VERSION 5.7 ;
  NOWIREEXTENSIONATPIN ON ;
  DIVIDERCHAR "/" ;
  BUSBITCHARS "[]" ;
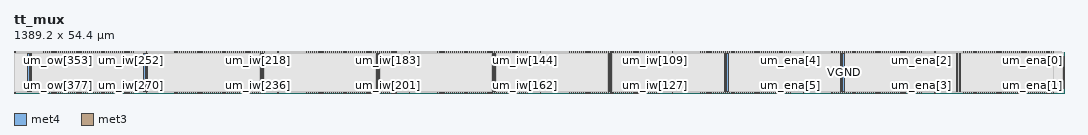
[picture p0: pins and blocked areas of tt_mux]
MACRO tt_mux
  CLASS BLOCK ;
  FOREIGN tt_mux ;
  ORIGIN 0.000 0.000 ;
  SIZE 1389.200 BY 54.400 ;
  PIN VDPWR
    DIRECTION INOUT ;
    USE POWER ;
    PORT
      LAYER met4 ;
        RECT 18.280 2.480 19.880 51.920 ;
    END
    PORT
      LAYER met4 ;
        RECT 171.880 2.480 173.480 51.920 ;
    END
    PORT
      LAYER met4 ;
        RECT 325.480 2.480 327.080 51.920 ;
    END
    PORT
      LAYER met4 ;
        RECT 479.080 2.480 480.680 51.920 ;
    END
    PORT
      LAYER met4 ;
        RECT 632.680 2.480 634.280 51.920 ;
    END
    PORT
      LAYER met4 ;
        RECT 786.280 2.480 787.880 51.920 ;
    END
    PORT
      LAYER met4 ;
        RECT 939.880 2.480 941.480 51.920 ;
    END
    PORT
      LAYER met4 ;
        RECT 1093.480 2.480 1095.080 51.920 ;
    END
    PORT
      LAYER met4 ;
        RECT 1247.080 2.480 1248.680 51.920 ;
    END
  END VDPWR
  PIN VGND
    DIRECTION INOUT ;
    USE GROUND ;
    PORT
      LAYER met4 ;
        RECT 21.580 2.480 23.180 51.920 ;
    END
    PORT
      LAYER met4 ;
        RECT 175.180 2.480 176.780 51.920 ;
    END
    PORT
      LAYER met4 ;
        RECT 328.780 2.480 330.380 51.920 ;
    END
    PORT
      LAYER met4 ;
        RECT 482.380 2.480 483.980 51.920 ;
    END
    PORT
      LAYER met4 ;
        RECT 635.980 2.480 637.580 51.920 ;
    END
    PORT
      LAYER met4 ;
        RECT 789.580 2.480 791.180 51.920 ;
    END
    PORT
      LAYER met4 ;
        RECT 943.180 2.480 944.780 51.920 ;
    END
    PORT
      LAYER met4 ;
        RECT 1096.780 2.480 1098.380 51.920 ;
    END
    PORT
      LAYER met4 ;
        RECT 1250.380 2.480 1251.980 51.920 ;
    END
  END VGND
  PIN addr[0]
    DIRECTION INPUT ;
    USE SIGNAL ;
    ANTENNAGATEAREA 0.252000 ;
    PORT
      LAYER met3 ;
        RECT 1388.200 47.790 1389.200 48.090 ;
    END
  END addr[0]
  PIN addr[1]
    DIRECTION INPUT ;
    USE SIGNAL ;
    ANTENNAGATEAREA 0.990000 ;
    PORT
      LAYER met3 ;
        RECT 1388.200 47.110 1389.200 47.410 ;
    END
  END addr[1]
  PIN addr[2]
    DIRECTION INPUT ;
    USE SIGNAL ;
    ANTENNAGATEAREA 0.495000 ;
    PORT
      LAYER met3 ;
        RECT 1388.200 46.430 1389.200 46.730 ;
    END
  END addr[2]
  PIN addr[3]
    DIRECTION INPUT ;
    USE SIGNAL ;
    ANTENNAGATEAREA 0.990000 ;
    PORT
      LAYER met3 ;
        RECT 1388.200 45.750 1389.200 46.050 ;
    END
  END addr[3]
  PIN k_one
    DIRECTION OUTPUT ;
    USE SIGNAL ;
    PORT
      LAYER met3 ;
        RECT 1388.200 45.070 1389.200 45.370 ;
    END
  END k_one
  PIN k_zero
    DIRECTION OUTPUT ;
    USE SIGNAL ;
    PORT
      LAYER met3 ;
        RECT 1388.200 44.390 1389.200 44.690 ;
    END
  END k_zero
  PIN spine_iw[0]
    DIRECTION INPUT ;
    USE SIGNAL ;
    ANTENNAGATEAREA 0.434700 ;
    ANTENNADIFFAREA 0.434700 ;
    PORT
      LAYER met3 ;
        RECT 1388.200 43.710 1389.200 44.010 ;
    END
  END spine_iw[0]
  PIN spine_iw[10]
    DIRECTION INPUT ;
    USE SIGNAL ;
    ANTENNAGATEAREA 0.593700 ;
    ANTENNADIFFAREA 0.434700 ;
    PORT
      LAYER met3 ;
        RECT 1388.200 36.910 1389.200 37.210 ;
    END
  END spine_iw[10]
  PIN spine_iw[11]
    DIRECTION INPUT ;
    USE SIGNAL ;
    ANTENNAGATEAREA 0.560700 ;
    ANTENNADIFFAREA 0.434700 ;
    PORT
      LAYER met3 ;
        RECT 1388.200 36.230 1389.200 36.530 ;
    END
  END spine_iw[11]
  PIN spine_iw[12]
    DIRECTION INPUT ;
    USE SIGNAL ;
    ANTENNAGATEAREA 0.560700 ;
    ANTENNADIFFAREA 0.434700 ;
    PORT
      LAYER met3 ;
        RECT 1388.200 35.550 1389.200 35.850 ;
    END
  END spine_iw[12]
  PIN spine_iw[13]
    DIRECTION INPUT ;
    USE SIGNAL ;
    ANTENNAGATEAREA 0.560700 ;
    ANTENNADIFFAREA 0.434700 ;
    PORT
      LAYER met3 ;
        RECT 1388.200 34.870 1389.200 35.170 ;
    END
  END spine_iw[13]
  PIN spine_iw[14]
    DIRECTION INPUT ;
    USE SIGNAL ;
    ANTENNAGATEAREA 0.560700 ;
    ANTENNADIFFAREA 0.434700 ;
    PORT
      LAYER met3 ;
        RECT 1388.200 34.190 1389.200 34.490 ;
    END
  END spine_iw[14]
  PIN spine_iw[15]
    DIRECTION INPUT ;
    USE SIGNAL ;
    ANTENNAGATEAREA 0.560700 ;
    ANTENNADIFFAREA 0.434700 ;
    PORT
      LAYER met3 ;
        RECT 1388.200 33.510 1389.200 33.810 ;
    END
  END spine_iw[15]
  PIN spine_iw[16]
    DIRECTION INPUT ;
    USE SIGNAL ;
    ANTENNAGATEAREA 0.560700 ;
    ANTENNADIFFAREA 0.434700 ;
    PORT
      LAYER met3 ;
        RECT 1388.200 32.830 1389.200 33.130 ;
    END
  END spine_iw[16]
  PIN spine_iw[17]
    DIRECTION INPUT ;
    USE SIGNAL ;
    ANTENNAGATEAREA 0.560700 ;
    ANTENNADIFFAREA 0.434700 ;
    PORT
      LAYER met3 ;
        RECT 1388.200 32.150 1389.200 32.450 ;
    END
  END spine_iw[17]
  PIN spine_iw[18]
    DIRECTION INPUT ;
    USE SIGNAL ;
    ANTENNAGATEAREA 0.560700 ;
    ANTENNADIFFAREA 0.434700 ;
    PORT
      LAYER met3 ;
        RECT 1388.200 31.470 1389.200 31.770 ;
    END
  END spine_iw[18]
  PIN spine_iw[19]
    DIRECTION INPUT ;
    USE SIGNAL ;
    ANTENNAGATEAREA 0.560700 ;
    ANTENNADIFFAREA 0.434700 ;
    PORT
      LAYER met3 ;
        RECT 1388.200 30.790 1389.200 31.090 ;
    END
  END spine_iw[19]
  PIN spine_iw[1]
    DIRECTION INPUT ;
    USE SIGNAL ;
    ANTENNAGATEAREA 0.593700 ;
    ANTENNADIFFAREA 0.434700 ;
    PORT
      LAYER met3 ;
        RECT 1388.200 43.030 1389.200 43.330 ;
    END
  END spine_iw[1]
  PIN spine_iw[20]
    DIRECTION INPUT ;
    USE SIGNAL ;
    ANTENNAGATEAREA 0.560700 ;
    ANTENNADIFFAREA 0.434700 ;
    PORT
      LAYER met3 ;
        RECT 1388.200 30.110 1389.200 30.410 ;
    END
  END spine_iw[20]
  PIN spine_iw[21]
    DIRECTION INPUT ;
    USE SIGNAL ;
    ANTENNAGATEAREA 0.560700 ;
    ANTENNADIFFAREA 0.434700 ;
    PORT
      LAYER met3 ;
        RECT 1388.200 29.430 1389.200 29.730 ;
    END
  END spine_iw[21]
  PIN spine_iw[22]
    DIRECTION INPUT ;
    USE SIGNAL ;
    ANTENNAGATEAREA 0.560700 ;
    ANTENNADIFFAREA 0.434700 ;
    PORT
      LAYER met3 ;
        RECT 1388.200 28.750 1389.200 29.050 ;
    END
  END spine_iw[22]
  PIN spine_iw[23]
    DIRECTION INPUT ;
    USE SIGNAL ;
    ANTENNAGATEAREA 0.560700 ;
    ANTENNADIFFAREA 0.434700 ;
    PORT
      LAYER met3 ;
        RECT 1388.200 28.070 1389.200 28.370 ;
    END
  END spine_iw[23]
  PIN spine_iw[24]
    DIRECTION INPUT ;
    USE SIGNAL ;
    ANTENNAGATEAREA 0.560700 ;
    ANTENNADIFFAREA 0.434700 ;
    PORT
      LAYER met3 ;
        RECT 1388.200 27.390 1389.200 27.690 ;
    END
  END spine_iw[24]
  PIN spine_iw[25]
    DIRECTION INPUT ;
    USE SIGNAL ;
    ANTENNAGATEAREA 0.560700 ;
    ANTENNADIFFAREA 0.434700 ;
    PORT
      LAYER met3 ;
        RECT 1388.200 26.710 1389.200 27.010 ;
    END
  END spine_iw[25]
  PIN spine_iw[26]
    DIRECTION INPUT ;
    USE SIGNAL ;
    ANTENNAGATEAREA 0.560700 ;
    ANTENNADIFFAREA 0.434700 ;
    PORT
      LAYER met3 ;
        RECT 1388.200 26.030 1389.200 26.330 ;
    END
  END spine_iw[26]
  PIN spine_iw[27]
    DIRECTION INPUT ;
    USE SIGNAL ;
    ANTENNAGATEAREA 0.560700 ;
    ANTENNADIFFAREA 0.434700 ;
    PORT
      LAYER met3 ;
        RECT 1388.200 25.350 1389.200 25.650 ;
    END
  END spine_iw[27]
  PIN spine_iw[28]
    DIRECTION INPUT ;
    USE SIGNAL ;
    ANTENNAGATEAREA 0.560700 ;
    ANTENNADIFFAREA 0.434700 ;
    PORT
      LAYER met3 ;
        RECT 1388.200 24.670 1389.200 24.970 ;
    END
  END spine_iw[28]
  PIN spine_iw[29]
    DIRECTION INPUT ;
    USE SIGNAL ;
    ANTENNAGATEAREA 0.434700 ;
    ANTENNADIFFAREA 0.434700 ;
    PORT
      LAYER met3 ;
        RECT 1388.200 23.990 1389.200 24.290 ;
    END
  END spine_iw[29]
  PIN spine_iw[2]
    DIRECTION INPUT ;
    USE SIGNAL ;
    ANTENNAGATEAREA 1.177200 ;
    ANTENNADIFFAREA 0.434700 ;
    PORT
      LAYER met3 ;
        RECT 1388.200 42.350 1389.200 42.650 ;
    END
  END spine_iw[2]
  PIN spine_iw[3]
    DIRECTION INPUT ;
    USE SIGNAL ;
    ANTENNAGATEAREA 1.177200 ;
    ANTENNADIFFAREA 0.434700 ;
    PORT
      LAYER met3 ;
        RECT 1388.200 41.670 1389.200 41.970 ;
    END
  END spine_iw[3]
  PIN spine_iw[4]
    DIRECTION INPUT ;
    USE SIGNAL ;
    ANTENNAGATEAREA 1.177200 ;
    ANTENNADIFFAREA 0.434700 ;
    PORT
      LAYER met3 ;
        RECT 1388.200 40.990 1389.200 41.290 ;
    END
  END spine_iw[4]
  PIN spine_iw[5]
    DIRECTION INPUT ;
    USE SIGNAL ;
    ANTENNAGATEAREA 1.177200 ;
    ANTENNADIFFAREA 0.434700 ;
    PORT
      LAYER met3 ;
        RECT 1388.200 40.310 1389.200 40.610 ;
    END
  END spine_iw[5]
  PIN spine_iw[6]
    DIRECTION INPUT ;
    USE SIGNAL ;
    ANTENNAGATEAREA 1.177200 ;
    ANTENNADIFFAREA 0.434700 ;
    PORT
      LAYER met3 ;
        RECT 1388.200 39.630 1389.200 39.930 ;
    END
  END spine_iw[6]
  PIN spine_iw[7]
    DIRECTION INPUT ;
    USE SIGNAL ;
    ANTENNAGATEAREA 0.593700 ;
    ANTENNADIFFAREA 0.434700 ;
    PORT
      LAYER met3 ;
        RECT 1388.200 38.950 1389.200 39.250 ;
    END
  END spine_iw[7]
  PIN spine_iw[8]
    DIRECTION INPUT ;
    USE SIGNAL ;
    ANTENNAGATEAREA 0.593700 ;
    ANTENNADIFFAREA 0.434700 ;
    PORT
      LAYER met3 ;
        RECT 1388.200 38.270 1389.200 38.570 ;
    END
  END spine_iw[8]
  PIN spine_iw[9]
    DIRECTION INPUT ;
    USE SIGNAL ;
    ANTENNAGATEAREA 0.593700 ;
    ANTENNADIFFAREA 0.434700 ;
    PORT
      LAYER met3 ;
        RECT 1388.200 37.590 1389.200 37.890 ;
    END
  END spine_iw[9]
  PIN spine_ow[0]
    DIRECTION OUTPUT ;
    USE SIGNAL ;
    PORT
      LAYER met3 ;
        RECT 1388.200 23.310 1389.200 23.610 ;
    END
  END spine_ow[0]
  PIN spine_ow[10]
    DIRECTION OUTPUT ;
    USE SIGNAL ;
    ANTENNADIFFAREA 1.782000 ;
    PORT
      LAYER met3 ;
        RECT 1388.200 16.510 1389.200 16.810 ;
    END
  END spine_ow[10]
  PIN spine_ow[11]
    DIRECTION OUTPUT ;
    USE SIGNAL ;
    ANTENNADIFFAREA 1.782000 ;
    PORT
      LAYER met3 ;
        RECT 1388.200 15.830 1389.200 16.130 ;
    END
  END spine_ow[11]
  PIN spine_ow[12]
    DIRECTION OUTPUT ;
    USE SIGNAL ;
    ANTENNADIFFAREA 1.782000 ;
    PORT
      LAYER met3 ;
        RECT 1388.200 15.150 1389.200 15.450 ;
    END
  END spine_ow[12]
  PIN spine_ow[13]
    DIRECTION OUTPUT ;
    USE SIGNAL ;
    ANTENNADIFFAREA 1.782000 ;
    PORT
      LAYER met3 ;
        RECT 1388.200 14.470 1389.200 14.770 ;
    END
  END spine_ow[13]
  PIN spine_ow[14]
    DIRECTION OUTPUT ;
    USE SIGNAL ;
    ANTENNADIFFAREA 1.782000 ;
    PORT
      LAYER met3 ;
        RECT 1388.200 13.790 1389.200 14.090 ;
    END
  END spine_ow[14]
  PIN spine_ow[15]
    DIRECTION OUTPUT ;
    USE SIGNAL ;
    ANTENNADIFFAREA 1.782000 ;
    PORT
      LAYER met3 ;
        RECT 1388.200 13.110 1389.200 13.410 ;
    END
  END spine_ow[15]
  PIN spine_ow[16]
    DIRECTION OUTPUT ;
    USE SIGNAL ;
    ANTENNADIFFAREA 1.782000 ;
    PORT
      LAYER met3 ;
        RECT 1388.200 12.430 1389.200 12.730 ;
    END
  END spine_ow[16]
  PIN spine_ow[17]
    DIRECTION OUTPUT ;
    USE SIGNAL ;
    ANTENNADIFFAREA 1.782000 ;
    PORT
      LAYER met3 ;
        RECT 1388.200 11.750 1389.200 12.050 ;
    END
  END spine_ow[17]
  PIN spine_ow[18]
    DIRECTION OUTPUT ;
    USE SIGNAL ;
    ANTENNADIFFAREA 1.782000 ;
    PORT
      LAYER met3 ;
        RECT 1388.200 11.070 1389.200 11.370 ;
    END
  END spine_ow[18]
  PIN spine_ow[19]
    DIRECTION OUTPUT ;
    USE SIGNAL ;
    ANTENNADIFFAREA 1.782000 ;
    PORT
      LAYER met3 ;
        RECT 1388.200 10.390 1389.200 10.690 ;
    END
  END spine_ow[19]
  PIN spine_ow[1]
    DIRECTION OUTPUT ;
    USE SIGNAL ;
    ANTENNADIFFAREA 1.782000 ;
    PORT
      LAYER met3 ;
        RECT 1388.200 22.630 1389.200 22.930 ;
    END
  END spine_ow[1]
  PIN spine_ow[20]
    DIRECTION OUTPUT ;
    USE SIGNAL ;
    ANTENNADIFFAREA 1.782000 ;
    PORT
      LAYER met3 ;
        RECT 1388.200 9.710 1389.200 10.010 ;
    END
  END spine_ow[20]
  PIN spine_ow[21]
    DIRECTION OUTPUT ;
    USE SIGNAL ;
    ANTENNADIFFAREA 1.782000 ;
    PORT
      LAYER met3 ;
        RECT 1388.200 9.030 1389.200 9.330 ;
    END
  END spine_ow[21]
  PIN spine_ow[22]
    DIRECTION OUTPUT ;
    USE SIGNAL ;
    ANTENNADIFFAREA 1.782000 ;
    PORT
      LAYER met3 ;
        RECT 1388.200 8.350 1389.200 8.650 ;
    END
  END spine_ow[22]
  PIN spine_ow[23]
    DIRECTION OUTPUT ;
    USE SIGNAL ;
    ANTENNADIFFAREA 1.782000 ;
    PORT
      LAYER met3 ;
        RECT 1388.200 7.670 1389.200 7.970 ;
    END
  END spine_ow[23]
  PIN spine_ow[24]
    DIRECTION OUTPUT ;
    USE SIGNAL ;
    ANTENNADIFFAREA 1.782000 ;
    PORT
      LAYER met3 ;
        RECT 1388.200 6.990 1389.200 7.290 ;
    END
  END spine_ow[24]
  PIN spine_ow[25]
    DIRECTION OUTPUT ;
    USE SIGNAL ;
    PORT
      LAYER met3 ;
        RECT 1388.200 6.310 1389.200 6.610 ;
    END
  END spine_ow[25]
  PIN spine_ow[2]
    DIRECTION OUTPUT ;
    USE SIGNAL ;
    ANTENNADIFFAREA 1.782000 ;
    PORT
      LAYER met3 ;
        RECT 1388.200 21.950 1389.200 22.250 ;
    END
  END spine_ow[2]
  PIN spine_ow[3]
    DIRECTION OUTPUT ;
    USE SIGNAL ;
    ANTENNADIFFAREA 1.782000 ;
    PORT
      LAYER met3 ;
        RECT 1388.200 21.270 1389.200 21.570 ;
    END
  END spine_ow[3]
  PIN spine_ow[4]
    DIRECTION OUTPUT ;
    USE SIGNAL ;
    ANTENNADIFFAREA 1.782000 ;
    PORT
      LAYER met3 ;
        RECT 1388.200 20.590 1389.200 20.890 ;
    END
  END spine_ow[4]
  PIN spine_ow[5]
    DIRECTION OUTPUT ;
    USE SIGNAL ;
    ANTENNADIFFAREA 1.782000 ;
    PORT
      LAYER met3 ;
        RECT 1388.200 19.910 1389.200 20.210 ;
    END
  END spine_ow[5]
  PIN spine_ow[6]
    DIRECTION OUTPUT ;
    USE SIGNAL ;
    ANTENNADIFFAREA 1.782000 ;
    PORT
      LAYER met3 ;
        RECT 1388.200 19.230 1389.200 19.530 ;
    END
  END spine_ow[6]
  PIN spine_ow[7]
    DIRECTION OUTPUT ;
    USE SIGNAL ;
    ANTENNADIFFAREA 1.782000 ;
    PORT
      LAYER met3 ;
        RECT 1388.200 18.550 1389.200 18.850 ;
    END
  END spine_ow[7]
  PIN spine_ow[8]
    DIRECTION OUTPUT ;
    USE SIGNAL ;
    ANTENNADIFFAREA 1.782000 ;
    PORT
      LAYER met3 ;
        RECT 1388.200 17.870 1389.200 18.170 ;
    END
  END spine_ow[8]
  PIN spine_ow[9]
    DIRECTION OUTPUT ;
    USE SIGNAL ;
    ANTENNADIFFAREA 1.782000 ;
    PORT
      LAYER met3 ;
        RECT 1388.200 17.190 1389.200 17.490 ;
    END
  END spine_ow[9]
  PIN um_ena[0]
    DIRECTION OUTPUT ;
    USE SIGNAL ;
    ANTENNADIFFAREA 0.445500 ;
    PORT
      LAYER met4 ;
        RECT 1374.790 53.400 1375.090 54.400 ;
    END
  END um_ena[0]
  PIN um_ena[10]
    DIRECTION OUTPUT ;
    USE SIGNAL ;
    ANTENNADIFFAREA 0.445500 ;
    PORT
      LAYER met4 ;
        RECT 505.390 53.400 505.690 54.400 ;
    END
  END um_ena[10]
  PIN um_ena[11]
    DIRECTION OUTPUT ;
    USE SIGNAL ;
    ANTENNADIFFAREA 0.445500 ;
    PORT
      LAYER met4 ;
        RECT 505.390 0.000 505.690 1.000 ;
    END
  END um_ena[11]
  PIN um_ena[12]
    DIRECTION OUTPUT ;
    USE SIGNAL ;
    ANTENNADIFFAREA 0.445500 ;
    PORT
      LAYER met4 ;
        RECT 331.510 53.400 331.810 54.400 ;
    END
  END um_ena[12]
  PIN um_ena[13]
    DIRECTION OUTPUT ;
    USE SIGNAL ;
    ANTENNADIFFAREA 0.445500 ;
    PORT
      LAYER met4 ;
        RECT 331.510 0.000 331.810 1.000 ;
    END
  END um_ena[13]
  PIN um_ena[14]
    DIRECTION OUTPUT ;
    USE SIGNAL ;
    ANTENNADIFFAREA 0.445500 ;
    PORT
      LAYER met4 ;
        RECT 157.630 53.400 157.930 54.400 ;
    END
  END um_ena[14]
  PIN um_ena[15]
    DIRECTION OUTPUT ;
    USE SIGNAL ;
    ANTENNADIFFAREA 0.445500 ;
    PORT
      LAYER met4 ;
        RECT 157.630 0.000 157.930 1.000 ;
    END
  END um_ena[15]
  PIN um_ena[1]
    DIRECTION OUTPUT ;
    USE SIGNAL ;
    ANTENNADIFFAREA 0.445500 ;
    PORT
      LAYER met4 ;
        RECT 1374.790 0.000 1375.090 1.000 ;
    END
  END um_ena[1]
  PIN um_ena[2]
    DIRECTION OUTPUT ;
    USE SIGNAL ;
    ANTENNADIFFAREA 0.445500 ;
    PORT
      LAYER met4 ;
        RECT 1200.910 53.400 1201.210 54.400 ;
    END
  END um_ena[2]
  PIN um_ena[3]
    DIRECTION OUTPUT ;
    USE SIGNAL ;
    ANTENNADIFFAREA 0.445500 ;
    PORT
      LAYER met4 ;
        RECT 1200.910 0.000 1201.210 1.000 ;
    END
  END um_ena[3]
  PIN um_ena[4]
    DIRECTION OUTPUT ;
    USE SIGNAL ;
    ANTENNADIFFAREA 0.445500 ;
    PORT
      LAYER met4 ;
        RECT 1027.030 53.400 1027.330 54.400 ;
    END
  END um_ena[4]
  PIN um_ena[5]
    DIRECTION OUTPUT ;
    USE SIGNAL ;
    ANTENNADIFFAREA 0.445500 ;
    PORT
      LAYER met4 ;
        RECT 1027.030 0.000 1027.330 1.000 ;
    END
  END um_ena[5]
  PIN um_ena[6]
    DIRECTION OUTPUT ;
    USE SIGNAL ;
    ANTENNADIFFAREA 0.445500 ;
    PORT
      LAYER met4 ;
        RECT 853.150 53.400 853.450 54.400 ;
    END
  END um_ena[6]
  PIN um_ena[7]
    DIRECTION OUTPUT ;
    USE SIGNAL ;
    ANTENNADIFFAREA 0.445500 ;
    PORT
      LAYER met4 ;
        RECT 853.150 0.000 853.450 1.000 ;
    END
  END um_ena[7]
  PIN um_ena[8]
    DIRECTION OUTPUT ;
    USE SIGNAL ;
    ANTENNADIFFAREA 0.445500 ;
    PORT
      LAYER met4 ;
        RECT 679.270 53.400 679.570 54.400 ;
    END
  END um_ena[8]
  PIN um_ena[9]
    DIRECTION OUTPUT ;
    USE SIGNAL ;
    ANTENNADIFFAREA 0.445500 ;
    PORT
      LAYER met4 ;
        RECT 679.270 0.000 679.570 1.000 ;
    END
  END um_ena[9]
  PIN um_iw[0]
    DIRECTION OUTPUT ;
    USE SIGNAL ;
    ANTENNADIFFAREA 0.643500 ;
    PORT
      LAYER met4 ;
        RECT 1372.030 53.400 1372.330 54.400 ;
    END
  END um_iw[0]
  PIN um_iw[100]
    DIRECTION OUTPUT ;
    USE SIGNAL ;
    ANTENNADIFFAREA 0.643500 ;
    PORT
      LAYER met4 ;
        RECT 996.670 0.000 996.970 1.000 ;
    END
  END um_iw[100]
  PIN um_iw[101]
    DIRECTION OUTPUT ;
    USE SIGNAL ;
    ANTENNADIFFAREA 0.643500 ;
    PORT
      LAYER met4 ;
        RECT 993.910 0.000 994.210 1.000 ;
    END
  END um_iw[101]
  PIN um_iw[102]
    DIRECTION OUTPUT ;
    USE SIGNAL ;
    ANTENNADIFFAREA 0.643500 ;
    PORT
      LAYER met4 ;
        RECT 991.150 0.000 991.450 1.000 ;
    END
  END um_iw[102]
  PIN um_iw[103]
    DIRECTION OUTPUT ;
    USE SIGNAL ;
    ANTENNADIFFAREA 0.643500 ;
    PORT
      LAYER met4 ;
        RECT 988.390 0.000 988.690 1.000 ;
    END
  END um_iw[103]
  PIN um_iw[104]
    DIRECTION OUTPUT ;
    USE SIGNAL ;
    ANTENNADIFFAREA 0.643500 ;
    PORT
      LAYER met4 ;
        RECT 985.630 0.000 985.930 1.000 ;
    END
  END um_iw[104]
  PIN um_iw[105]
    DIRECTION OUTPUT ;
    USE SIGNAL ;
    ANTENNADIFFAREA 0.643500 ;
    PORT
      LAYER met4 ;
        RECT 982.870 0.000 983.170 1.000 ;
    END
  END um_iw[105]
  PIN um_iw[106]
    DIRECTION OUTPUT ;
    USE SIGNAL ;
    ANTENNADIFFAREA 0.643500 ;
    PORT
      LAYER met4 ;
        RECT 980.110 0.000 980.410 1.000 ;
    END
  END um_iw[106]
  PIN um_iw[107]
    DIRECTION OUTPUT ;
    USE SIGNAL ;
    ANTENNADIFFAREA 0.643500 ;
    PORT
      LAYER met4 ;
        RECT 977.350 0.000 977.650 1.000 ;
    END
  END um_iw[107]
  PIN um_iw[108]
    DIRECTION OUTPUT ;
    USE SIGNAL ;
    ANTENNADIFFAREA 0.643500 ;
    PORT
      LAYER met4 ;
        RECT 850.390 53.400 850.690 54.400 ;
    END
  END um_iw[108]
  PIN um_iw[109]
    DIRECTION OUTPUT ;
    USE SIGNAL ;
    ANTENNADIFFAREA 0.643500 ;
    PORT
      LAYER met4 ;
        RECT 847.630 53.400 847.930 54.400 ;
    END
  END um_iw[109]
  PIN um_iw[10]
    DIRECTION OUTPUT ;
    USE SIGNAL ;
    ANTENNADIFFAREA 0.643500 ;
    PORT
      LAYER met4 ;
        RECT 1344.430 53.400 1344.730 54.400 ;
    END
  END um_iw[10]
  PIN um_iw[110]
    DIRECTION OUTPUT ;
    USE SIGNAL ;
    ANTENNADIFFAREA 0.643500 ;
    PORT
      LAYER met4 ;
        RECT 844.870 53.400 845.170 54.400 ;
    END
  END um_iw[110]
  PIN um_iw[111]
    DIRECTION OUTPUT ;
    USE SIGNAL ;
    ANTENNADIFFAREA 0.643500 ;
    PORT
      LAYER met4 ;
        RECT 842.110 53.400 842.410 54.400 ;
    END
  END um_iw[111]
  PIN um_iw[112]
    DIRECTION OUTPUT ;
    USE SIGNAL ;
    ANTENNADIFFAREA 0.643500 ;
    PORT
      LAYER met4 ;
        RECT 839.350 53.400 839.650 54.400 ;
    END
  END um_iw[112]
  PIN um_iw[113]
    DIRECTION OUTPUT ;
    USE SIGNAL ;
    ANTENNADIFFAREA 0.643500 ;
    PORT
      LAYER met4 ;
        RECT 836.590 53.400 836.890 54.400 ;
    END
  END um_iw[113]
  PIN um_iw[114]
    DIRECTION OUTPUT ;
    USE SIGNAL ;
    ANTENNADIFFAREA 0.643500 ;
    PORT
      LAYER met4 ;
        RECT 833.830 53.400 834.130 54.400 ;
    END
  END um_iw[114]
  PIN um_iw[115]
    DIRECTION OUTPUT ;
    USE SIGNAL ;
    ANTENNADIFFAREA 0.643500 ;
    PORT
      LAYER met4 ;
        RECT 831.070 53.400 831.370 54.400 ;
    END
  END um_iw[115]
  PIN um_iw[116]
    DIRECTION OUTPUT ;
    USE SIGNAL ;
    ANTENNADIFFAREA 0.643500 ;
    PORT
      LAYER met4 ;
        RECT 828.310 53.400 828.610 54.400 ;
    END
  END um_iw[116]
  PIN um_iw[117]
    DIRECTION OUTPUT ;
    USE SIGNAL ;
    ANTENNADIFFAREA 0.643500 ;
    PORT
      LAYER met4 ;
        RECT 825.550 53.400 825.850 54.400 ;
    END
  END um_iw[117]
  PIN um_iw[118]
    DIRECTION OUTPUT ;
    USE SIGNAL ;
    ANTENNADIFFAREA 0.643500 ;
    PORT
      LAYER met4 ;
        RECT 822.790 53.400 823.090 54.400 ;
    END
  END um_iw[118]
  PIN um_iw[119]
    DIRECTION OUTPUT ;
    USE SIGNAL ;
    ANTENNADIFFAREA 0.643500 ;
    PORT
      LAYER met4 ;
        RECT 820.030 53.400 820.330 54.400 ;
    END
  END um_iw[119]
  PIN um_iw[11]
    DIRECTION OUTPUT ;
    USE SIGNAL ;
    ANTENNADIFFAREA 0.643500 ;
    PORT
      LAYER met4 ;
        RECT 1341.670 53.400 1341.970 54.400 ;
    END
  END um_iw[11]
  PIN um_iw[120]
    DIRECTION OUTPUT ;
    USE SIGNAL ;
    ANTENNADIFFAREA 0.643500 ;
    PORT
      LAYER met4 ;
        RECT 817.270 53.400 817.570 54.400 ;
    END
  END um_iw[120]
  PIN um_iw[121]
    DIRECTION OUTPUT ;
    USE SIGNAL ;
    ANTENNADIFFAREA 0.643500 ;
    PORT
      LAYER met4 ;
        RECT 814.510 53.400 814.810 54.400 ;
    END
  END um_iw[121]
  PIN um_iw[122]
    DIRECTION OUTPUT ;
    USE SIGNAL ;
    ANTENNADIFFAREA 0.643500 ;
    PORT
      LAYER met4 ;
        RECT 811.750 53.400 812.050 54.400 ;
    END
  END um_iw[122]
  PIN um_iw[123]
    DIRECTION OUTPUT ;
    USE SIGNAL ;
    ANTENNADIFFAREA 0.643500 ;
    PORT
      LAYER met4 ;
        RECT 808.990 53.400 809.290 54.400 ;
    END
  END um_iw[123]
  PIN um_iw[124]
    DIRECTION OUTPUT ;
    USE SIGNAL ;
    ANTENNADIFFAREA 0.643500 ;
    PORT
      LAYER met4 ;
        RECT 806.230 53.400 806.530 54.400 ;
    END
  END um_iw[124]
  PIN um_iw[125]
    DIRECTION OUTPUT ;
    USE SIGNAL ;
    ANTENNADIFFAREA 0.643500 ;
    PORT
      LAYER met4 ;
        RECT 803.470 53.400 803.770 54.400 ;
    END
  END um_iw[125]
  PIN um_iw[126]
    DIRECTION OUTPUT ;
    USE SIGNAL ;
    ANTENNADIFFAREA 0.643500 ;
    PORT
      LAYER met4 ;
        RECT 850.390 0.000 850.690 1.000 ;
    END
  END um_iw[126]
  PIN um_iw[127]
    DIRECTION OUTPUT ;
    USE SIGNAL ;
    ANTENNADIFFAREA 0.643500 ;
    PORT
      LAYER met4 ;
        RECT 847.630 0.000 847.930 1.000 ;
    END
  END um_iw[127]
  PIN um_iw[128]
    DIRECTION OUTPUT ;
    USE SIGNAL ;
    ANTENNADIFFAREA 0.643500 ;
    PORT
      LAYER met4 ;
        RECT 844.870 0.000 845.170 1.000 ;
    END
  END um_iw[128]
  PIN um_iw[129]
    DIRECTION OUTPUT ;
    USE SIGNAL ;
    ANTENNADIFFAREA 0.643500 ;
    PORT
      LAYER met4 ;
        RECT 842.110 0.000 842.410 1.000 ;
    END
  END um_iw[129]
  PIN um_iw[12]
    DIRECTION OUTPUT ;
    USE SIGNAL ;
    ANTENNADIFFAREA 0.643500 ;
    PORT
      LAYER met4 ;
        RECT 1338.910 53.400 1339.210 54.400 ;
    END
  END um_iw[12]
  PIN um_iw[130]
    DIRECTION OUTPUT ;
    USE SIGNAL ;
    ANTENNADIFFAREA 0.643500 ;
    PORT
      LAYER met4 ;
        RECT 839.350 0.000 839.650 1.000 ;
    END
  END um_iw[130]
  PIN um_iw[131]
    DIRECTION OUTPUT ;
    USE SIGNAL ;
    ANTENNADIFFAREA 0.643500 ;
    PORT
      LAYER met4 ;
        RECT 836.590 0.000 836.890 1.000 ;
    END
  END um_iw[131]
  PIN um_iw[132]
    DIRECTION OUTPUT ;
    USE SIGNAL ;
    ANTENNADIFFAREA 0.643500 ;
    PORT
      LAYER met4 ;
        RECT 833.830 0.000 834.130 1.000 ;
    END
  END um_iw[132]
  PIN um_iw[133]
    DIRECTION OUTPUT ;
    USE SIGNAL ;
    ANTENNADIFFAREA 0.643500 ;
    PORT
      LAYER met4 ;
        RECT 831.070 0.000 831.370 1.000 ;
    END
  END um_iw[133]
  PIN um_iw[134]
    DIRECTION OUTPUT ;
    USE SIGNAL ;
    ANTENNADIFFAREA 0.643500 ;
    PORT
      LAYER met4 ;
        RECT 828.310 0.000 828.610 1.000 ;
    END
  END um_iw[134]
  PIN um_iw[135]
    DIRECTION OUTPUT ;
    USE SIGNAL ;
    ANTENNADIFFAREA 0.643500 ;
    PORT
      LAYER met4 ;
        RECT 825.550 0.000 825.850 1.000 ;
    END
  END um_iw[135]
  PIN um_iw[136]
    DIRECTION OUTPUT ;
    USE SIGNAL ;
    ANTENNADIFFAREA 0.643500 ;
    PORT
      LAYER met4 ;
        RECT 822.790 0.000 823.090 1.000 ;
    END
  END um_iw[136]
  PIN um_iw[137]
    DIRECTION OUTPUT ;
    USE SIGNAL ;
    ANTENNADIFFAREA 0.643500 ;
    PORT
      LAYER met4 ;
        RECT 820.030 0.000 820.330 1.000 ;
    END
  END um_iw[137]
  PIN um_iw[138]
    DIRECTION OUTPUT ;
    USE SIGNAL ;
    ANTENNADIFFAREA 0.643500 ;
    PORT
      LAYER met4 ;
        RECT 817.270 0.000 817.570 1.000 ;
    END
  END um_iw[138]
  PIN um_iw[139]
    DIRECTION OUTPUT ;
    USE SIGNAL ;
    ANTENNADIFFAREA 0.643500 ;
    PORT
      LAYER met4 ;
        RECT 814.510 0.000 814.810 1.000 ;
    END
  END um_iw[139]
  PIN um_iw[13]
    DIRECTION OUTPUT ;
    USE SIGNAL ;
    ANTENNADIFFAREA 0.643500 ;
    PORT
      LAYER met4 ;
        RECT 1336.150 53.400 1336.450 54.400 ;
    END
  END um_iw[13]
  PIN um_iw[140]
    DIRECTION OUTPUT ;
    USE SIGNAL ;
    ANTENNADIFFAREA 0.643500 ;
    PORT
      LAYER met4 ;
        RECT 811.750 0.000 812.050 1.000 ;
    END
  END um_iw[140]
  PIN um_iw[141]
    DIRECTION OUTPUT ;
    USE SIGNAL ;
    ANTENNADIFFAREA 0.643500 ;
    PORT
      LAYER met4 ;
        RECT 808.990 0.000 809.290 1.000 ;
    END
  END um_iw[141]
  PIN um_iw[142]
    DIRECTION OUTPUT ;
    USE SIGNAL ;
    ANTENNADIFFAREA 0.643500 ;
    PORT
      LAYER met4 ;
        RECT 806.230 0.000 806.530 1.000 ;
    END
  END um_iw[142]
  PIN um_iw[143]
    DIRECTION OUTPUT ;
    USE SIGNAL ;
    ANTENNADIFFAREA 0.643500 ;
    PORT
      LAYER met4 ;
        RECT 803.470 0.000 803.770 1.000 ;
    END
  END um_iw[143]
  PIN um_iw[144]
    DIRECTION OUTPUT ;
    USE SIGNAL ;
    ANTENNADIFFAREA 0.643500 ;
    PORT
      LAYER met4 ;
        RECT 676.510 53.400 676.810 54.400 ;
    END
  END um_iw[144]
  PIN um_iw[145]
    DIRECTION OUTPUT ;
    USE SIGNAL ;
    ANTENNADIFFAREA 0.643500 ;
    PORT
      LAYER met4 ;
        RECT 673.750 53.400 674.050 54.400 ;
    END
  END um_iw[145]
  PIN um_iw[146]
    DIRECTION OUTPUT ;
    USE SIGNAL ;
    ANTENNADIFFAREA 0.643500 ;
    PORT
      LAYER met4 ;
        RECT 670.990 53.400 671.290 54.400 ;
    END
  END um_iw[146]
  PIN um_iw[147]
    DIRECTION OUTPUT ;
    USE SIGNAL ;
    ANTENNADIFFAREA 0.643500 ;
    PORT
      LAYER met4 ;
        RECT 668.230 53.400 668.530 54.400 ;
    END
  END um_iw[147]
  PIN um_iw[148]
    DIRECTION OUTPUT ;
    USE SIGNAL ;
    ANTENNADIFFAREA 0.643500 ;
    PORT
      LAYER met4 ;
        RECT 665.470 53.400 665.770 54.400 ;
    END
  END um_iw[148]
  PIN um_iw[149]
    DIRECTION OUTPUT ;
    USE SIGNAL ;
    ANTENNADIFFAREA 0.643500 ;
    PORT
      LAYER met4 ;
        RECT 662.710 53.400 663.010 54.400 ;
    END
  END um_iw[149]
  PIN um_iw[14]
    DIRECTION OUTPUT ;
    USE SIGNAL ;
    ANTENNADIFFAREA 0.643500 ;
    PORT
      LAYER met4 ;
        RECT 1333.390 53.400 1333.690 54.400 ;
    END
  END um_iw[14]
  PIN um_iw[150]
    DIRECTION OUTPUT ;
    USE SIGNAL ;
    ANTENNADIFFAREA 0.643500 ;
    PORT
      LAYER met4 ;
        RECT 659.950 53.400 660.250 54.400 ;
    END
  END um_iw[150]
  PIN um_iw[151]
    DIRECTION OUTPUT ;
    USE SIGNAL ;
    ANTENNADIFFAREA 0.643500 ;
    PORT
      LAYER met4 ;
        RECT 657.190 53.400 657.490 54.400 ;
    END
  END um_iw[151]
  PIN um_iw[152]
    DIRECTION OUTPUT ;
    USE SIGNAL ;
    ANTENNADIFFAREA 0.643500 ;
    PORT
      LAYER met4 ;
        RECT 654.430 53.400 654.730 54.400 ;
    END
  END um_iw[152]
  PIN um_iw[153]
    DIRECTION OUTPUT ;
    USE SIGNAL ;
    ANTENNADIFFAREA 0.643500 ;
    PORT
      LAYER met4 ;
        RECT 651.670 53.400 651.970 54.400 ;
    END
  END um_iw[153]
  PIN um_iw[154]
    DIRECTION OUTPUT ;
    USE SIGNAL ;
    ANTENNADIFFAREA 0.643500 ;
    PORT
      LAYER met4 ;
        RECT 648.910 53.400 649.210 54.400 ;
    END
  END um_iw[154]
  PIN um_iw[155]
    DIRECTION OUTPUT ;
    USE SIGNAL ;
    ANTENNADIFFAREA 0.643500 ;
    PORT
      LAYER met4 ;
        RECT 646.150 53.400 646.450 54.400 ;
    END
  END um_iw[155]
  PIN um_iw[156]
    DIRECTION OUTPUT ;
    USE SIGNAL ;
    ANTENNADIFFAREA 0.643500 ;
    PORT
      LAYER met4 ;
        RECT 643.390 53.400 643.690 54.400 ;
    END
  END um_iw[156]
  PIN um_iw[157]
    DIRECTION OUTPUT ;
    USE SIGNAL ;
    ANTENNADIFFAREA 0.643500 ;
    PORT
      LAYER met4 ;
        RECT 640.630 53.400 640.930 54.400 ;
    END
  END um_iw[157]
  PIN um_iw[158]
    DIRECTION OUTPUT ;
    USE SIGNAL ;
    ANTENNADIFFAREA 0.643500 ;
    PORT
      LAYER met4 ;
        RECT 637.870 53.400 638.170 54.400 ;
    END
  END um_iw[158]
  PIN um_iw[159]
    DIRECTION OUTPUT ;
    USE SIGNAL ;
    ANTENNADIFFAREA 0.643500 ;
    PORT
      LAYER met4 ;
        RECT 635.110 53.400 635.410 54.400 ;
    END
  END um_iw[159]
  PIN um_iw[15]
    DIRECTION OUTPUT ;
    USE SIGNAL ;
    ANTENNADIFFAREA 0.643500 ;
    PORT
      LAYER met4 ;
        RECT 1330.630 53.400 1330.930 54.400 ;
    END
  END um_iw[15]
  PIN um_iw[160]
    DIRECTION OUTPUT ;
    USE SIGNAL ;
    ANTENNADIFFAREA 0.643500 ;
    PORT
      LAYER met4 ;
        RECT 632.350 53.400 632.650 54.400 ;
    END
  END um_iw[160]
  PIN um_iw[161]
    DIRECTION OUTPUT ;
    USE SIGNAL ;
    ANTENNADIFFAREA 0.643500 ;
    PORT
      LAYER met4 ;
        RECT 629.590 53.400 629.890 54.400 ;
    END
  END um_iw[161]
  PIN um_iw[162]
    DIRECTION OUTPUT ;
    USE SIGNAL ;
    ANTENNADIFFAREA 0.643500 ;
    PORT
      LAYER met4 ;
        RECT 676.510 0.000 676.810 1.000 ;
    END
  END um_iw[162]
  PIN um_iw[163]
    DIRECTION OUTPUT ;
    USE SIGNAL ;
    ANTENNADIFFAREA 0.643500 ;
    PORT
      LAYER met4 ;
        RECT 673.750 0.000 674.050 1.000 ;
    END
  END um_iw[163]
  PIN um_iw[164]
    DIRECTION OUTPUT ;
    USE SIGNAL ;
    ANTENNADIFFAREA 0.643500 ;
    PORT
      LAYER met4 ;
        RECT 670.990 0.000 671.290 1.000 ;
    END
  END um_iw[164]
  PIN um_iw[165]
    DIRECTION OUTPUT ;
    USE SIGNAL ;
    ANTENNADIFFAREA 0.643500 ;
    PORT
      LAYER met4 ;
        RECT 668.230 0.000 668.530 1.000 ;
    END
  END um_iw[165]
  PIN um_iw[166]
    DIRECTION OUTPUT ;
    USE SIGNAL ;
    ANTENNADIFFAREA 0.643500 ;
    PORT
      LAYER met4 ;
        RECT 665.470 0.000 665.770 1.000 ;
    END
  END um_iw[166]
  PIN um_iw[167]
    DIRECTION OUTPUT ;
    USE SIGNAL ;
    ANTENNADIFFAREA 0.643500 ;
    PORT
      LAYER met4 ;
        RECT 662.710 0.000 663.010 1.000 ;
    END
  END um_iw[167]
  PIN um_iw[168]
    DIRECTION OUTPUT ;
    USE SIGNAL ;
    ANTENNADIFFAREA 0.643500 ;
    PORT
      LAYER met4 ;
        RECT 659.950 0.000 660.250 1.000 ;
    END
  END um_iw[168]
  PIN um_iw[169]
    DIRECTION OUTPUT ;
    USE SIGNAL ;
    ANTENNADIFFAREA 0.643500 ;
    PORT
      LAYER met4 ;
        RECT 657.190 0.000 657.490 1.000 ;
    END
  END um_iw[169]
  PIN um_iw[16]
    DIRECTION OUTPUT ;
    USE SIGNAL ;
    ANTENNADIFFAREA 0.643500 ;
    PORT
      LAYER met4 ;
        RECT 1327.870 53.400 1328.170 54.400 ;
    END
  END um_iw[16]
  PIN um_iw[170]
    DIRECTION OUTPUT ;
    USE SIGNAL ;
    ANTENNADIFFAREA 0.643500 ;
    PORT
      LAYER met4 ;
        RECT 654.430 0.000 654.730 1.000 ;
    END
  END um_iw[170]
  PIN um_iw[171]
    DIRECTION OUTPUT ;
    USE SIGNAL ;
    ANTENNADIFFAREA 0.643500 ;
    PORT
      LAYER met4 ;
        RECT 651.670 0.000 651.970 1.000 ;
    END
  END um_iw[171]
  PIN um_iw[172]
    DIRECTION OUTPUT ;
    USE SIGNAL ;
    ANTENNADIFFAREA 0.643500 ;
    PORT
      LAYER met4 ;
        RECT 648.910 0.000 649.210 1.000 ;
    END
  END um_iw[172]
  PIN um_iw[173]
    DIRECTION OUTPUT ;
    USE SIGNAL ;
    ANTENNADIFFAREA 0.643500 ;
    PORT
      LAYER met4 ;
        RECT 646.150 0.000 646.450 1.000 ;
    END
  END um_iw[173]
  PIN um_iw[174]
    DIRECTION OUTPUT ;
    USE SIGNAL ;
    ANTENNADIFFAREA 0.643500 ;
    PORT
      LAYER met4 ;
        RECT 643.390 0.000 643.690 1.000 ;
    END
  END um_iw[174]
  PIN um_iw[175]
    DIRECTION OUTPUT ;
    USE SIGNAL ;
    ANTENNADIFFAREA 0.643500 ;
    PORT
      LAYER met4 ;
        RECT 640.630 0.000 640.930 1.000 ;
    END
  END um_iw[175]
  PIN um_iw[176]
    DIRECTION OUTPUT ;
    USE SIGNAL ;
    ANTENNADIFFAREA 0.643500 ;
    PORT
      LAYER met4 ;
        RECT 637.870 0.000 638.170 1.000 ;
    END
  END um_iw[176]
  PIN um_iw[177]
    DIRECTION OUTPUT ;
    USE SIGNAL ;
    ANTENNADIFFAREA 0.643500 ;
    PORT
      LAYER met4 ;
        RECT 635.110 0.000 635.410 1.000 ;
    END
  END um_iw[177]
  PIN um_iw[178]
    DIRECTION OUTPUT ;
    USE SIGNAL ;
    ANTENNADIFFAREA 0.643500 ;
    PORT
      LAYER met4 ;
        RECT 632.350 0.000 632.650 1.000 ;
    END
  END um_iw[178]
  PIN um_iw[179]
    DIRECTION OUTPUT ;
    USE SIGNAL ;
    ANTENNADIFFAREA 0.643500 ;
    PORT
      LAYER met4 ;
        RECT 629.590 0.000 629.890 1.000 ;
    END
  END um_iw[179]
  PIN um_iw[17]
    DIRECTION OUTPUT ;
    USE SIGNAL ;
    ANTENNADIFFAREA 0.643500 ;
    PORT
      LAYER met4 ;
        RECT 1325.110 53.400 1325.410 54.400 ;
    END
  END um_iw[17]
  PIN um_iw[180]
    DIRECTION OUTPUT ;
    USE SIGNAL ;
    ANTENNADIFFAREA 0.643500 ;
    PORT
      LAYER met4 ;
        RECT 502.630 53.400 502.930 54.400 ;
    END
  END um_iw[180]
  PIN um_iw[181]
    DIRECTION OUTPUT ;
    USE SIGNAL ;
    ANTENNADIFFAREA 0.643500 ;
    PORT
      LAYER met4 ;
        RECT 499.870 53.400 500.170 54.400 ;
    END
  END um_iw[181]
  PIN um_iw[182]
    DIRECTION OUTPUT ;
    USE SIGNAL ;
    ANTENNADIFFAREA 0.643500 ;
    PORT
      LAYER met4 ;
        RECT 497.110 53.400 497.410 54.400 ;
    END
  END um_iw[182]
  PIN um_iw[183]
    DIRECTION OUTPUT ;
    USE SIGNAL ;
    ANTENNADIFFAREA 0.643500 ;
    PORT
      LAYER met4 ;
        RECT 494.350 53.400 494.650 54.400 ;
    END
  END um_iw[183]
  PIN um_iw[184]
    DIRECTION OUTPUT ;
    USE SIGNAL ;
    ANTENNADIFFAREA 0.643500 ;
    PORT
      LAYER met4 ;
        RECT 491.590 53.400 491.890 54.400 ;
    END
  END um_iw[184]
  PIN um_iw[185]
    DIRECTION OUTPUT ;
    USE SIGNAL ;
    ANTENNADIFFAREA 0.643500 ;
    PORT
      LAYER met4 ;
        RECT 488.830 53.400 489.130 54.400 ;
    END
  END um_iw[185]
  PIN um_iw[186]
    DIRECTION OUTPUT ;
    USE SIGNAL ;
    ANTENNADIFFAREA 0.643500 ;
    PORT
      LAYER met4 ;
        RECT 486.070 53.400 486.370 54.400 ;
    END
  END um_iw[186]
  PIN um_iw[187]
    DIRECTION OUTPUT ;
    USE SIGNAL ;
    ANTENNADIFFAREA 0.643500 ;
    PORT
      LAYER met4 ;
        RECT 483.310 53.400 483.610 54.400 ;
    END
  END um_iw[187]
  PIN um_iw[188]
    DIRECTION OUTPUT ;
    USE SIGNAL ;
    ANTENNADIFFAREA 0.643500 ;
    PORT
      LAYER met4 ;
        RECT 480.550 53.400 480.850 54.400 ;
    END
  END um_iw[188]
  PIN um_iw[189]
    DIRECTION OUTPUT ;
    USE SIGNAL ;
    ANTENNADIFFAREA 0.643500 ;
    PORT
      LAYER met4 ;
        RECT 477.790 53.400 478.090 54.400 ;
    END
  END um_iw[189]
  PIN um_iw[18]
    DIRECTION OUTPUT ;
    USE SIGNAL ;
    ANTENNADIFFAREA 0.643500 ;
    PORT
      LAYER met4 ;
        RECT 1372.030 0.000 1372.330 1.000 ;
    END
  END um_iw[18]
  PIN um_iw[190]
    DIRECTION OUTPUT ;
    USE SIGNAL ;
    ANTENNADIFFAREA 0.643500 ;
    PORT
      LAYER met4 ;
        RECT 475.030 53.400 475.330 54.400 ;
    END
  END um_iw[190]
  PIN um_iw[191]
    DIRECTION OUTPUT ;
    USE SIGNAL ;
    ANTENNADIFFAREA 0.643500 ;
    PORT
      LAYER met4 ;
        RECT 472.270 53.400 472.570 54.400 ;
    END
  END um_iw[191]
  PIN um_iw[192]
    DIRECTION OUTPUT ;
    USE SIGNAL ;
    ANTENNADIFFAREA 0.643500 ;
    PORT
      LAYER met4 ;
        RECT 469.510 53.400 469.810 54.400 ;
    END
  END um_iw[192]
  PIN um_iw[193]
    DIRECTION OUTPUT ;
    USE SIGNAL ;
    ANTENNADIFFAREA 0.643500 ;
    PORT
      LAYER met4 ;
        RECT 466.750 53.400 467.050 54.400 ;
    END
  END um_iw[193]
  PIN um_iw[194]
    DIRECTION OUTPUT ;
    USE SIGNAL ;
    ANTENNADIFFAREA 0.643500 ;
    PORT
      LAYER met4 ;
        RECT 463.990 53.400 464.290 54.400 ;
    END
  END um_iw[194]
  PIN um_iw[195]
    DIRECTION OUTPUT ;
    USE SIGNAL ;
    ANTENNADIFFAREA 0.643500 ;
    PORT
      LAYER met4 ;
        RECT 461.230 53.400 461.530 54.400 ;
    END
  END um_iw[195]
  PIN um_iw[196]
    DIRECTION OUTPUT ;
    USE SIGNAL ;
    ANTENNADIFFAREA 0.643500 ;
    PORT
      LAYER met4 ;
        RECT 458.470 53.400 458.770 54.400 ;
    END
  END um_iw[196]
  PIN um_iw[197]
    DIRECTION OUTPUT ;
    USE SIGNAL ;
    ANTENNADIFFAREA 0.643500 ;
    PORT
      LAYER met4 ;
        RECT 455.710 53.400 456.010 54.400 ;
    END
  END um_iw[197]
  PIN um_iw[198]
    DIRECTION OUTPUT ;
    USE SIGNAL ;
    ANTENNADIFFAREA 0.643500 ;
    PORT
      LAYER met4 ;
        RECT 502.630 0.000 502.930 1.000 ;
    END
  END um_iw[198]
  PIN um_iw[199]
    DIRECTION OUTPUT ;
    USE SIGNAL ;
    ANTENNADIFFAREA 0.643500 ;
    PORT
      LAYER met4 ;
        RECT 499.870 0.000 500.170 1.000 ;
    END
  END um_iw[199]
  PIN um_iw[19]
    DIRECTION OUTPUT ;
    USE SIGNAL ;
    ANTENNADIFFAREA 0.643500 ;
    PORT
      LAYER met4 ;
        RECT 1369.270 0.000 1369.570 1.000 ;
    END
  END um_iw[19]
  PIN um_iw[1]
    DIRECTION OUTPUT ;
    USE SIGNAL ;
    ANTENNADIFFAREA 0.643500 ;
    PORT
      LAYER met4 ;
        RECT 1369.270 53.400 1369.570 54.400 ;
    END
  END um_iw[1]
  PIN um_iw[200]
    DIRECTION OUTPUT ;
    USE SIGNAL ;
    ANTENNADIFFAREA 0.643500 ;
    PORT
      LAYER met4 ;
        RECT 497.110 0.000 497.410 1.000 ;
    END
  END um_iw[200]
  PIN um_iw[201]
    DIRECTION OUTPUT ;
    USE SIGNAL ;
    ANTENNADIFFAREA 0.643500 ;
    PORT
      LAYER met4 ;
        RECT 494.350 0.000 494.650 1.000 ;
    END
  END um_iw[201]
  PIN um_iw[202]
    DIRECTION OUTPUT ;
    USE SIGNAL ;
    ANTENNADIFFAREA 0.643500 ;
    PORT
      LAYER met4 ;
        RECT 491.590 0.000 491.890 1.000 ;
    END
  END um_iw[202]
  PIN um_iw[203]
    DIRECTION OUTPUT ;
    USE SIGNAL ;
    ANTENNADIFFAREA 0.643500 ;
    PORT
      LAYER met4 ;
        RECT 488.830 0.000 489.130 1.000 ;
    END
  END um_iw[203]
  PIN um_iw[204]
    DIRECTION OUTPUT ;
    USE SIGNAL ;
    ANTENNADIFFAREA 0.643500 ;
    PORT
      LAYER met4 ;
        RECT 486.070 0.000 486.370 1.000 ;
    END
  END um_iw[204]
  PIN um_iw[205]
    DIRECTION OUTPUT ;
    USE SIGNAL ;
    ANTENNADIFFAREA 0.643500 ;
    PORT
      LAYER met4 ;
        RECT 483.310 0.000 483.610 1.000 ;
    END
  END um_iw[205]
  PIN um_iw[206]
    DIRECTION OUTPUT ;
    USE SIGNAL ;
    ANTENNADIFFAREA 0.643500 ;
    PORT
      LAYER met4 ;
        RECT 480.550 0.000 480.850 1.000 ;
    END
  END um_iw[206]
  PIN um_iw[207]
    DIRECTION OUTPUT ;
    USE SIGNAL ;
    ANTENNADIFFAREA 0.643500 ;
    PORT
      LAYER met4 ;
        RECT 477.790 0.000 478.090 1.000 ;
    END
  END um_iw[207]
  PIN um_iw[208]
    DIRECTION OUTPUT ;
    USE SIGNAL ;
    ANTENNADIFFAREA 0.643500 ;
    PORT
      LAYER met4 ;
        RECT 475.030 0.000 475.330 1.000 ;
    END
  END um_iw[208]
  PIN um_iw[209]
    DIRECTION OUTPUT ;
    USE SIGNAL ;
    ANTENNADIFFAREA 0.643500 ;
    PORT
      LAYER met4 ;
        RECT 472.270 0.000 472.570 1.000 ;
    END
  END um_iw[209]
  PIN um_iw[20]
    DIRECTION OUTPUT ;
    USE SIGNAL ;
    ANTENNADIFFAREA 0.643500 ;
    PORT
      LAYER met4 ;
        RECT 1366.510 0.000 1366.810 1.000 ;
    END
  END um_iw[20]
  PIN um_iw[210]
    DIRECTION OUTPUT ;
    USE SIGNAL ;
    ANTENNADIFFAREA 0.643500 ;
    PORT
      LAYER met4 ;
        RECT 469.510 0.000 469.810 1.000 ;
    END
  END um_iw[210]
  PIN um_iw[211]
    DIRECTION OUTPUT ;
    USE SIGNAL ;
    ANTENNADIFFAREA 0.643500 ;
    PORT
      LAYER met4 ;
        RECT 466.750 0.000 467.050 1.000 ;
    END
  END um_iw[211]
  PIN um_iw[212]
    DIRECTION OUTPUT ;
    USE SIGNAL ;
    ANTENNADIFFAREA 0.643500 ;
    PORT
      LAYER met4 ;
        RECT 463.990 0.000 464.290 1.000 ;
    END
  END um_iw[212]
  PIN um_iw[213]
    DIRECTION OUTPUT ;
    USE SIGNAL ;
    ANTENNADIFFAREA 0.643500 ;
    PORT
      LAYER met4 ;
        RECT 461.230 0.000 461.530 1.000 ;
    END
  END um_iw[213]
  PIN um_iw[214]
    DIRECTION OUTPUT ;
    USE SIGNAL ;
    ANTENNADIFFAREA 0.643500 ;
    PORT
      LAYER met4 ;
        RECT 458.470 0.000 458.770 1.000 ;
    END
  END um_iw[214]
  PIN um_iw[215]
    DIRECTION OUTPUT ;
    USE SIGNAL ;
    ANTENNADIFFAREA 0.643500 ;
    PORT
      LAYER met4 ;
        RECT 455.710 0.000 456.010 1.000 ;
    END
  END um_iw[215]
  PIN um_iw[216]
    DIRECTION OUTPUT ;
    USE SIGNAL ;
    ANTENNADIFFAREA 0.643500 ;
    PORT
      LAYER met4 ;
        RECT 328.750 53.400 329.050 54.400 ;
    END
  END um_iw[216]
  PIN um_iw[217]
    DIRECTION OUTPUT ;
    USE SIGNAL ;
    ANTENNADIFFAREA 0.643500 ;
    PORT
      LAYER met4 ;
        RECT 325.990 53.400 326.290 54.400 ;
    END
  END um_iw[217]
  PIN um_iw[218]
    DIRECTION OUTPUT ;
    USE SIGNAL ;
    ANTENNADIFFAREA 0.643500 ;
    PORT
      LAYER met4 ;
        RECT 323.230 53.400 323.530 54.400 ;
    END
  END um_iw[218]
  PIN um_iw[219]
    DIRECTION OUTPUT ;
    USE SIGNAL ;
    ANTENNADIFFAREA 0.643500 ;
    PORT
      LAYER met4 ;
        RECT 320.470 53.400 320.770 54.400 ;
    END
  END um_iw[219]
  PIN um_iw[21]
    DIRECTION OUTPUT ;
    USE SIGNAL ;
    ANTENNADIFFAREA 0.643500 ;
    PORT
      LAYER met4 ;
        RECT 1363.750 0.000 1364.050 1.000 ;
    END
  END um_iw[21]
  PIN um_iw[220]
    DIRECTION OUTPUT ;
    USE SIGNAL ;
    ANTENNADIFFAREA 0.643500 ;
    PORT
      LAYER met4 ;
        RECT 317.710 53.400 318.010 54.400 ;
    END
  END um_iw[220]
  PIN um_iw[221]
    DIRECTION OUTPUT ;
    USE SIGNAL ;
    ANTENNADIFFAREA 0.643500 ;
    PORT
      LAYER met4 ;
        RECT 314.950 53.400 315.250 54.400 ;
    END
  END um_iw[221]
  PIN um_iw[222]
    DIRECTION OUTPUT ;
    USE SIGNAL ;
    ANTENNADIFFAREA 0.643500 ;
    PORT
      LAYER met4 ;
        RECT 312.190 53.400 312.490 54.400 ;
    END
  END um_iw[222]
  PIN um_iw[223]
    DIRECTION OUTPUT ;
    USE SIGNAL ;
    ANTENNADIFFAREA 0.643500 ;
    PORT
      LAYER met4 ;
        RECT 309.430 53.400 309.730 54.400 ;
    END
  END um_iw[223]
  PIN um_iw[224]
    DIRECTION OUTPUT ;
    USE SIGNAL ;
    ANTENNADIFFAREA 0.643500 ;
    PORT
      LAYER met4 ;
        RECT 306.670 53.400 306.970 54.400 ;
    END
  END um_iw[224]
  PIN um_iw[225]
    DIRECTION OUTPUT ;
    USE SIGNAL ;
    ANTENNADIFFAREA 0.643500 ;
    PORT
      LAYER met4 ;
        RECT 303.910 53.400 304.210 54.400 ;
    END
  END um_iw[225]
  PIN um_iw[226]
    DIRECTION OUTPUT ;
    USE SIGNAL ;
    ANTENNADIFFAREA 0.643500 ;
    PORT
      LAYER met4 ;
        RECT 301.150 53.400 301.450 54.400 ;
    END
  END um_iw[226]
  PIN um_iw[227]
    DIRECTION OUTPUT ;
    USE SIGNAL ;
    ANTENNADIFFAREA 0.643500 ;
    PORT
      LAYER met4 ;
        RECT 298.390 53.400 298.690 54.400 ;
    END
  END um_iw[227]
  PIN um_iw[228]
    DIRECTION OUTPUT ;
    USE SIGNAL ;
    ANTENNADIFFAREA 0.643500 ;
    PORT
      LAYER met4 ;
        RECT 295.630 53.400 295.930 54.400 ;
    END
  END um_iw[228]
  PIN um_iw[229]
    DIRECTION OUTPUT ;
    USE SIGNAL ;
    ANTENNADIFFAREA 0.643500 ;
    PORT
      LAYER met4 ;
        RECT 292.870 53.400 293.170 54.400 ;
    END
  END um_iw[229]
  PIN um_iw[22]
    DIRECTION OUTPUT ;
    USE SIGNAL ;
    ANTENNADIFFAREA 0.643500 ;
    PORT
      LAYER met4 ;
        RECT 1360.990 0.000 1361.290 1.000 ;
    END
  END um_iw[22]
  PIN um_iw[230]
    DIRECTION OUTPUT ;
    USE SIGNAL ;
    ANTENNADIFFAREA 0.643500 ;
    PORT
      LAYER met4 ;
        RECT 290.110 53.400 290.410 54.400 ;
    END
  END um_iw[230]
  PIN um_iw[231]
    DIRECTION OUTPUT ;
    USE SIGNAL ;
    ANTENNADIFFAREA 0.643500 ;
    PORT
      LAYER met4 ;
        RECT 287.350 53.400 287.650 54.400 ;
    END
  END um_iw[231]
  PIN um_iw[232]
    DIRECTION OUTPUT ;
    USE SIGNAL ;
    ANTENNADIFFAREA 0.643500 ;
    PORT
      LAYER met4 ;
        RECT 284.590 53.400 284.890 54.400 ;
    END
  END um_iw[232]
  PIN um_iw[233]
    DIRECTION OUTPUT ;
    USE SIGNAL ;
    ANTENNADIFFAREA 0.643500 ;
    PORT
      LAYER met4 ;
        RECT 281.830 53.400 282.130 54.400 ;
    END
  END um_iw[233]
  PIN um_iw[234]
    DIRECTION OUTPUT ;
    USE SIGNAL ;
    ANTENNADIFFAREA 0.643500 ;
    PORT
      LAYER met4 ;
        RECT 328.750 0.000 329.050 1.000 ;
    END
  END um_iw[234]
  PIN um_iw[235]
    DIRECTION OUTPUT ;
    USE SIGNAL ;
    ANTENNADIFFAREA 0.643500 ;
    PORT
      LAYER met4 ;
        RECT 325.990 0.000 326.290 1.000 ;
    END
  END um_iw[235]
  PIN um_iw[236]
    DIRECTION OUTPUT ;
    USE SIGNAL ;
    ANTENNADIFFAREA 0.643500 ;
    PORT
      LAYER met4 ;
        RECT 323.230 0.000 323.530 1.000 ;
    END
  END um_iw[236]
  PIN um_iw[237]
    DIRECTION OUTPUT ;
    USE SIGNAL ;
    ANTENNADIFFAREA 0.643500 ;
    PORT
      LAYER met4 ;
        RECT 320.470 0.000 320.770 1.000 ;
    END
  END um_iw[237]
  PIN um_iw[238]
    DIRECTION OUTPUT ;
    USE SIGNAL ;
    ANTENNADIFFAREA 0.643500 ;
    PORT
      LAYER met4 ;
        RECT 317.710 0.000 318.010 1.000 ;
    END
  END um_iw[238]
  PIN um_iw[239]
    DIRECTION OUTPUT ;
    USE SIGNAL ;
    ANTENNADIFFAREA 0.643500 ;
    PORT
      LAYER met4 ;
        RECT 314.950 0.000 315.250 1.000 ;
    END
  END um_iw[239]
  PIN um_iw[23]
    DIRECTION OUTPUT ;
    USE SIGNAL ;
    ANTENNADIFFAREA 0.643500 ;
    PORT
      LAYER met4 ;
        RECT 1358.230 0.000 1358.530 1.000 ;
    END
  END um_iw[23]
  PIN um_iw[240]
    DIRECTION OUTPUT ;
    USE SIGNAL ;
    ANTENNADIFFAREA 0.643500 ;
    PORT
      LAYER met4 ;
        RECT 312.190 0.000 312.490 1.000 ;
    END
  END um_iw[240]
  PIN um_iw[241]
    DIRECTION OUTPUT ;
    USE SIGNAL ;
    ANTENNADIFFAREA 0.643500 ;
    PORT
      LAYER met4 ;
        RECT 309.430 0.000 309.730 1.000 ;
    END
  END um_iw[241]
  PIN um_iw[242]
    DIRECTION OUTPUT ;
    USE SIGNAL ;
    ANTENNADIFFAREA 0.643500 ;
    PORT
      LAYER met4 ;
        RECT 306.670 0.000 306.970 1.000 ;
    END
  END um_iw[242]
  PIN um_iw[243]
    DIRECTION OUTPUT ;
    USE SIGNAL ;
    ANTENNADIFFAREA 0.643500 ;
    PORT
      LAYER met4 ;
        RECT 303.910 0.000 304.210 1.000 ;
    END
  END um_iw[243]
  PIN um_iw[244]
    DIRECTION OUTPUT ;
    USE SIGNAL ;
    ANTENNADIFFAREA 0.643500 ;
    PORT
      LAYER met4 ;
        RECT 301.150 0.000 301.450 1.000 ;
    END
  END um_iw[244]
  PIN um_iw[245]
    DIRECTION OUTPUT ;
    USE SIGNAL ;
    ANTENNADIFFAREA 0.643500 ;
    PORT
      LAYER met4 ;
        RECT 298.390 0.000 298.690 1.000 ;
    END
  END um_iw[245]
  PIN um_iw[246]
    DIRECTION OUTPUT ;
    USE SIGNAL ;
    ANTENNADIFFAREA 0.643500 ;
    PORT
      LAYER met4 ;
        RECT 295.630 0.000 295.930 1.000 ;
    END
  END um_iw[246]
  PIN um_iw[247]
    DIRECTION OUTPUT ;
    USE SIGNAL ;
    ANTENNADIFFAREA 0.643500 ;
    PORT
      LAYER met4 ;
        RECT 292.870 0.000 293.170 1.000 ;
    END
  END um_iw[247]
  PIN um_iw[248]
    DIRECTION OUTPUT ;
    USE SIGNAL ;
    ANTENNADIFFAREA 0.643500 ;
    PORT
      LAYER met4 ;
        RECT 290.110 0.000 290.410 1.000 ;
    END
  END um_iw[248]
  PIN um_iw[249]
    DIRECTION OUTPUT ;
    USE SIGNAL ;
    ANTENNADIFFAREA 0.643500 ;
    PORT
      LAYER met4 ;
        RECT 287.350 0.000 287.650 1.000 ;
    END
  END um_iw[249]
  PIN um_iw[24]
    DIRECTION OUTPUT ;
    USE SIGNAL ;
    ANTENNADIFFAREA 0.643500 ;
    PORT
      LAYER met4 ;
        RECT 1355.470 0.000 1355.770 1.000 ;
    END
  END um_iw[24]
  PIN um_iw[250]
    DIRECTION OUTPUT ;
    USE SIGNAL ;
    ANTENNADIFFAREA 0.643500 ;
    PORT
      LAYER met4 ;
        RECT 284.590 0.000 284.890 1.000 ;
    END
  END um_iw[250]
  PIN um_iw[251]
    DIRECTION OUTPUT ;
    USE SIGNAL ;
    ANTENNADIFFAREA 0.643500 ;
    PORT
      LAYER met4 ;
        RECT 281.830 0.000 282.130 1.000 ;
    END
  END um_iw[251]
  PIN um_iw[252]
    DIRECTION OUTPUT ;
    USE SIGNAL ;
    ANTENNADIFFAREA 0.643500 ;
    PORT
      LAYER met4 ;
        RECT 154.870 53.400 155.170 54.400 ;
    END
  END um_iw[252]
  PIN um_iw[253]
    DIRECTION OUTPUT ;
    USE SIGNAL ;
    ANTENNADIFFAREA 0.643500 ;
    PORT
      LAYER met4 ;
        RECT 152.110 53.400 152.410 54.400 ;
    END
  END um_iw[253]
  PIN um_iw[254]
    DIRECTION OUTPUT ;
    USE SIGNAL ;
    ANTENNADIFFAREA 0.643500 ;
    PORT
      LAYER met4 ;
        RECT 149.350 53.400 149.650 54.400 ;
    END
  END um_iw[254]
  PIN um_iw[255]
    DIRECTION OUTPUT ;
    USE SIGNAL ;
    ANTENNADIFFAREA 0.643500 ;
    PORT
      LAYER met4 ;
        RECT 146.590 53.400 146.890 54.400 ;
    END
  END um_iw[255]
  PIN um_iw[256]
    DIRECTION OUTPUT ;
    USE SIGNAL ;
    ANTENNADIFFAREA 0.643500 ;
    PORT
      LAYER met4 ;
        RECT 143.830 53.400 144.130 54.400 ;
    END
  END um_iw[256]
  PIN um_iw[257]
    DIRECTION OUTPUT ;
    USE SIGNAL ;
    ANTENNADIFFAREA 0.643500 ;
    PORT
      LAYER met4 ;
        RECT 141.070 53.400 141.370 54.400 ;
    END
  END um_iw[257]
  PIN um_iw[258]
    DIRECTION OUTPUT ;
    USE SIGNAL ;
    ANTENNADIFFAREA 0.643500 ;
    PORT
      LAYER met4 ;
        RECT 138.310 53.400 138.610 54.400 ;
    END
  END um_iw[258]
  PIN um_iw[259]
    DIRECTION OUTPUT ;
    USE SIGNAL ;
    ANTENNADIFFAREA 0.643500 ;
    PORT
      LAYER met4 ;
        RECT 135.550 53.400 135.850 54.400 ;
    END
  END um_iw[259]
  PIN um_iw[25]
    DIRECTION OUTPUT ;
    USE SIGNAL ;
    ANTENNADIFFAREA 0.643500 ;
    PORT
      LAYER met4 ;
        RECT 1352.710 0.000 1353.010 1.000 ;
    END
  END um_iw[25]
  PIN um_iw[260]
    DIRECTION OUTPUT ;
    USE SIGNAL ;
    ANTENNADIFFAREA 0.643500 ;
    PORT
      LAYER met4 ;
        RECT 132.790 53.400 133.090 54.400 ;
    END
  END um_iw[260]
  PIN um_iw[261]
    DIRECTION OUTPUT ;
    USE SIGNAL ;
    ANTENNADIFFAREA 0.643500 ;
    PORT
      LAYER met4 ;
        RECT 130.030 53.400 130.330 54.400 ;
    END
  END um_iw[261]
  PIN um_iw[262]
    DIRECTION OUTPUT ;
    USE SIGNAL ;
    ANTENNADIFFAREA 0.643500 ;
    PORT
      LAYER met4 ;
        RECT 127.270 53.400 127.570 54.400 ;
    END
  END um_iw[262]
  PIN um_iw[263]
    DIRECTION OUTPUT ;
    USE SIGNAL ;
    ANTENNADIFFAREA 0.643500 ;
    PORT
      LAYER met4 ;
        RECT 124.510 53.400 124.810 54.400 ;
    END
  END um_iw[263]
  PIN um_iw[264]
    DIRECTION OUTPUT ;
    USE SIGNAL ;
    ANTENNADIFFAREA 0.643500 ;
    PORT
      LAYER met4 ;
        RECT 121.750 53.400 122.050 54.400 ;
    END
  END um_iw[264]
  PIN um_iw[265]
    DIRECTION OUTPUT ;
    USE SIGNAL ;
    ANTENNADIFFAREA 0.643500 ;
    PORT
      LAYER met4 ;
        RECT 118.990 53.400 119.290 54.400 ;
    END
  END um_iw[265]
  PIN um_iw[266]
    DIRECTION OUTPUT ;
    USE SIGNAL ;
    ANTENNADIFFAREA 0.643500 ;
    PORT
      LAYER met4 ;
        RECT 116.230 53.400 116.530 54.400 ;
    END
  END um_iw[266]
  PIN um_iw[267]
    DIRECTION OUTPUT ;
    USE SIGNAL ;
    ANTENNADIFFAREA 0.643500 ;
    PORT
      LAYER met4 ;
        RECT 113.470 53.400 113.770 54.400 ;
    END
  END um_iw[267]
  PIN um_iw[268]
    DIRECTION OUTPUT ;
    USE SIGNAL ;
    ANTENNADIFFAREA 0.643500 ;
    PORT
      LAYER met4 ;
        RECT 110.710 53.400 111.010 54.400 ;
    END
  END um_iw[268]
  PIN um_iw[269]
    DIRECTION OUTPUT ;
    USE SIGNAL ;
    ANTENNADIFFAREA 0.643500 ;
    PORT
      LAYER met4 ;
        RECT 107.950 53.400 108.250 54.400 ;
    END
  END um_iw[269]
  PIN um_iw[26]
    DIRECTION OUTPUT ;
    USE SIGNAL ;
    ANTENNADIFFAREA 0.643500 ;
    PORT
      LAYER met4 ;
        RECT 1349.950 0.000 1350.250 1.000 ;
    END
  END um_iw[26]
  PIN um_iw[270]
    DIRECTION OUTPUT ;
    USE SIGNAL ;
    ANTENNADIFFAREA 0.643500 ;
    PORT
      LAYER met4 ;
        RECT 154.870 0.000 155.170 1.000 ;
    END
  END um_iw[270]
  PIN um_iw[271]
    DIRECTION OUTPUT ;
    USE SIGNAL ;
    ANTENNADIFFAREA 0.643500 ;
    PORT
      LAYER met4 ;
        RECT 152.110 0.000 152.410 1.000 ;
    END
  END um_iw[271]
  PIN um_iw[272]
    DIRECTION OUTPUT ;
    USE SIGNAL ;
    ANTENNADIFFAREA 0.643500 ;
    PORT
      LAYER met4 ;
        RECT 149.350 0.000 149.650 1.000 ;
    END
  END um_iw[272]
  PIN um_iw[273]
    DIRECTION OUTPUT ;
    USE SIGNAL ;
    ANTENNADIFFAREA 0.643500 ;
    PORT
      LAYER met4 ;
        RECT 146.590 0.000 146.890 1.000 ;
    END
  END um_iw[273]
  PIN um_iw[274]
    DIRECTION OUTPUT ;
    USE SIGNAL ;
    ANTENNADIFFAREA 0.643500 ;
    PORT
      LAYER met4 ;
        RECT 143.830 0.000 144.130 1.000 ;
    END
  END um_iw[274]
  PIN um_iw[275]
    DIRECTION OUTPUT ;
    USE SIGNAL ;
    ANTENNADIFFAREA 0.643500 ;
    PORT
      LAYER met4 ;
        RECT 141.070 0.000 141.370 1.000 ;
    END
  END um_iw[275]
  PIN um_iw[276]
    DIRECTION OUTPUT ;
    USE SIGNAL ;
    ANTENNADIFFAREA 0.643500 ;
    PORT
      LAYER met4 ;
        RECT 138.310 0.000 138.610 1.000 ;
    END
  END um_iw[276]
  PIN um_iw[277]
    DIRECTION OUTPUT ;
    USE SIGNAL ;
    ANTENNADIFFAREA 0.643500 ;
    PORT
      LAYER met4 ;
        RECT 135.550 0.000 135.850 1.000 ;
    END
  END um_iw[277]
  PIN um_iw[278]
    DIRECTION OUTPUT ;
    USE SIGNAL ;
    ANTENNADIFFAREA 0.643500 ;
    PORT
      LAYER met4 ;
        RECT 132.790 0.000 133.090 1.000 ;
    END
  END um_iw[278]
  PIN um_iw[279]
    DIRECTION OUTPUT ;
    USE SIGNAL ;
    ANTENNADIFFAREA 0.643500 ;
    PORT
      LAYER met4 ;
        RECT 130.030 0.000 130.330 1.000 ;
    END
  END um_iw[279]
  PIN um_iw[27]
    DIRECTION OUTPUT ;
    USE SIGNAL ;
    ANTENNADIFFAREA 0.643500 ;
    PORT
      LAYER met4 ;
        RECT 1347.190 0.000 1347.490 1.000 ;
    END
  END um_iw[27]
  PIN um_iw[280]
    DIRECTION OUTPUT ;
    USE SIGNAL ;
    ANTENNADIFFAREA 0.643500 ;
    PORT
      LAYER met4 ;
        RECT 127.270 0.000 127.570 1.000 ;
    END
  END um_iw[280]
  PIN um_iw[281]
    DIRECTION OUTPUT ;
    USE SIGNAL ;
    ANTENNADIFFAREA 0.643500 ;
    PORT
      LAYER met4 ;
        RECT 124.510 0.000 124.810 1.000 ;
    END
  END um_iw[281]
  PIN um_iw[282]
    DIRECTION OUTPUT ;
    USE SIGNAL ;
    ANTENNADIFFAREA 0.643500 ;
    PORT
      LAYER met4 ;
        RECT 121.750 0.000 122.050 1.000 ;
    END
  END um_iw[282]
  PIN um_iw[283]
    DIRECTION OUTPUT ;
    USE SIGNAL ;
    ANTENNADIFFAREA 0.643500 ;
    PORT
      LAYER met4 ;
        RECT 118.990 0.000 119.290 1.000 ;
    END
  END um_iw[283]
  PIN um_iw[284]
    DIRECTION OUTPUT ;
    USE SIGNAL ;
    ANTENNADIFFAREA 0.643500 ;
    PORT
      LAYER met4 ;
        RECT 116.230 0.000 116.530 1.000 ;
    END
  END um_iw[284]
  PIN um_iw[285]
    DIRECTION OUTPUT ;
    USE SIGNAL ;
    ANTENNADIFFAREA 0.643500 ;
    PORT
      LAYER met4 ;
        RECT 113.470 0.000 113.770 1.000 ;
    END
  END um_iw[285]
  PIN um_iw[286]
    DIRECTION OUTPUT ;
    USE SIGNAL ;
    ANTENNADIFFAREA 0.643500 ;
    PORT
      LAYER met4 ;
        RECT 110.710 0.000 111.010 1.000 ;
    END
  END um_iw[286]
  PIN um_iw[287]
    DIRECTION OUTPUT ;
    USE SIGNAL ;
    ANTENNADIFFAREA 0.643500 ;
    PORT
      LAYER met4 ;
        RECT 107.950 0.000 108.250 1.000 ;
    END
  END um_iw[287]
  PIN um_iw[28]
    DIRECTION OUTPUT ;
    USE SIGNAL ;
    ANTENNADIFFAREA 0.643500 ;
    PORT
      LAYER met4 ;
        RECT 1344.430 0.000 1344.730 1.000 ;
    END
  END um_iw[28]
  PIN um_iw[29]
    DIRECTION OUTPUT ;
    USE SIGNAL ;
    ANTENNADIFFAREA 0.643500 ;
    PORT
      LAYER met4 ;
        RECT 1341.670 0.000 1341.970 1.000 ;
    END
  END um_iw[29]
  PIN um_iw[2]
    DIRECTION OUTPUT ;
    USE SIGNAL ;
    ANTENNADIFFAREA 0.643500 ;
    PORT
      LAYER met4 ;
        RECT 1366.510 53.400 1366.810 54.400 ;
    END
  END um_iw[2]
  PIN um_iw[30]
    DIRECTION OUTPUT ;
    USE SIGNAL ;
    ANTENNADIFFAREA 0.643500 ;
    PORT
      LAYER met4 ;
        RECT 1338.910 0.000 1339.210 1.000 ;
    END
  END um_iw[30]
  PIN um_iw[31]
    DIRECTION OUTPUT ;
    USE SIGNAL ;
    ANTENNADIFFAREA 0.643500 ;
    PORT
      LAYER met4 ;
        RECT 1336.150 0.000 1336.450 1.000 ;
    END
  END um_iw[31]
  PIN um_iw[32]
    DIRECTION OUTPUT ;
    USE SIGNAL ;
    ANTENNADIFFAREA 0.643500 ;
    PORT
      LAYER met4 ;
        RECT 1333.390 0.000 1333.690 1.000 ;
    END
  END um_iw[32]
  PIN um_iw[33]
    DIRECTION OUTPUT ;
    USE SIGNAL ;
    ANTENNADIFFAREA 0.643500 ;
    PORT
      LAYER met4 ;
        RECT 1330.630 0.000 1330.930 1.000 ;
    END
  END um_iw[33]
  PIN um_iw[34]
    DIRECTION OUTPUT ;
    USE SIGNAL ;
    ANTENNADIFFAREA 0.643500 ;
    PORT
      LAYER met4 ;
        RECT 1327.870 0.000 1328.170 1.000 ;
    END
  END um_iw[34]
  PIN um_iw[35]
    DIRECTION OUTPUT ;
    USE SIGNAL ;
    ANTENNADIFFAREA 0.643500 ;
    PORT
      LAYER met4 ;
        RECT 1325.110 0.000 1325.410 1.000 ;
    END
  END um_iw[35]
  PIN um_iw[36]
    DIRECTION OUTPUT ;
    USE SIGNAL ;
    ANTENNADIFFAREA 0.643500 ;
    PORT
      LAYER met4 ;
        RECT 1198.150 53.400 1198.450 54.400 ;
    END
  END um_iw[36]
  PIN um_iw[37]
    DIRECTION OUTPUT ;
    USE SIGNAL ;
    ANTENNADIFFAREA 0.643500 ;
    PORT
      LAYER met4 ;
        RECT 1195.390 53.400 1195.690 54.400 ;
    END
  END um_iw[37]
  PIN um_iw[38]
    DIRECTION OUTPUT ;
    USE SIGNAL ;
    ANTENNADIFFAREA 0.643500 ;
    PORT
      LAYER met4 ;
        RECT 1192.630 53.400 1192.930 54.400 ;
    END
  END um_iw[38]
  PIN um_iw[39]
    DIRECTION OUTPUT ;
    USE SIGNAL ;
    ANTENNADIFFAREA 0.643500 ;
    PORT
      LAYER met4 ;
        RECT 1189.870 53.400 1190.170 54.400 ;
    END
  END um_iw[39]
  PIN um_iw[3]
    DIRECTION OUTPUT ;
    USE SIGNAL ;
    ANTENNADIFFAREA 0.643500 ;
    PORT
      LAYER met4 ;
        RECT 1363.750 53.400 1364.050 54.400 ;
    END
  END um_iw[3]
  PIN um_iw[40]
    DIRECTION OUTPUT ;
    USE SIGNAL ;
    ANTENNADIFFAREA 0.643500 ;
    PORT
      LAYER met4 ;
        RECT 1187.110 53.400 1187.410 54.400 ;
    END
  END um_iw[40]
  PIN um_iw[41]
    DIRECTION OUTPUT ;
    USE SIGNAL ;
    ANTENNADIFFAREA 0.643500 ;
    PORT
      LAYER met4 ;
        RECT 1184.350 53.400 1184.650 54.400 ;
    END
  END um_iw[41]
  PIN um_iw[42]
    DIRECTION OUTPUT ;
    USE SIGNAL ;
    ANTENNADIFFAREA 0.643500 ;
    PORT
      LAYER met4 ;
        RECT 1181.590 53.400 1181.890 54.400 ;
    END
  END um_iw[42]
  PIN um_iw[43]
    DIRECTION OUTPUT ;
    USE SIGNAL ;
    ANTENNADIFFAREA 0.643500 ;
    PORT
      LAYER met4 ;
        RECT 1178.830 53.400 1179.130 54.400 ;
    END
  END um_iw[43]
  PIN um_iw[44]
    DIRECTION OUTPUT ;
    USE SIGNAL ;
    ANTENNADIFFAREA 0.643500 ;
    PORT
      LAYER met4 ;
        RECT 1176.070 53.400 1176.370 54.400 ;
    END
  END um_iw[44]
  PIN um_iw[45]
    DIRECTION OUTPUT ;
    USE SIGNAL ;
    ANTENNADIFFAREA 0.643500 ;
    PORT
      LAYER met4 ;
        RECT 1173.310 53.400 1173.610 54.400 ;
    END
  END um_iw[45]
  PIN um_iw[46]
    DIRECTION OUTPUT ;
    USE SIGNAL ;
    ANTENNADIFFAREA 0.643500 ;
    PORT
      LAYER met4 ;
        RECT 1170.550 53.400 1170.850 54.400 ;
    END
  END um_iw[46]
  PIN um_iw[47]
    DIRECTION OUTPUT ;
    USE SIGNAL ;
    ANTENNADIFFAREA 0.643500 ;
    PORT
      LAYER met4 ;
        RECT 1167.790 53.400 1168.090 54.400 ;
    END
  END um_iw[47]
  PIN um_iw[48]
    DIRECTION OUTPUT ;
    USE SIGNAL ;
    ANTENNADIFFAREA 0.643500 ;
    PORT
      LAYER met4 ;
        RECT 1165.030 53.400 1165.330 54.400 ;
    END
  END um_iw[48]
  PIN um_iw[49]
    DIRECTION OUTPUT ;
    USE SIGNAL ;
    ANTENNADIFFAREA 0.643500 ;
    PORT
      LAYER met4 ;
        RECT 1162.270 53.400 1162.570 54.400 ;
    END
  END um_iw[49]
  PIN um_iw[4]
    DIRECTION OUTPUT ;
    USE SIGNAL ;
    ANTENNADIFFAREA 0.643500 ;
    PORT
      LAYER met4 ;
        RECT 1360.990 53.400 1361.290 54.400 ;
    END
  END um_iw[4]
  PIN um_iw[50]
    DIRECTION OUTPUT ;
    USE SIGNAL ;
    ANTENNADIFFAREA 0.643500 ;
    PORT
      LAYER met4 ;
        RECT 1159.510 53.400 1159.810 54.400 ;
    END
  END um_iw[50]
  PIN um_iw[51]
    DIRECTION OUTPUT ;
    USE SIGNAL ;
    ANTENNADIFFAREA 0.643500 ;
    PORT
      LAYER met4 ;
        RECT 1156.750 53.400 1157.050 54.400 ;
    END
  END um_iw[51]
  PIN um_iw[52]
    DIRECTION OUTPUT ;
    USE SIGNAL ;
    ANTENNADIFFAREA 0.643500 ;
    PORT
      LAYER met4 ;
        RECT 1153.990 53.400 1154.290 54.400 ;
    END
  END um_iw[52]
  PIN um_iw[53]
    DIRECTION OUTPUT ;
    USE SIGNAL ;
    ANTENNADIFFAREA 0.643500 ;
    PORT
      LAYER met4 ;
        RECT 1151.230 53.400 1151.530 54.400 ;
    END
  END um_iw[53]
  PIN um_iw[54]
    DIRECTION OUTPUT ;
    USE SIGNAL ;
    ANTENNADIFFAREA 0.643500 ;
    PORT
      LAYER met4 ;
        RECT 1198.150 0.000 1198.450 1.000 ;
    END
  END um_iw[54]
  PIN um_iw[55]
    DIRECTION OUTPUT ;
    USE SIGNAL ;
    ANTENNADIFFAREA 0.643500 ;
    PORT
      LAYER met4 ;
        RECT 1195.390 0.000 1195.690 1.000 ;
    END
  END um_iw[55]
  PIN um_iw[56]
    DIRECTION OUTPUT ;
    USE SIGNAL ;
    ANTENNADIFFAREA 0.643500 ;
    PORT
      LAYER met4 ;
        RECT 1192.630 0.000 1192.930 1.000 ;
    END
  END um_iw[56]
  PIN um_iw[57]
    DIRECTION OUTPUT ;
    USE SIGNAL ;
    ANTENNADIFFAREA 0.643500 ;
    PORT
      LAYER met4 ;
        RECT 1189.870 0.000 1190.170 1.000 ;
    END
  END um_iw[57]
  PIN um_iw[58]
    DIRECTION OUTPUT ;
    USE SIGNAL ;
    ANTENNADIFFAREA 0.643500 ;
    PORT
      LAYER met4 ;
        RECT 1187.110 0.000 1187.410 1.000 ;
    END
  END um_iw[58]
  PIN um_iw[59]
    DIRECTION OUTPUT ;
    USE SIGNAL ;
    ANTENNADIFFAREA 0.643500 ;
    PORT
      LAYER met4 ;
        RECT 1184.350 0.000 1184.650 1.000 ;
    END
  END um_iw[59]
  PIN um_iw[5]
    DIRECTION OUTPUT ;
    USE SIGNAL ;
    ANTENNADIFFAREA 0.643500 ;
    PORT
      LAYER met4 ;
        RECT 1358.230 53.400 1358.530 54.400 ;
    END
  END um_iw[5]
  PIN um_iw[60]
    DIRECTION OUTPUT ;
    USE SIGNAL ;
    ANTENNADIFFAREA 0.643500 ;
    PORT
      LAYER met4 ;
        RECT 1181.590 0.000 1181.890 1.000 ;
    END
  END um_iw[60]
  PIN um_iw[61]
    DIRECTION OUTPUT ;
    USE SIGNAL ;
    ANTENNADIFFAREA 0.643500 ;
    PORT
      LAYER met4 ;
        RECT 1178.830 0.000 1179.130 1.000 ;
    END
  END um_iw[61]
  PIN um_iw[62]
    DIRECTION OUTPUT ;
    USE SIGNAL ;
    ANTENNADIFFAREA 0.643500 ;
    PORT
      LAYER met4 ;
        RECT 1176.070 0.000 1176.370 1.000 ;
    END
  END um_iw[62]
  PIN um_iw[63]
    DIRECTION OUTPUT ;
    USE SIGNAL ;
    ANTENNADIFFAREA 0.643500 ;
    PORT
      LAYER met4 ;
        RECT 1173.310 0.000 1173.610 1.000 ;
    END
  END um_iw[63]
  PIN um_iw[64]
    DIRECTION OUTPUT ;
    USE SIGNAL ;
    ANTENNADIFFAREA 0.643500 ;
    PORT
      LAYER met4 ;
        RECT 1170.550 0.000 1170.850 1.000 ;
    END
  END um_iw[64]
  PIN um_iw[65]
    DIRECTION OUTPUT ;
    USE SIGNAL ;
    ANTENNADIFFAREA 0.643500 ;
    PORT
      LAYER met4 ;
        RECT 1167.790 0.000 1168.090 1.000 ;
    END
  END um_iw[65]
  PIN um_iw[66]
    DIRECTION OUTPUT ;
    USE SIGNAL ;
    ANTENNADIFFAREA 0.643500 ;
    PORT
      LAYER met4 ;
        RECT 1165.030 0.000 1165.330 1.000 ;
    END
  END um_iw[66]
  PIN um_iw[67]
    DIRECTION OUTPUT ;
    USE SIGNAL ;
    ANTENNADIFFAREA 0.643500 ;
    PORT
      LAYER met4 ;
        RECT 1162.270 0.000 1162.570 1.000 ;
    END
  END um_iw[67]
  PIN um_iw[68]
    DIRECTION OUTPUT ;
    USE SIGNAL ;
    ANTENNADIFFAREA 0.643500 ;
    PORT
      LAYER met4 ;
        RECT 1159.510 0.000 1159.810 1.000 ;
    END
  END um_iw[68]
  PIN um_iw[69]
    DIRECTION OUTPUT ;
    USE SIGNAL ;
    ANTENNADIFFAREA 0.643500 ;
    PORT
      LAYER met4 ;
        RECT 1156.750 0.000 1157.050 1.000 ;
    END
  END um_iw[69]
  PIN um_iw[6]
    DIRECTION OUTPUT ;
    USE SIGNAL ;
    ANTENNADIFFAREA 0.643500 ;
    PORT
      LAYER met4 ;
        RECT 1355.470 53.400 1355.770 54.400 ;
    END
  END um_iw[6]
  PIN um_iw[70]
    DIRECTION OUTPUT ;
    USE SIGNAL ;
    ANTENNADIFFAREA 0.643500 ;
    PORT
      LAYER met4 ;
        RECT 1153.990 0.000 1154.290 1.000 ;
    END
  END um_iw[70]
  PIN um_iw[71]
    DIRECTION OUTPUT ;
    USE SIGNAL ;
    ANTENNADIFFAREA 0.643500 ;
    PORT
      LAYER met4 ;
        RECT 1151.230 0.000 1151.530 1.000 ;
    END
  END um_iw[71]
  PIN um_iw[72]
    DIRECTION OUTPUT ;
    USE SIGNAL ;
    ANTENNADIFFAREA 0.643500 ;
    PORT
      LAYER met4 ;
        RECT 1024.270 53.400 1024.570 54.400 ;
    END
  END um_iw[72]
  PIN um_iw[73]
    DIRECTION OUTPUT ;
    USE SIGNAL ;
    ANTENNADIFFAREA 0.643500 ;
    PORT
      LAYER met4 ;
        RECT 1021.510 53.400 1021.810 54.400 ;
    END
  END um_iw[73]
  PIN um_iw[74]
    DIRECTION OUTPUT ;
    USE SIGNAL ;
    ANTENNADIFFAREA 0.643500 ;
    PORT
      LAYER met4 ;
        RECT 1018.750 53.400 1019.050 54.400 ;
    END
  END um_iw[74]
  PIN um_iw[75]
    DIRECTION OUTPUT ;
    USE SIGNAL ;
    ANTENNADIFFAREA 0.643500 ;
    PORT
      LAYER met4 ;
        RECT 1015.990 53.400 1016.290 54.400 ;
    END
  END um_iw[75]
  PIN um_iw[76]
    DIRECTION OUTPUT ;
    USE SIGNAL ;
    ANTENNADIFFAREA 0.643500 ;
    PORT
      LAYER met4 ;
        RECT 1013.230 53.400 1013.530 54.400 ;
    END
  END um_iw[76]
  PIN um_iw[77]
    DIRECTION OUTPUT ;
    USE SIGNAL ;
    ANTENNADIFFAREA 0.643500 ;
    PORT
      LAYER met4 ;
        RECT 1010.470 53.400 1010.770 54.400 ;
    END
  END um_iw[77]
  PIN um_iw[78]
    DIRECTION OUTPUT ;
    USE SIGNAL ;
    ANTENNADIFFAREA 0.643500 ;
    PORT
      LAYER met4 ;
        RECT 1007.710 53.400 1008.010 54.400 ;
    END
  END um_iw[78]
  PIN um_iw[79]
    DIRECTION OUTPUT ;
    USE SIGNAL ;
    ANTENNADIFFAREA 0.643500 ;
    PORT
      LAYER met4 ;
        RECT 1004.950 53.400 1005.250 54.400 ;
    END
  END um_iw[79]
  PIN um_iw[7]
    DIRECTION OUTPUT ;
    USE SIGNAL ;
    ANTENNADIFFAREA 0.643500 ;
    PORT
      LAYER met4 ;
        RECT 1352.710 53.400 1353.010 54.400 ;
    END
  END um_iw[7]
  PIN um_iw[80]
    DIRECTION OUTPUT ;
    USE SIGNAL ;
    ANTENNADIFFAREA 0.643500 ;
    PORT
      LAYER met4 ;
        RECT 1002.190 53.400 1002.490 54.400 ;
    END
  END um_iw[80]
  PIN um_iw[81]
    DIRECTION OUTPUT ;
    USE SIGNAL ;
    ANTENNADIFFAREA 0.643500 ;
    PORT
      LAYER met4 ;
        RECT 999.430 53.400 999.730 54.400 ;
    END
  END um_iw[81]
  PIN um_iw[82]
    DIRECTION OUTPUT ;
    USE SIGNAL ;
    ANTENNADIFFAREA 0.643500 ;
    PORT
      LAYER met4 ;
        RECT 996.670 53.400 996.970 54.400 ;
    END
  END um_iw[82]
  PIN um_iw[83]
    DIRECTION OUTPUT ;
    USE SIGNAL ;
    ANTENNADIFFAREA 0.643500 ;
    PORT
      LAYER met4 ;
        RECT 993.910 53.400 994.210 54.400 ;
    END
  END um_iw[83]
  PIN um_iw[84]
    DIRECTION OUTPUT ;
    USE SIGNAL ;
    ANTENNADIFFAREA 0.643500 ;
    PORT
      LAYER met4 ;
        RECT 991.150 53.400 991.450 54.400 ;
    END
  END um_iw[84]
  PIN um_iw[85]
    DIRECTION OUTPUT ;
    USE SIGNAL ;
    ANTENNADIFFAREA 0.643500 ;
    PORT
      LAYER met4 ;
        RECT 988.390 53.400 988.690 54.400 ;
    END
  END um_iw[85]
  PIN um_iw[86]
    DIRECTION OUTPUT ;
    USE SIGNAL ;
    ANTENNADIFFAREA 0.643500 ;
    PORT
      LAYER met4 ;
        RECT 985.630 53.400 985.930 54.400 ;
    END
  END um_iw[86]
  PIN um_iw[87]
    DIRECTION OUTPUT ;
    USE SIGNAL ;
    ANTENNADIFFAREA 0.643500 ;
    PORT
      LAYER met4 ;
        RECT 982.870 53.400 983.170 54.400 ;
    END
  END um_iw[87]
  PIN um_iw[88]
    DIRECTION OUTPUT ;
    USE SIGNAL ;
    ANTENNADIFFAREA 0.643500 ;
    PORT
      LAYER met4 ;
        RECT 980.110 53.400 980.410 54.400 ;
    END
  END um_iw[88]
  PIN um_iw[89]
    DIRECTION OUTPUT ;
    USE SIGNAL ;
    ANTENNADIFFAREA 0.643500 ;
    PORT
      LAYER met4 ;
        RECT 977.350 53.400 977.650 54.400 ;
    END
  END um_iw[89]
  PIN um_iw[8]
    DIRECTION OUTPUT ;
    USE SIGNAL ;
    ANTENNADIFFAREA 0.643500 ;
    PORT
      LAYER met4 ;
        RECT 1349.950 53.400 1350.250 54.400 ;
    END
  END um_iw[8]
  PIN um_iw[90]
    DIRECTION OUTPUT ;
    USE SIGNAL ;
    ANTENNADIFFAREA 0.643500 ;
    PORT
      LAYER met4 ;
        RECT 1024.270 0.000 1024.570 1.000 ;
    END
  END um_iw[90]
  PIN um_iw[91]
    DIRECTION OUTPUT ;
    USE SIGNAL ;
    ANTENNADIFFAREA 0.643500 ;
    PORT
      LAYER met4 ;
        RECT 1021.510 0.000 1021.810 1.000 ;
    END
  END um_iw[91]
  PIN um_iw[92]
    DIRECTION OUTPUT ;
    USE SIGNAL ;
    ANTENNADIFFAREA 0.643500 ;
    PORT
      LAYER met4 ;
        RECT 1018.750 0.000 1019.050 1.000 ;
    END
  END um_iw[92]
  PIN um_iw[93]
    DIRECTION OUTPUT ;
    USE SIGNAL ;
    ANTENNADIFFAREA 0.643500 ;
    PORT
      LAYER met4 ;
        RECT 1015.990 0.000 1016.290 1.000 ;
    END
  END um_iw[93]
  PIN um_iw[94]
    DIRECTION OUTPUT ;
    USE SIGNAL ;
    ANTENNADIFFAREA 0.643500 ;
    PORT
      LAYER met4 ;
        RECT 1013.230 0.000 1013.530 1.000 ;
    END
  END um_iw[94]
  PIN um_iw[95]
    DIRECTION OUTPUT ;
    USE SIGNAL ;
    ANTENNADIFFAREA 0.643500 ;
    PORT
      LAYER met4 ;
        RECT 1010.470 0.000 1010.770 1.000 ;
    END
  END um_iw[95]
  PIN um_iw[96]
    DIRECTION OUTPUT ;
    USE SIGNAL ;
    ANTENNADIFFAREA 0.643500 ;
    PORT
      LAYER met4 ;
        RECT 1007.710 0.000 1008.010 1.000 ;
    END
  END um_iw[96]
  PIN um_iw[97]
    DIRECTION OUTPUT ;
    USE SIGNAL ;
    ANTENNADIFFAREA 0.643500 ;
    PORT
      LAYER met4 ;
        RECT 1004.950 0.000 1005.250 1.000 ;
    END
  END um_iw[97]
  PIN um_iw[98]
    DIRECTION OUTPUT ;
    USE SIGNAL ;
    ANTENNADIFFAREA 0.643500 ;
    PORT
      LAYER met4 ;
        RECT 1002.190 0.000 1002.490 1.000 ;
    END
  END um_iw[98]
  PIN um_iw[99]
    DIRECTION OUTPUT ;
    USE SIGNAL ;
    ANTENNADIFFAREA 0.643500 ;
    PORT
      LAYER met4 ;
        RECT 999.430 0.000 999.730 1.000 ;
    END
  END um_iw[99]
  PIN um_iw[9]
    DIRECTION OUTPUT ;
    USE SIGNAL ;
    ANTENNADIFFAREA 0.643500 ;
    PORT
      LAYER met4 ;
        RECT 1347.190 53.400 1347.490 54.400 ;
    END
  END um_iw[9]
  PIN um_k_zero[0]
    DIRECTION OUTPUT ;
    USE SIGNAL ;
    PORT
      LAYER met4 ;
        RECT 1256.110 53.400 1256.410 54.400 ;
    END
  END um_k_zero[0]
  PIN um_k_zero[10]
    DIRECTION OUTPUT ;
    USE SIGNAL ;
    PORT
      LAYER met4 ;
        RECT 386.710 53.400 387.010 54.400 ;
    END
  END um_k_zero[10]
  PIN um_k_zero[11]
    DIRECTION OUTPUT ;
    USE SIGNAL ;
    PORT
      LAYER met4 ;
        RECT 386.710 0.000 387.010 1.000 ;
    END
  END um_k_zero[11]
  PIN um_k_zero[12]
    DIRECTION OUTPUT ;
    USE SIGNAL ;
    PORT
      LAYER met4 ;
        RECT 212.830 53.400 213.130 54.400 ;
    END
  END um_k_zero[12]
  PIN um_k_zero[13]
    DIRECTION OUTPUT ;
    USE SIGNAL ;
    PORT
      LAYER met4 ;
        RECT 212.830 0.000 213.130 1.000 ;
    END
  END um_k_zero[13]
  PIN um_k_zero[14]
    DIRECTION OUTPUT ;
    USE SIGNAL ;
    PORT
      LAYER met4 ;
        RECT 38.950 53.400 39.250 54.400 ;
    END
  END um_k_zero[14]
  PIN um_k_zero[15]
    DIRECTION OUTPUT ;
    USE SIGNAL ;
    PORT
      LAYER met4 ;
        RECT 38.950 0.000 39.250 1.000 ;
    END
  END um_k_zero[15]
  PIN um_k_zero[1]
    DIRECTION OUTPUT ;
    USE SIGNAL ;
    PORT
      LAYER met4 ;
        RECT 1256.110 0.000 1256.410 1.000 ;
    END
  END um_k_zero[1]
  PIN um_k_zero[2]
    DIRECTION OUTPUT ;
    USE SIGNAL ;
    PORT
      LAYER met4 ;
        RECT 1082.230 53.400 1082.530 54.400 ;
    END
  END um_k_zero[2]
  PIN um_k_zero[3]
    DIRECTION OUTPUT ;
    USE SIGNAL ;
    PORT
      LAYER met4 ;
        RECT 1082.230 0.000 1082.530 1.000 ;
    END
  END um_k_zero[3]
  PIN um_k_zero[4]
    DIRECTION OUTPUT ;
    USE SIGNAL ;
    PORT
      LAYER met4 ;
        RECT 908.350 53.400 908.650 54.400 ;
    END
  END um_k_zero[4]
  PIN um_k_zero[5]
    DIRECTION OUTPUT ;
    USE SIGNAL ;
    PORT
      LAYER met4 ;
        RECT 908.350 0.000 908.650 1.000 ;
    END
  END um_k_zero[5]
  PIN um_k_zero[6]
    DIRECTION OUTPUT ;
    USE SIGNAL ;
    PORT
      LAYER met4 ;
        RECT 734.470 53.400 734.770 54.400 ;
    END
  END um_k_zero[6]
  PIN um_k_zero[7]
    DIRECTION OUTPUT ;
    USE SIGNAL ;
    PORT
      LAYER met4 ;
        RECT 734.470 0.000 734.770 1.000 ;
    END
  END um_k_zero[7]
  PIN um_k_zero[8]
    DIRECTION OUTPUT ;
    USE SIGNAL ;
    PORT
      LAYER met4 ;
        RECT 560.590 53.400 560.890 54.400 ;
    END
  END um_k_zero[8]
  PIN um_k_zero[9]
    DIRECTION OUTPUT ;
    USE SIGNAL ;
    PORT
      LAYER met4 ;
        RECT 560.590 0.000 560.890 1.000 ;
    END
  END um_k_zero[9]
  PIN um_ow[0]
    DIRECTION INPUT ;
    USE SIGNAL ;
    ANTENNAGATEAREA 0.593700 ;
    ANTENNADIFFAREA 0.434700 ;
    PORT
      LAYER met4 ;
        RECT 1322.350 53.400 1322.650 54.400 ;
    END
  END um_ow[0]
  PIN um_ow[100]
    DIRECTION INPUT ;
    USE SIGNAL ;
    ANTENNAGATEAREA 0.593700 ;
    ANTENNADIFFAREA 0.434700 ;
    PORT
      LAYER met4 ;
        RECT 963.550 53.400 963.850 54.400 ;
    END
  END um_ow[100]
  PIN um_ow[101]
    DIRECTION INPUT ;
    USE SIGNAL ;
    ANTENNAGATEAREA 0.593700 ;
    ANTENNADIFFAREA 0.434700 ;
    PORT
      LAYER met4 ;
        RECT 960.790 53.400 961.090 54.400 ;
    END
  END um_ow[101]
  PIN um_ow[102]
    DIRECTION INPUT ;
    USE SIGNAL ;
    ANTENNAGATEAREA 0.593700 ;
    ANTENNADIFFAREA 0.434700 ;
    PORT
      LAYER met4 ;
        RECT 958.030 53.400 958.330 54.400 ;
    END
  END um_ow[102]
  PIN um_ow[103]
    DIRECTION INPUT ;
    USE SIGNAL ;
    ANTENNAGATEAREA 0.593700 ;
    ANTENNADIFFAREA 0.434700 ;
    PORT
      LAYER met4 ;
        RECT 955.270 53.400 955.570 54.400 ;
    END
  END um_ow[103]
  PIN um_ow[104]
    DIRECTION INPUT ;
    USE SIGNAL ;
    ANTENNAGATEAREA 0.593700 ;
    ANTENNADIFFAREA 0.434700 ;
    PORT
      LAYER met4 ;
        RECT 952.510 53.400 952.810 54.400 ;
    END
  END um_ow[104]
  PIN um_ow[105]
    DIRECTION INPUT ;
    USE SIGNAL ;
    ANTENNAGATEAREA 0.593700 ;
    ANTENNADIFFAREA 0.434700 ;
    PORT
      LAYER met4 ;
        RECT 949.750 53.400 950.050 54.400 ;
    END
  END um_ow[105]
  PIN um_ow[106]
    DIRECTION INPUT ;
    USE SIGNAL ;
    ANTENNAGATEAREA 0.593700 ;
    ANTENNADIFFAREA 0.434700 ;
    PORT
      LAYER met4 ;
        RECT 946.990 53.400 947.290 54.400 ;
    END
  END um_ow[106]
  PIN um_ow[107]
    DIRECTION INPUT ;
    USE SIGNAL ;
    ANTENNAGATEAREA 0.593700 ;
    ANTENNADIFFAREA 0.434700 ;
    PORT
      LAYER met4 ;
        RECT 944.230 53.400 944.530 54.400 ;
    END
  END um_ow[107]
  PIN um_ow[108]
    DIRECTION INPUT ;
    USE SIGNAL ;
    ANTENNAGATEAREA 0.593700 ;
    ANTENNADIFFAREA 0.434700 ;
    PORT
      LAYER met4 ;
        RECT 941.470 53.400 941.770 54.400 ;
    END
  END um_ow[108]
  PIN um_ow[109]
    DIRECTION INPUT ;
    USE SIGNAL ;
    ANTENNAGATEAREA 0.593700 ;
    ANTENNADIFFAREA 0.434700 ;
    PORT
      LAYER met4 ;
        RECT 938.710 53.400 939.010 54.400 ;
    END
  END um_ow[109]
  PIN um_ow[10]
    DIRECTION INPUT ;
    USE SIGNAL ;
    ANTENNAGATEAREA 0.593700 ;
    ANTENNADIFFAREA 0.434700 ;
    PORT
      LAYER met4 ;
        RECT 1294.750 53.400 1295.050 54.400 ;
    END
  END um_ow[10]
  PIN um_ow[110]
    DIRECTION INPUT ;
    USE SIGNAL ;
    ANTENNAGATEAREA 0.593700 ;
    ANTENNADIFFAREA 0.434700 ;
    PORT
      LAYER met4 ;
        RECT 935.950 53.400 936.250 54.400 ;
    END
  END um_ow[110]
  PIN um_ow[111]
    DIRECTION INPUT ;
    USE SIGNAL ;
    ANTENNAGATEAREA 0.593700 ;
    ANTENNADIFFAREA 0.434700 ;
    PORT
      LAYER met4 ;
        RECT 933.190 53.400 933.490 54.400 ;
    END
  END um_ow[111]
  PIN um_ow[112]
    DIRECTION INPUT ;
    USE SIGNAL ;
    ANTENNAGATEAREA 0.593700 ;
    ANTENNADIFFAREA 0.434700 ;
    PORT
      LAYER met4 ;
        RECT 930.430 53.400 930.730 54.400 ;
    END
  END um_ow[112]
  PIN um_ow[113]
    DIRECTION INPUT ;
    USE SIGNAL ;
    ANTENNAGATEAREA 0.593700 ;
    ANTENNADIFFAREA 0.434700 ;
    PORT
      LAYER met4 ;
        RECT 927.670 53.400 927.970 54.400 ;
    END
  END um_ow[113]
  PIN um_ow[114]
    DIRECTION INPUT ;
    USE SIGNAL ;
    ANTENNAGATEAREA 0.593700 ;
    ANTENNADIFFAREA 0.434700 ;
    PORT
      LAYER met4 ;
        RECT 924.910 53.400 925.210 54.400 ;
    END
  END um_ow[114]
  PIN um_ow[115]
    DIRECTION INPUT ;
    USE SIGNAL ;
    ANTENNAGATEAREA 0.593700 ;
    ANTENNADIFFAREA 0.434700 ;
    PORT
      LAYER met4 ;
        RECT 922.150 53.400 922.450 54.400 ;
    END
  END um_ow[115]
  PIN um_ow[116]
    DIRECTION INPUT ;
    USE SIGNAL ;
    ANTENNAGATEAREA 0.593700 ;
    ANTENNADIFFAREA 0.434700 ;
    PORT
      LAYER met4 ;
        RECT 919.390 53.400 919.690 54.400 ;
    END
  END um_ow[116]
  PIN um_ow[117]
    DIRECTION INPUT ;
    USE SIGNAL ;
    ANTENNAGATEAREA 0.593700 ;
    ANTENNADIFFAREA 0.434700 ;
    PORT
      LAYER met4 ;
        RECT 916.630 53.400 916.930 54.400 ;
    END
  END um_ow[117]
  PIN um_ow[118]
    DIRECTION INPUT ;
    USE SIGNAL ;
    ANTENNAGATEAREA 0.593700 ;
    ANTENNADIFFAREA 0.434700 ;
    PORT
      LAYER met4 ;
        RECT 913.870 53.400 914.170 54.400 ;
    END
  END um_ow[118]
  PIN um_ow[119]
    DIRECTION INPUT ;
    USE SIGNAL ;
    ANTENNAGATEAREA 0.593700 ;
    ANTENNADIFFAREA 0.434700 ;
    PORT
      LAYER met4 ;
        RECT 911.110 53.400 911.410 54.400 ;
    END
  END um_ow[119]
  PIN um_ow[11]
    DIRECTION INPUT ;
    USE SIGNAL ;
    ANTENNAGATEAREA 0.593700 ;
    ANTENNADIFFAREA 0.434700 ;
    PORT
      LAYER met4 ;
        RECT 1291.990 53.400 1292.290 54.400 ;
    END
  END um_ow[11]
  PIN um_ow[120]
    DIRECTION INPUT ;
    USE SIGNAL ;
    ANTENNAGATEAREA 0.593700 ;
    ANTENNADIFFAREA 0.434700 ;
    PORT
      LAYER met4 ;
        RECT 974.590 0.000 974.890 1.000 ;
    END
  END um_ow[120]
  PIN um_ow[121]
    DIRECTION INPUT ;
    USE SIGNAL ;
    ANTENNAGATEAREA 0.593700 ;
    ANTENNADIFFAREA 0.434700 ;
    PORT
      LAYER met4 ;
        RECT 971.830 0.000 972.130 1.000 ;
    END
  END um_ow[121]
  PIN um_ow[122]
    DIRECTION INPUT ;
    USE SIGNAL ;
    ANTENNAGATEAREA 0.593700 ;
    ANTENNADIFFAREA 0.434700 ;
    PORT
      LAYER met4 ;
        RECT 969.070 0.000 969.370 1.000 ;
    END
  END um_ow[122]
  PIN um_ow[123]
    DIRECTION INPUT ;
    USE SIGNAL ;
    ANTENNAGATEAREA 0.593700 ;
    ANTENNADIFFAREA 0.434700 ;
    PORT
      LAYER met4 ;
        RECT 966.310 0.000 966.610 1.000 ;
    END
  END um_ow[123]
  PIN um_ow[124]
    DIRECTION INPUT ;
    USE SIGNAL ;
    ANTENNAGATEAREA 0.593700 ;
    ANTENNADIFFAREA 0.434700 ;
    PORT
      LAYER met4 ;
        RECT 963.550 0.000 963.850 1.000 ;
    END
  END um_ow[124]
  PIN um_ow[125]
    DIRECTION INPUT ;
    USE SIGNAL ;
    ANTENNAGATEAREA 0.593700 ;
    ANTENNADIFFAREA 0.434700 ;
    PORT
      LAYER met4 ;
        RECT 960.790 0.000 961.090 1.000 ;
    END
  END um_ow[125]
  PIN um_ow[126]
    DIRECTION INPUT ;
    USE SIGNAL ;
    ANTENNAGATEAREA 0.593700 ;
    ANTENNADIFFAREA 0.434700 ;
    PORT
      LAYER met4 ;
        RECT 958.030 0.000 958.330 1.000 ;
    END
  END um_ow[126]
  PIN um_ow[127]
    DIRECTION INPUT ;
    USE SIGNAL ;
    ANTENNAGATEAREA 0.593700 ;
    ANTENNADIFFAREA 0.434700 ;
    PORT
      LAYER met4 ;
        RECT 955.270 0.000 955.570 1.000 ;
    END
  END um_ow[127]
  PIN um_ow[128]
    DIRECTION INPUT ;
    USE SIGNAL ;
    ANTENNAGATEAREA 0.593700 ;
    ANTENNADIFFAREA 0.434700 ;
    PORT
      LAYER met4 ;
        RECT 952.510 0.000 952.810 1.000 ;
    END
  END um_ow[128]
  PIN um_ow[129]
    DIRECTION INPUT ;
    USE SIGNAL ;
    ANTENNAGATEAREA 0.593700 ;
    ANTENNADIFFAREA 0.434700 ;
    PORT
      LAYER met4 ;
        RECT 949.750 0.000 950.050 1.000 ;
    END
  END um_ow[129]
  PIN um_ow[12]
    DIRECTION INPUT ;
    USE SIGNAL ;
    ANTENNAGATEAREA 0.593700 ;
    ANTENNADIFFAREA 0.434700 ;
    PORT
      LAYER met4 ;
        RECT 1289.230 53.400 1289.530 54.400 ;
    END
  END um_ow[12]
  PIN um_ow[130]
    DIRECTION INPUT ;
    USE SIGNAL ;
    ANTENNAGATEAREA 0.593700 ;
    ANTENNADIFFAREA 0.434700 ;
    PORT
      LAYER met4 ;
        RECT 946.990 0.000 947.290 1.000 ;
    END
  END um_ow[130]
  PIN um_ow[131]
    DIRECTION INPUT ;
    USE SIGNAL ;
    ANTENNAGATEAREA 0.593700 ;
    ANTENNADIFFAREA 0.434700 ;
    PORT
      LAYER met4 ;
        RECT 944.230 0.000 944.530 1.000 ;
    END
  END um_ow[131]
  PIN um_ow[132]
    DIRECTION INPUT ;
    USE SIGNAL ;
    ANTENNAGATEAREA 0.593700 ;
    ANTENNADIFFAREA 0.434700 ;
    PORT
      LAYER met4 ;
        RECT 941.470 0.000 941.770 1.000 ;
    END
  END um_ow[132]
  PIN um_ow[133]
    DIRECTION INPUT ;
    USE SIGNAL ;
    ANTENNAGATEAREA 0.593700 ;
    ANTENNADIFFAREA 0.434700 ;
    PORT
      LAYER met4 ;
        RECT 938.710 0.000 939.010 1.000 ;
    END
  END um_ow[133]
  PIN um_ow[134]
    DIRECTION INPUT ;
    USE SIGNAL ;
    ANTENNAGATEAREA 0.593700 ;
    ANTENNADIFFAREA 0.434700 ;
    PORT
      LAYER met4 ;
        RECT 935.950 0.000 936.250 1.000 ;
    END
  END um_ow[134]
  PIN um_ow[135]
    DIRECTION INPUT ;
    USE SIGNAL ;
    ANTENNAGATEAREA 0.593700 ;
    ANTENNADIFFAREA 0.434700 ;
    PORT
      LAYER met4 ;
        RECT 933.190 0.000 933.490 1.000 ;
    END
  END um_ow[135]
  PIN um_ow[136]
    DIRECTION INPUT ;
    USE SIGNAL ;
    ANTENNAGATEAREA 0.593700 ;
    ANTENNADIFFAREA 0.434700 ;
    PORT
      LAYER met4 ;
        RECT 930.430 0.000 930.730 1.000 ;
    END
  END um_ow[136]
  PIN um_ow[137]
    DIRECTION INPUT ;
    USE SIGNAL ;
    ANTENNAGATEAREA 0.593700 ;
    ANTENNADIFFAREA 0.434700 ;
    PORT
      LAYER met4 ;
        RECT 927.670 0.000 927.970 1.000 ;
    END
  END um_ow[137]
  PIN um_ow[138]
    DIRECTION INPUT ;
    USE SIGNAL ;
    ANTENNAGATEAREA 0.593700 ;
    ANTENNADIFFAREA 0.434700 ;
    PORT
      LAYER met4 ;
        RECT 924.910 0.000 925.210 1.000 ;
    END
  END um_ow[138]
  PIN um_ow[139]
    DIRECTION INPUT ;
    USE SIGNAL ;
    ANTENNAGATEAREA 0.593700 ;
    ANTENNADIFFAREA 0.434700 ;
    PORT
      LAYER met4 ;
        RECT 922.150 0.000 922.450 1.000 ;
    END
  END um_ow[139]
  PIN um_ow[13]
    DIRECTION INPUT ;
    USE SIGNAL ;
    ANTENNAGATEAREA 0.593700 ;
    ANTENNADIFFAREA 0.434700 ;
    PORT
      LAYER met4 ;
        RECT 1286.470 53.400 1286.770 54.400 ;
    END
  END um_ow[13]
  PIN um_ow[140]
    DIRECTION INPUT ;
    USE SIGNAL ;
    ANTENNAGATEAREA 0.593700 ;
    ANTENNADIFFAREA 0.434700 ;
    PORT
      LAYER met4 ;
        RECT 919.390 0.000 919.690 1.000 ;
    END
  END um_ow[140]
  PIN um_ow[141]
    DIRECTION INPUT ;
    USE SIGNAL ;
    ANTENNAGATEAREA 0.593700 ;
    ANTENNADIFFAREA 0.434700 ;
    PORT
      LAYER met4 ;
        RECT 916.630 0.000 916.930 1.000 ;
    END
  END um_ow[141]
  PIN um_ow[142]
    DIRECTION INPUT ;
    USE SIGNAL ;
    ANTENNAGATEAREA 0.593700 ;
    ANTENNADIFFAREA 0.434700 ;
    PORT
      LAYER met4 ;
        RECT 913.870 0.000 914.170 1.000 ;
    END
  END um_ow[142]
  PIN um_ow[143]
    DIRECTION INPUT ;
    USE SIGNAL ;
    ANTENNAGATEAREA 0.593700 ;
    ANTENNADIFFAREA 0.434700 ;
    PORT
      LAYER met4 ;
        RECT 911.110 0.000 911.410 1.000 ;
    END
  END um_ow[143]
  PIN um_ow[144]
    DIRECTION INPUT ;
    USE SIGNAL ;
    ANTENNAGATEAREA 0.593700 ;
    ANTENNADIFFAREA 0.434700 ;
    PORT
      LAYER met4 ;
        RECT 800.710 53.400 801.010 54.400 ;
    END
  END um_ow[144]
  PIN um_ow[145]
    DIRECTION INPUT ;
    USE SIGNAL ;
    ANTENNAGATEAREA 0.593700 ;
    ANTENNADIFFAREA 0.434700 ;
    PORT
      LAYER met4 ;
        RECT 797.950 53.400 798.250 54.400 ;
    END
  END um_ow[145]
  PIN um_ow[146]
    DIRECTION INPUT ;
    USE SIGNAL ;
    ANTENNAGATEAREA 0.593700 ;
    ANTENNADIFFAREA 0.434700 ;
    PORT
      LAYER met4 ;
        RECT 795.190 53.400 795.490 54.400 ;
    END
  END um_ow[146]
  PIN um_ow[147]
    DIRECTION INPUT ;
    USE SIGNAL ;
    ANTENNAGATEAREA 0.593700 ;
    ANTENNADIFFAREA 0.434700 ;
    PORT
      LAYER met4 ;
        RECT 792.430 53.400 792.730 54.400 ;
    END
  END um_ow[147]
  PIN um_ow[148]
    DIRECTION INPUT ;
    USE SIGNAL ;
    ANTENNAGATEAREA 0.593700 ;
    ANTENNADIFFAREA 0.434700 ;
    PORT
      LAYER met4 ;
        RECT 789.670 53.400 789.970 54.400 ;
    END
  END um_ow[148]
  PIN um_ow[149]
    DIRECTION INPUT ;
    USE SIGNAL ;
    ANTENNAGATEAREA 0.593700 ;
    ANTENNADIFFAREA 0.434700 ;
    PORT
      LAYER met4 ;
        RECT 786.910 53.400 787.210 54.400 ;
    END
  END um_ow[149]
  PIN um_ow[14]
    DIRECTION INPUT ;
    USE SIGNAL ;
    ANTENNAGATEAREA 0.593700 ;
    ANTENNADIFFAREA 0.434700 ;
    PORT
      LAYER met4 ;
        RECT 1283.710 53.400 1284.010 54.400 ;
    END
  END um_ow[14]
  PIN um_ow[150]
    DIRECTION INPUT ;
    USE SIGNAL ;
    ANTENNAGATEAREA 0.593700 ;
    ANTENNADIFFAREA 0.434700 ;
    PORT
      LAYER met4 ;
        RECT 784.150 53.400 784.450 54.400 ;
    END
  END um_ow[150]
  PIN um_ow[151]
    DIRECTION INPUT ;
    USE SIGNAL ;
    ANTENNAGATEAREA 0.593700 ;
    ANTENNADIFFAREA 0.434700 ;
    PORT
      LAYER met4 ;
        RECT 781.390 53.400 781.690 54.400 ;
    END
  END um_ow[151]
  PIN um_ow[152]
    DIRECTION INPUT ;
    USE SIGNAL ;
    ANTENNAGATEAREA 0.593700 ;
    ANTENNADIFFAREA 0.434700 ;
    PORT
      LAYER met4 ;
        RECT 778.630 53.400 778.930 54.400 ;
    END
  END um_ow[152]
  PIN um_ow[153]
    DIRECTION INPUT ;
    USE SIGNAL ;
    ANTENNAGATEAREA 0.593700 ;
    ANTENNADIFFAREA 0.434700 ;
    PORT
      LAYER met4 ;
        RECT 775.870 53.400 776.170 54.400 ;
    END
  END um_ow[153]
  PIN um_ow[154]
    DIRECTION INPUT ;
    USE SIGNAL ;
    ANTENNAGATEAREA 0.593700 ;
    ANTENNADIFFAREA 0.434700 ;
    PORT
      LAYER met4 ;
        RECT 773.110 53.400 773.410 54.400 ;
    END
  END um_ow[154]
  PIN um_ow[155]
    DIRECTION INPUT ;
    USE SIGNAL ;
    ANTENNAGATEAREA 0.593700 ;
    ANTENNADIFFAREA 0.434700 ;
    PORT
      LAYER met4 ;
        RECT 770.350 53.400 770.650 54.400 ;
    END
  END um_ow[155]
  PIN um_ow[156]
    DIRECTION INPUT ;
    USE SIGNAL ;
    ANTENNAGATEAREA 0.593700 ;
    ANTENNADIFFAREA 0.434700 ;
    PORT
      LAYER met4 ;
        RECT 767.590 53.400 767.890 54.400 ;
    END
  END um_ow[156]
  PIN um_ow[157]
    DIRECTION INPUT ;
    USE SIGNAL ;
    ANTENNAGATEAREA 0.593700 ;
    ANTENNADIFFAREA 0.434700 ;
    PORT
      LAYER met4 ;
        RECT 764.830 53.400 765.130 54.400 ;
    END
  END um_ow[157]
  PIN um_ow[158]
    DIRECTION INPUT ;
    USE SIGNAL ;
    ANTENNAGATEAREA 0.593700 ;
    ANTENNADIFFAREA 0.434700 ;
    PORT
      LAYER met4 ;
        RECT 762.070 53.400 762.370 54.400 ;
    END
  END um_ow[158]
  PIN um_ow[159]
    DIRECTION INPUT ;
    USE SIGNAL ;
    ANTENNAGATEAREA 0.593700 ;
    ANTENNADIFFAREA 0.434700 ;
    PORT
      LAYER met4 ;
        RECT 759.310 53.400 759.610 54.400 ;
    END
  END um_ow[159]
  PIN um_ow[15]
    DIRECTION INPUT ;
    USE SIGNAL ;
    ANTENNAGATEAREA 0.593700 ;
    ANTENNADIFFAREA 0.434700 ;
    PORT
      LAYER met4 ;
        RECT 1280.950 53.400 1281.250 54.400 ;
    END
  END um_ow[15]
  PIN um_ow[160]
    DIRECTION INPUT ;
    USE SIGNAL ;
    ANTENNAGATEAREA 0.593700 ;
    ANTENNADIFFAREA 0.434700 ;
    PORT
      LAYER met4 ;
        RECT 756.550 53.400 756.850 54.400 ;
    END
  END um_ow[160]
  PIN um_ow[161]
    DIRECTION INPUT ;
    USE SIGNAL ;
    ANTENNAGATEAREA 0.593700 ;
    ANTENNADIFFAREA 0.434700 ;
    PORT
      LAYER met4 ;
        RECT 753.790 53.400 754.090 54.400 ;
    END
  END um_ow[161]
  PIN um_ow[162]
    DIRECTION INPUT ;
    USE SIGNAL ;
    ANTENNAGATEAREA 0.593700 ;
    ANTENNADIFFAREA 0.434700 ;
    PORT
      LAYER met4 ;
        RECT 751.030 53.400 751.330 54.400 ;
    END
  END um_ow[162]
  PIN um_ow[163]
    DIRECTION INPUT ;
    USE SIGNAL ;
    ANTENNAGATEAREA 0.593700 ;
    ANTENNADIFFAREA 0.434700 ;
    PORT
      LAYER met4 ;
        RECT 748.270 53.400 748.570 54.400 ;
    END
  END um_ow[163]
  PIN um_ow[164]
    DIRECTION INPUT ;
    USE SIGNAL ;
    ANTENNAGATEAREA 0.593700 ;
    ANTENNADIFFAREA 0.434700 ;
    PORT
      LAYER met4 ;
        RECT 745.510 53.400 745.810 54.400 ;
    END
  END um_ow[164]
  PIN um_ow[165]
    DIRECTION INPUT ;
    USE SIGNAL ;
    ANTENNAGATEAREA 0.593700 ;
    ANTENNADIFFAREA 0.434700 ;
    PORT
      LAYER met4 ;
        RECT 742.750 53.400 743.050 54.400 ;
    END
  END um_ow[165]
  PIN um_ow[166]
    DIRECTION INPUT ;
    USE SIGNAL ;
    ANTENNAGATEAREA 0.593700 ;
    ANTENNADIFFAREA 0.434700 ;
    PORT
      LAYER met4 ;
        RECT 739.990 53.400 740.290 54.400 ;
    END
  END um_ow[166]
  PIN um_ow[167]
    DIRECTION INPUT ;
    USE SIGNAL ;
    ANTENNAGATEAREA 0.593700 ;
    ANTENNADIFFAREA 0.434700 ;
    PORT
      LAYER met4 ;
        RECT 737.230 53.400 737.530 54.400 ;
    END
  END um_ow[167]
  PIN um_ow[168]
    DIRECTION INPUT ;
    USE SIGNAL ;
    ANTENNAGATEAREA 0.593700 ;
    ANTENNADIFFAREA 0.434700 ;
    PORT
      LAYER met4 ;
        RECT 800.710 0.000 801.010 1.000 ;
    END
  END um_ow[168]
  PIN um_ow[169]
    DIRECTION INPUT ;
    USE SIGNAL ;
    ANTENNAGATEAREA 0.593700 ;
    ANTENNADIFFAREA 0.434700 ;
    PORT
      LAYER met4 ;
        RECT 797.950 0.000 798.250 1.000 ;
    END
  END um_ow[169]
  PIN um_ow[16]
    DIRECTION INPUT ;
    USE SIGNAL ;
    ANTENNAGATEAREA 0.593700 ;
    ANTENNADIFFAREA 0.434700 ;
    PORT
      LAYER met4 ;
        RECT 1278.190 53.400 1278.490 54.400 ;
    END
  END um_ow[16]
  PIN um_ow[170]
    DIRECTION INPUT ;
    USE SIGNAL ;
    ANTENNAGATEAREA 0.593700 ;
    ANTENNADIFFAREA 0.434700 ;
    PORT
      LAYER met4 ;
        RECT 795.190 0.000 795.490 1.000 ;
    END
  END um_ow[170]
  PIN um_ow[171]
    DIRECTION INPUT ;
    USE SIGNAL ;
    ANTENNAGATEAREA 0.593700 ;
    ANTENNADIFFAREA 0.434700 ;
    PORT
      LAYER met4 ;
        RECT 792.430 0.000 792.730 1.000 ;
    END
  END um_ow[171]
  PIN um_ow[172]
    DIRECTION INPUT ;
    USE SIGNAL ;
    ANTENNAGATEAREA 0.593700 ;
    ANTENNADIFFAREA 0.434700 ;
    PORT
      LAYER met4 ;
        RECT 789.670 0.000 789.970 1.000 ;
    END
  END um_ow[172]
  PIN um_ow[173]
    DIRECTION INPUT ;
    USE SIGNAL ;
    ANTENNAGATEAREA 0.593700 ;
    ANTENNADIFFAREA 0.434700 ;
    PORT
      LAYER met4 ;
        RECT 786.910 0.000 787.210 1.000 ;
    END
  END um_ow[173]
  PIN um_ow[174]
    DIRECTION INPUT ;
    USE SIGNAL ;
    ANTENNAGATEAREA 0.593700 ;
    ANTENNADIFFAREA 0.434700 ;
    PORT
      LAYER met4 ;
        RECT 784.150 0.000 784.450 1.000 ;
    END
  END um_ow[174]
  PIN um_ow[175]
    DIRECTION INPUT ;
    USE SIGNAL ;
    ANTENNAGATEAREA 0.593700 ;
    ANTENNADIFFAREA 0.434700 ;
    PORT
      LAYER met4 ;
        RECT 781.390 0.000 781.690 1.000 ;
    END
  END um_ow[175]
  PIN um_ow[176]
    DIRECTION INPUT ;
    USE SIGNAL ;
    ANTENNAGATEAREA 0.593700 ;
    ANTENNADIFFAREA 0.434700 ;
    PORT
      LAYER met4 ;
        RECT 778.630 0.000 778.930 1.000 ;
    END
  END um_ow[176]
  PIN um_ow[177]
    DIRECTION INPUT ;
    USE SIGNAL ;
    ANTENNAGATEAREA 0.593700 ;
    ANTENNADIFFAREA 0.434700 ;
    PORT
      LAYER met4 ;
        RECT 775.870 0.000 776.170 1.000 ;
    END
  END um_ow[177]
  PIN um_ow[178]
    DIRECTION INPUT ;
    USE SIGNAL ;
    ANTENNAGATEAREA 0.593700 ;
    ANTENNADIFFAREA 0.434700 ;
    PORT
      LAYER met4 ;
        RECT 773.110 0.000 773.410 1.000 ;
    END
  END um_ow[178]
  PIN um_ow[179]
    DIRECTION INPUT ;
    USE SIGNAL ;
    ANTENNAGATEAREA 0.593700 ;
    ANTENNADIFFAREA 0.434700 ;
    PORT
      LAYER met4 ;
        RECT 770.350 0.000 770.650 1.000 ;
    END
  END um_ow[179]
  PIN um_ow[17]
    DIRECTION INPUT ;
    USE SIGNAL ;
    ANTENNAGATEAREA 0.593700 ;
    ANTENNADIFFAREA 0.434700 ;
    PORT
      LAYER met4 ;
        RECT 1275.430 53.400 1275.730 54.400 ;
    END
  END um_ow[17]
  PIN um_ow[180]
    DIRECTION INPUT ;
    USE SIGNAL ;
    ANTENNAGATEAREA 0.593700 ;
    ANTENNADIFFAREA 0.434700 ;
    PORT
      LAYER met4 ;
        RECT 767.590 0.000 767.890 1.000 ;
    END
  END um_ow[180]
  PIN um_ow[181]
    DIRECTION INPUT ;
    USE SIGNAL ;
    ANTENNAGATEAREA 0.593700 ;
    ANTENNADIFFAREA 0.434700 ;
    PORT
      LAYER met4 ;
        RECT 764.830 0.000 765.130 1.000 ;
    END
  END um_ow[181]
  PIN um_ow[182]
    DIRECTION INPUT ;
    USE SIGNAL ;
    ANTENNAGATEAREA 0.593700 ;
    ANTENNADIFFAREA 0.434700 ;
    PORT
      LAYER met4 ;
        RECT 762.070 0.000 762.370 1.000 ;
    END
  END um_ow[182]
  PIN um_ow[183]
    DIRECTION INPUT ;
    USE SIGNAL ;
    ANTENNAGATEAREA 0.593700 ;
    ANTENNADIFFAREA 0.434700 ;
    PORT
      LAYER met4 ;
        RECT 759.310 0.000 759.610 1.000 ;
    END
  END um_ow[183]
  PIN um_ow[184]
    DIRECTION INPUT ;
    USE SIGNAL ;
    ANTENNAGATEAREA 0.593700 ;
    ANTENNADIFFAREA 0.434700 ;
    PORT
      LAYER met4 ;
        RECT 756.550 0.000 756.850 1.000 ;
    END
  END um_ow[184]
  PIN um_ow[185]
    DIRECTION INPUT ;
    USE SIGNAL ;
    ANTENNAGATEAREA 0.593700 ;
    ANTENNADIFFAREA 0.434700 ;
    PORT
      LAYER met4 ;
        RECT 753.790 0.000 754.090 1.000 ;
    END
  END um_ow[185]
  PIN um_ow[186]
    DIRECTION INPUT ;
    USE SIGNAL ;
    ANTENNAGATEAREA 0.593700 ;
    ANTENNADIFFAREA 0.434700 ;
    PORT
      LAYER met4 ;
        RECT 751.030 0.000 751.330 1.000 ;
    END
  END um_ow[186]
  PIN um_ow[187]
    DIRECTION INPUT ;
    USE SIGNAL ;
    ANTENNAGATEAREA 0.593700 ;
    ANTENNADIFFAREA 0.434700 ;
    PORT
      LAYER met4 ;
        RECT 748.270 0.000 748.570 1.000 ;
    END
  END um_ow[187]
  PIN um_ow[188]
    DIRECTION INPUT ;
    USE SIGNAL ;
    ANTENNAGATEAREA 0.593700 ;
    ANTENNADIFFAREA 0.434700 ;
    PORT
      LAYER met4 ;
        RECT 745.510 0.000 745.810 1.000 ;
    END
  END um_ow[188]
  PIN um_ow[189]
    DIRECTION INPUT ;
    USE SIGNAL ;
    ANTENNAGATEAREA 0.593700 ;
    ANTENNADIFFAREA 0.434700 ;
    PORT
      LAYER met4 ;
        RECT 742.750 0.000 743.050 1.000 ;
    END
  END um_ow[189]
  PIN um_ow[18]
    DIRECTION INPUT ;
    USE SIGNAL ;
    ANTENNAGATEAREA 0.593700 ;
    ANTENNADIFFAREA 0.434700 ;
    PORT
      LAYER met4 ;
        RECT 1272.670 53.400 1272.970 54.400 ;
    END
  END um_ow[18]
  PIN um_ow[190]
    DIRECTION INPUT ;
    USE SIGNAL ;
    ANTENNAGATEAREA 0.593700 ;
    ANTENNADIFFAREA 0.434700 ;
    PORT
      LAYER met4 ;
        RECT 739.990 0.000 740.290 1.000 ;
    END
  END um_ow[190]
  PIN um_ow[191]
    DIRECTION INPUT ;
    USE SIGNAL ;
    ANTENNAGATEAREA 0.593700 ;
    ANTENNADIFFAREA 0.434700 ;
    PORT
      LAYER met4 ;
        RECT 737.230 0.000 737.530 1.000 ;
    END
  END um_ow[191]
  PIN um_ow[192]
    DIRECTION INPUT ;
    USE SIGNAL ;
    ANTENNAGATEAREA 0.593700 ;
    ANTENNADIFFAREA 0.434700 ;
    PORT
      LAYER met4 ;
        RECT 626.830 53.400 627.130 54.400 ;
    END
  END um_ow[192]
  PIN um_ow[193]
    DIRECTION INPUT ;
    USE SIGNAL ;
    ANTENNAGATEAREA 0.593700 ;
    ANTENNADIFFAREA 0.434700 ;
    PORT
      LAYER met4 ;
        RECT 624.070 53.400 624.370 54.400 ;
    END
  END um_ow[193]
  PIN um_ow[194]
    DIRECTION INPUT ;
    USE SIGNAL ;
    ANTENNAGATEAREA 0.593700 ;
    ANTENNADIFFAREA 0.434700 ;
    PORT
      LAYER met4 ;
        RECT 621.310 53.400 621.610 54.400 ;
    END
  END um_ow[194]
  PIN um_ow[195]
    DIRECTION INPUT ;
    USE SIGNAL ;
    ANTENNAGATEAREA 0.593700 ;
    ANTENNADIFFAREA 0.434700 ;
    PORT
      LAYER met4 ;
        RECT 618.550 53.400 618.850 54.400 ;
    END
  END um_ow[195]
  PIN um_ow[196]
    DIRECTION INPUT ;
    USE SIGNAL ;
    ANTENNAGATEAREA 0.593700 ;
    ANTENNADIFFAREA 0.434700 ;
    PORT
      LAYER met4 ;
        RECT 615.790 53.400 616.090 54.400 ;
    END
  END um_ow[196]
  PIN um_ow[197]
    DIRECTION INPUT ;
    USE SIGNAL ;
    ANTENNAGATEAREA 0.593700 ;
    ANTENNADIFFAREA 0.434700 ;
    PORT
      LAYER met4 ;
        RECT 613.030 53.400 613.330 54.400 ;
    END
  END um_ow[197]
  PIN um_ow[198]
    DIRECTION INPUT ;
    USE SIGNAL ;
    ANTENNAGATEAREA 0.593700 ;
    ANTENNADIFFAREA 0.434700 ;
    PORT
      LAYER met4 ;
        RECT 610.270 53.400 610.570 54.400 ;
    END
  END um_ow[198]
  PIN um_ow[199]
    DIRECTION INPUT ;
    USE SIGNAL ;
    ANTENNAGATEAREA 0.593700 ;
    ANTENNADIFFAREA 0.434700 ;
    PORT
      LAYER met4 ;
        RECT 607.510 53.400 607.810 54.400 ;
    END
  END um_ow[199]
  PIN um_ow[19]
    DIRECTION INPUT ;
    USE SIGNAL ;
    ANTENNAGATEAREA 0.593700 ;
    ANTENNADIFFAREA 0.434700 ;
    PORT
      LAYER met4 ;
        RECT 1269.910 53.400 1270.210 54.400 ;
    END
  END um_ow[19]
  PIN um_ow[1]
    DIRECTION INPUT ;
    USE SIGNAL ;
    ANTENNAGATEAREA 0.593700 ;
    ANTENNADIFFAREA 0.434700 ;
    PORT
      LAYER met4 ;
        RECT 1319.590 53.400 1319.890 54.400 ;
    END
  END um_ow[1]
  PIN um_ow[200]
    DIRECTION INPUT ;
    USE SIGNAL ;
    ANTENNAGATEAREA 0.593700 ;
    ANTENNADIFFAREA 0.434700 ;
    PORT
      LAYER met4 ;
        RECT 604.750 53.400 605.050 54.400 ;
    END
  END um_ow[200]
  PIN um_ow[201]
    DIRECTION INPUT ;
    USE SIGNAL ;
    ANTENNAGATEAREA 0.593700 ;
    ANTENNADIFFAREA 0.434700 ;
    PORT
      LAYER met4 ;
        RECT 601.990 53.400 602.290 54.400 ;
    END
  END um_ow[201]
  PIN um_ow[202]
    DIRECTION INPUT ;
    USE SIGNAL ;
    ANTENNAGATEAREA 0.593700 ;
    ANTENNADIFFAREA 0.434700 ;
    PORT
      LAYER met4 ;
        RECT 599.230 53.400 599.530 54.400 ;
    END
  END um_ow[202]
  PIN um_ow[203]
    DIRECTION INPUT ;
    USE SIGNAL ;
    ANTENNAGATEAREA 0.593700 ;
    ANTENNADIFFAREA 0.434700 ;
    PORT
      LAYER met4 ;
        RECT 596.470 53.400 596.770 54.400 ;
    END
  END um_ow[203]
  PIN um_ow[204]
    DIRECTION INPUT ;
    USE SIGNAL ;
    ANTENNAGATEAREA 0.593700 ;
    ANTENNADIFFAREA 0.434700 ;
    PORT
      LAYER met4 ;
        RECT 593.710 53.400 594.010 54.400 ;
    END
  END um_ow[204]
  PIN um_ow[205]
    DIRECTION INPUT ;
    USE SIGNAL ;
    ANTENNAGATEAREA 0.593700 ;
    ANTENNADIFFAREA 0.434700 ;
    PORT
      LAYER met4 ;
        RECT 590.950 53.400 591.250 54.400 ;
    END
  END um_ow[205]
  PIN um_ow[206]
    DIRECTION INPUT ;
    USE SIGNAL ;
    ANTENNAGATEAREA 0.593700 ;
    ANTENNADIFFAREA 0.434700 ;
    PORT
      LAYER met4 ;
        RECT 588.190 53.400 588.490 54.400 ;
    END
  END um_ow[206]
  PIN um_ow[207]
    DIRECTION INPUT ;
    USE SIGNAL ;
    ANTENNAGATEAREA 0.593700 ;
    ANTENNADIFFAREA 0.434700 ;
    PORT
      LAYER met4 ;
        RECT 585.430 53.400 585.730 54.400 ;
    END
  END um_ow[207]
  PIN um_ow[208]
    DIRECTION INPUT ;
    USE SIGNAL ;
    ANTENNAGATEAREA 0.593700 ;
    ANTENNADIFFAREA 0.434700 ;
    PORT
      LAYER met4 ;
        RECT 582.670 53.400 582.970 54.400 ;
    END
  END um_ow[208]
  PIN um_ow[209]
    DIRECTION INPUT ;
    USE SIGNAL ;
    ANTENNAGATEAREA 0.593700 ;
    ANTENNADIFFAREA 0.434700 ;
    PORT
      LAYER met4 ;
        RECT 579.910 53.400 580.210 54.400 ;
    END
  END um_ow[209]
  PIN um_ow[20]
    DIRECTION INPUT ;
    USE SIGNAL ;
    ANTENNAGATEAREA 0.593700 ;
    ANTENNADIFFAREA 0.434700 ;
    PORT
      LAYER met4 ;
        RECT 1267.150 53.400 1267.450 54.400 ;
    END
  END um_ow[20]
  PIN um_ow[210]
    DIRECTION INPUT ;
    USE SIGNAL ;
    ANTENNAGATEAREA 0.593700 ;
    ANTENNADIFFAREA 0.434700 ;
    PORT
      LAYER met4 ;
        RECT 577.150 53.400 577.450 54.400 ;
    END
  END um_ow[210]
  PIN um_ow[211]
    DIRECTION INPUT ;
    USE SIGNAL ;
    ANTENNAGATEAREA 0.593700 ;
    ANTENNADIFFAREA 0.434700 ;
    PORT
      LAYER met4 ;
        RECT 574.390 53.400 574.690 54.400 ;
    END
  END um_ow[211]
  PIN um_ow[212]
    DIRECTION INPUT ;
    USE SIGNAL ;
    ANTENNAGATEAREA 0.593700 ;
    ANTENNADIFFAREA 0.434700 ;
    PORT
      LAYER met4 ;
        RECT 571.630 53.400 571.930 54.400 ;
    END
  END um_ow[212]
  PIN um_ow[213]
    DIRECTION INPUT ;
    USE SIGNAL ;
    ANTENNAGATEAREA 0.593700 ;
    ANTENNADIFFAREA 0.434700 ;
    PORT
      LAYER met4 ;
        RECT 568.870 53.400 569.170 54.400 ;
    END
  END um_ow[213]
  PIN um_ow[214]
    DIRECTION INPUT ;
    USE SIGNAL ;
    ANTENNAGATEAREA 0.593700 ;
    ANTENNADIFFAREA 0.434700 ;
    PORT
      LAYER met4 ;
        RECT 566.110 53.400 566.410 54.400 ;
    END
  END um_ow[214]
  PIN um_ow[215]
    DIRECTION INPUT ;
    USE SIGNAL ;
    ANTENNAGATEAREA 0.593700 ;
    ANTENNADIFFAREA 0.434700 ;
    PORT
      LAYER met4 ;
        RECT 563.350 53.400 563.650 54.400 ;
    END
  END um_ow[215]
  PIN um_ow[216]
    DIRECTION INPUT ;
    USE SIGNAL ;
    ANTENNAGATEAREA 0.593700 ;
    ANTENNADIFFAREA 0.434700 ;
    PORT
      LAYER met4 ;
        RECT 626.830 0.000 627.130 1.000 ;
    END
  END um_ow[216]
  PIN um_ow[217]
    DIRECTION INPUT ;
    USE SIGNAL ;
    ANTENNAGATEAREA 0.593700 ;
    ANTENNADIFFAREA 0.434700 ;
    PORT
      LAYER met4 ;
        RECT 624.070 0.000 624.370 1.000 ;
    END
  END um_ow[217]
  PIN um_ow[218]
    DIRECTION INPUT ;
    USE SIGNAL ;
    ANTENNAGATEAREA 0.593700 ;
    ANTENNADIFFAREA 0.434700 ;
    PORT
      LAYER met4 ;
        RECT 621.310 0.000 621.610 1.000 ;
    END
  END um_ow[218]
  PIN um_ow[219]
    DIRECTION INPUT ;
    USE SIGNAL ;
    ANTENNAGATEAREA 0.593700 ;
    ANTENNADIFFAREA 0.434700 ;
    PORT
      LAYER met4 ;
        RECT 618.550 0.000 618.850 1.000 ;
    END
  END um_ow[219]
  PIN um_ow[21]
    DIRECTION INPUT ;
    USE SIGNAL ;
    ANTENNAGATEAREA 0.593700 ;
    ANTENNADIFFAREA 0.434700 ;
    PORT
      LAYER met4 ;
        RECT 1264.390 53.400 1264.690 54.400 ;
    END
  END um_ow[21]
  PIN um_ow[220]
    DIRECTION INPUT ;
    USE SIGNAL ;
    ANTENNAGATEAREA 0.593700 ;
    ANTENNADIFFAREA 0.434700 ;
    PORT
      LAYER met4 ;
        RECT 615.790 0.000 616.090 1.000 ;
    END
  END um_ow[220]
  PIN um_ow[221]
    DIRECTION INPUT ;
    USE SIGNAL ;
    ANTENNAGATEAREA 0.593700 ;
    ANTENNADIFFAREA 0.434700 ;
    PORT
      LAYER met4 ;
        RECT 613.030 0.000 613.330 1.000 ;
    END
  END um_ow[221]
  PIN um_ow[222]
    DIRECTION INPUT ;
    USE SIGNAL ;
    ANTENNAGATEAREA 0.593700 ;
    ANTENNADIFFAREA 0.434700 ;
    PORT
      LAYER met4 ;
        RECT 610.270 0.000 610.570 1.000 ;
    END
  END um_ow[222]
  PIN um_ow[223]
    DIRECTION INPUT ;
    USE SIGNAL ;
    ANTENNAGATEAREA 0.593700 ;
    ANTENNADIFFAREA 0.434700 ;
    PORT
      LAYER met4 ;
        RECT 607.510 0.000 607.810 1.000 ;
    END
  END um_ow[223]
  PIN um_ow[224]
    DIRECTION INPUT ;
    USE SIGNAL ;
    ANTENNAGATEAREA 0.593700 ;
    ANTENNADIFFAREA 0.434700 ;
    PORT
      LAYER met4 ;
        RECT 604.750 0.000 605.050 1.000 ;
    END
  END um_ow[224]
  PIN um_ow[225]
    DIRECTION INPUT ;
    USE SIGNAL ;
    ANTENNAGATEAREA 0.593700 ;
    ANTENNADIFFAREA 0.434700 ;
    PORT
      LAYER met4 ;
        RECT 601.990 0.000 602.290 1.000 ;
    END
  END um_ow[225]
  PIN um_ow[226]
    DIRECTION INPUT ;
    USE SIGNAL ;
    ANTENNAGATEAREA 0.593700 ;
    ANTENNADIFFAREA 0.434700 ;
    PORT
      LAYER met4 ;
        RECT 599.230 0.000 599.530 1.000 ;
    END
  END um_ow[226]
  PIN um_ow[227]
    DIRECTION INPUT ;
    USE SIGNAL ;
    ANTENNAGATEAREA 0.593700 ;
    ANTENNADIFFAREA 0.434700 ;
    PORT
      LAYER met4 ;
        RECT 596.470 0.000 596.770 1.000 ;
    END
  END um_ow[227]
  PIN um_ow[228]
    DIRECTION INPUT ;
    USE SIGNAL ;
    ANTENNAGATEAREA 0.593700 ;
    ANTENNADIFFAREA 0.434700 ;
    PORT
      LAYER met4 ;
        RECT 593.710 0.000 594.010 1.000 ;
    END
  END um_ow[228]
  PIN um_ow[229]
    DIRECTION INPUT ;
    USE SIGNAL ;
    ANTENNAGATEAREA 0.593700 ;
    ANTENNADIFFAREA 0.434700 ;
    PORT
      LAYER met4 ;
        RECT 590.950 0.000 591.250 1.000 ;
    END
  END um_ow[229]
  PIN um_ow[22]
    DIRECTION INPUT ;
    USE SIGNAL ;
    ANTENNAGATEAREA 0.593700 ;
    ANTENNADIFFAREA 0.434700 ;
    PORT
      LAYER met4 ;
        RECT 1261.630 53.400 1261.930 54.400 ;
    END
  END um_ow[22]
  PIN um_ow[230]
    DIRECTION INPUT ;
    USE SIGNAL ;
    ANTENNAGATEAREA 0.593700 ;
    ANTENNADIFFAREA 0.434700 ;
    PORT
      LAYER met4 ;
        RECT 588.190 0.000 588.490 1.000 ;
    END
  END um_ow[230]
  PIN um_ow[231]
    DIRECTION INPUT ;
    USE SIGNAL ;
    ANTENNAGATEAREA 0.593700 ;
    ANTENNADIFFAREA 0.434700 ;
    PORT
      LAYER met4 ;
        RECT 585.430 0.000 585.730 1.000 ;
    END
  END um_ow[231]
  PIN um_ow[232]
    DIRECTION INPUT ;
    USE SIGNAL ;
    ANTENNAGATEAREA 0.593700 ;
    ANTENNADIFFAREA 0.434700 ;
    PORT
      LAYER met4 ;
        RECT 582.670 0.000 582.970 1.000 ;
    END
  END um_ow[232]
  PIN um_ow[233]
    DIRECTION INPUT ;
    USE SIGNAL ;
    ANTENNAGATEAREA 0.593700 ;
    ANTENNADIFFAREA 0.434700 ;
    PORT
      LAYER met4 ;
        RECT 579.910 0.000 580.210 1.000 ;
    END
  END um_ow[233]
  PIN um_ow[234]
    DIRECTION INPUT ;
    USE SIGNAL ;
    ANTENNAGATEAREA 0.593700 ;
    ANTENNADIFFAREA 0.434700 ;
    PORT
      LAYER met4 ;
        RECT 577.150 0.000 577.450 1.000 ;
    END
  END um_ow[234]
  PIN um_ow[235]
    DIRECTION INPUT ;
    USE SIGNAL ;
    ANTENNAGATEAREA 0.593700 ;
    ANTENNADIFFAREA 0.434700 ;
    PORT
      LAYER met4 ;
        RECT 574.390 0.000 574.690 1.000 ;
    END
  END um_ow[235]
  PIN um_ow[236]
    DIRECTION INPUT ;
    USE SIGNAL ;
    ANTENNAGATEAREA 0.593700 ;
    ANTENNADIFFAREA 0.434700 ;
    PORT
      LAYER met4 ;
        RECT 571.630 0.000 571.930 1.000 ;
    END
  END um_ow[236]
  PIN um_ow[237]
    DIRECTION INPUT ;
    USE SIGNAL ;
    ANTENNAGATEAREA 0.593700 ;
    ANTENNADIFFAREA 0.434700 ;
    PORT
      LAYER met4 ;
        RECT 568.870 0.000 569.170 1.000 ;
    END
  END um_ow[237]
  PIN um_ow[238]
    DIRECTION INPUT ;
    USE SIGNAL ;
    ANTENNAGATEAREA 0.593700 ;
    ANTENNADIFFAREA 0.434700 ;
    PORT
      LAYER met4 ;
        RECT 566.110 0.000 566.410 1.000 ;
    END
  END um_ow[238]
  PIN um_ow[239]
    DIRECTION INPUT ;
    USE SIGNAL ;
    ANTENNAGATEAREA 0.593700 ;
    ANTENNADIFFAREA 0.434700 ;
    PORT
      LAYER met4 ;
        RECT 563.350 0.000 563.650 1.000 ;
    END
  END um_ow[239]
  PIN um_ow[23]
    DIRECTION INPUT ;
    USE SIGNAL ;
    ANTENNAGATEAREA 0.593700 ;
    ANTENNADIFFAREA 0.434700 ;
    PORT
      LAYER met4 ;
        RECT 1258.870 53.400 1259.170 54.400 ;
    END
  END um_ow[23]
  PIN um_ow[240]
    DIRECTION INPUT ;
    USE SIGNAL ;
    ANTENNAGATEAREA 0.593700 ;
    ANTENNADIFFAREA 0.434700 ;
    PORT
      LAYER met4 ;
        RECT 452.950 53.400 453.250 54.400 ;
    END
  END um_ow[240]
  PIN um_ow[241]
    DIRECTION INPUT ;
    USE SIGNAL ;
    ANTENNAGATEAREA 0.593700 ;
    ANTENNADIFFAREA 0.434700 ;
    PORT
      LAYER met4 ;
        RECT 450.190 53.400 450.490 54.400 ;
    END
  END um_ow[241]
  PIN um_ow[242]
    DIRECTION INPUT ;
    USE SIGNAL ;
    ANTENNAGATEAREA 0.593700 ;
    ANTENNADIFFAREA 0.434700 ;
    PORT
      LAYER met4 ;
        RECT 447.430 53.400 447.730 54.400 ;
    END
  END um_ow[242]
  PIN um_ow[243]
    DIRECTION INPUT ;
    USE SIGNAL ;
    ANTENNAGATEAREA 0.593700 ;
    ANTENNADIFFAREA 0.434700 ;
    PORT
      LAYER met4 ;
        RECT 444.670 53.400 444.970 54.400 ;
    END
  END um_ow[243]
  PIN um_ow[244]
    DIRECTION INPUT ;
    USE SIGNAL ;
    ANTENNAGATEAREA 0.593700 ;
    ANTENNADIFFAREA 0.434700 ;
    PORT
      LAYER met4 ;
        RECT 441.910 53.400 442.210 54.400 ;
    END
  END um_ow[244]
  PIN um_ow[245]
    DIRECTION INPUT ;
    USE SIGNAL ;
    ANTENNAGATEAREA 0.593700 ;
    ANTENNADIFFAREA 0.434700 ;
    PORT
      LAYER met4 ;
        RECT 439.150 53.400 439.450 54.400 ;
    END
  END um_ow[245]
  PIN um_ow[246]
    DIRECTION INPUT ;
    USE SIGNAL ;
    ANTENNAGATEAREA 0.593700 ;
    ANTENNADIFFAREA 0.434700 ;
    PORT
      LAYER met4 ;
        RECT 436.390 53.400 436.690 54.400 ;
    END
  END um_ow[246]
  PIN um_ow[247]
    DIRECTION INPUT ;
    USE SIGNAL ;
    ANTENNAGATEAREA 0.593700 ;
    ANTENNADIFFAREA 0.434700 ;
    PORT
      LAYER met4 ;
        RECT 433.630 53.400 433.930 54.400 ;
    END
  END um_ow[247]
  PIN um_ow[248]
    DIRECTION INPUT ;
    USE SIGNAL ;
    ANTENNAGATEAREA 0.593700 ;
    ANTENNADIFFAREA 0.434700 ;
    PORT
      LAYER met4 ;
        RECT 430.870 53.400 431.170 54.400 ;
    END
  END um_ow[248]
  PIN um_ow[249]
    DIRECTION INPUT ;
    USE SIGNAL ;
    ANTENNAGATEAREA 0.593700 ;
    ANTENNADIFFAREA 0.434700 ;
    PORT
      LAYER met4 ;
        RECT 428.110 53.400 428.410 54.400 ;
    END
  END um_ow[249]
  PIN um_ow[24]
    DIRECTION INPUT ;
    USE SIGNAL ;
    ANTENNAGATEAREA 0.593700 ;
    ANTENNADIFFAREA 0.434700 ;
    PORT
      LAYER met4 ;
        RECT 1322.350 0.000 1322.650 1.000 ;
    END
  END um_ow[24]
  PIN um_ow[250]
    DIRECTION INPUT ;
    USE SIGNAL ;
    ANTENNAGATEAREA 0.593700 ;
    ANTENNADIFFAREA 0.434700 ;
    PORT
      LAYER met4 ;
        RECT 425.350 53.400 425.650 54.400 ;
    END
  END um_ow[250]
  PIN um_ow[251]
    DIRECTION INPUT ;
    USE SIGNAL ;
    ANTENNAGATEAREA 0.593700 ;
    ANTENNADIFFAREA 0.434700 ;
    PORT
      LAYER met4 ;
        RECT 422.590 53.400 422.890 54.400 ;
    END
  END um_ow[251]
  PIN um_ow[252]
    DIRECTION INPUT ;
    USE SIGNAL ;
    ANTENNAGATEAREA 0.593700 ;
    ANTENNADIFFAREA 0.434700 ;
    PORT
      LAYER met4 ;
        RECT 419.830 53.400 420.130 54.400 ;
    END
  END um_ow[252]
  PIN um_ow[253]
    DIRECTION INPUT ;
    USE SIGNAL ;
    ANTENNAGATEAREA 0.593700 ;
    ANTENNADIFFAREA 0.434700 ;
    PORT
      LAYER met4 ;
        RECT 417.070 53.400 417.370 54.400 ;
    END
  END um_ow[253]
  PIN um_ow[254]
    DIRECTION INPUT ;
    USE SIGNAL ;
    ANTENNAGATEAREA 0.593700 ;
    ANTENNADIFFAREA 0.434700 ;
    PORT
      LAYER met4 ;
        RECT 414.310 53.400 414.610 54.400 ;
    END
  END um_ow[254]
  PIN um_ow[255]
    DIRECTION INPUT ;
    USE SIGNAL ;
    ANTENNAGATEAREA 0.593700 ;
    ANTENNADIFFAREA 0.434700 ;
    PORT
      LAYER met4 ;
        RECT 411.550 53.400 411.850 54.400 ;
    END
  END um_ow[255]
  PIN um_ow[256]
    DIRECTION INPUT ;
    USE SIGNAL ;
    ANTENNAGATEAREA 0.593700 ;
    ANTENNADIFFAREA 0.434700 ;
    PORT
      LAYER met4 ;
        RECT 408.790 53.400 409.090 54.400 ;
    END
  END um_ow[256]
  PIN um_ow[257]
    DIRECTION INPUT ;
    USE SIGNAL ;
    ANTENNAGATEAREA 0.593700 ;
    ANTENNADIFFAREA 0.434700 ;
    PORT
      LAYER met4 ;
        RECT 406.030 53.400 406.330 54.400 ;
    END
  END um_ow[257]
  PIN um_ow[258]
    DIRECTION INPUT ;
    USE SIGNAL ;
    ANTENNAGATEAREA 0.593700 ;
    ANTENNADIFFAREA 0.434700 ;
    PORT
      LAYER met4 ;
        RECT 403.270 53.400 403.570 54.400 ;
    END
  END um_ow[258]
  PIN um_ow[259]
    DIRECTION INPUT ;
    USE SIGNAL ;
    ANTENNAGATEAREA 0.593700 ;
    ANTENNADIFFAREA 0.434700 ;
    PORT
      LAYER met4 ;
        RECT 400.510 53.400 400.810 54.400 ;
    END
  END um_ow[259]
  PIN um_ow[25]
    DIRECTION INPUT ;
    USE SIGNAL ;
    ANTENNAGATEAREA 0.593700 ;
    ANTENNADIFFAREA 0.434700 ;
    PORT
      LAYER met4 ;
        RECT 1319.590 0.000 1319.890 1.000 ;
    END
  END um_ow[25]
  PIN um_ow[260]
    DIRECTION INPUT ;
    USE SIGNAL ;
    ANTENNAGATEAREA 0.593700 ;
    ANTENNADIFFAREA 0.434700 ;
    PORT
      LAYER met4 ;
        RECT 397.750 53.400 398.050 54.400 ;
    END
  END um_ow[260]
  PIN um_ow[261]
    DIRECTION INPUT ;
    USE SIGNAL ;
    ANTENNAGATEAREA 0.593700 ;
    ANTENNADIFFAREA 0.434700 ;
    PORT
      LAYER met4 ;
        RECT 394.990 53.400 395.290 54.400 ;
    END
  END um_ow[261]
  PIN um_ow[262]
    DIRECTION INPUT ;
    USE SIGNAL ;
    ANTENNAGATEAREA 0.593700 ;
    ANTENNADIFFAREA 0.434700 ;
    PORT
      LAYER met4 ;
        RECT 392.230 53.400 392.530 54.400 ;
    END
  END um_ow[262]
  PIN um_ow[263]
    DIRECTION INPUT ;
    USE SIGNAL ;
    ANTENNAGATEAREA 0.593700 ;
    ANTENNADIFFAREA 0.434700 ;
    PORT
      LAYER met4 ;
        RECT 389.470 53.400 389.770 54.400 ;
    END
  END um_ow[263]
  PIN um_ow[264]
    DIRECTION INPUT ;
    USE SIGNAL ;
    ANTENNAGATEAREA 0.593700 ;
    ANTENNADIFFAREA 0.434700 ;
    PORT
      LAYER met4 ;
        RECT 452.950 0.000 453.250 1.000 ;
    END
  END um_ow[264]
  PIN um_ow[265]
    DIRECTION INPUT ;
    USE SIGNAL ;
    ANTENNAGATEAREA 0.593700 ;
    ANTENNADIFFAREA 0.434700 ;
    PORT
      LAYER met4 ;
        RECT 450.190 0.000 450.490 1.000 ;
    END
  END um_ow[265]
  PIN um_ow[266]
    DIRECTION INPUT ;
    USE SIGNAL ;
    ANTENNAGATEAREA 0.593700 ;
    ANTENNADIFFAREA 0.434700 ;
    PORT
      LAYER met4 ;
        RECT 447.430 0.000 447.730 1.000 ;
    END
  END um_ow[266]
  PIN um_ow[267]
    DIRECTION INPUT ;
    USE SIGNAL ;
    ANTENNAGATEAREA 0.593700 ;
    ANTENNADIFFAREA 0.434700 ;
    PORT
      LAYER met4 ;
        RECT 444.670 0.000 444.970 1.000 ;
    END
  END um_ow[267]
  PIN um_ow[268]
    DIRECTION INPUT ;
    USE SIGNAL ;
    ANTENNAGATEAREA 0.593700 ;
    ANTENNADIFFAREA 0.434700 ;
    PORT
      LAYER met4 ;
        RECT 441.910 0.000 442.210 1.000 ;
    END
  END um_ow[268]
  PIN um_ow[269]
    DIRECTION INPUT ;
    USE SIGNAL ;
    ANTENNAGATEAREA 0.593700 ;
    ANTENNADIFFAREA 0.434700 ;
    PORT
      LAYER met4 ;
        RECT 439.150 0.000 439.450 1.000 ;
    END
  END um_ow[269]
  PIN um_ow[26]
    DIRECTION INPUT ;
    USE SIGNAL ;
    ANTENNAGATEAREA 0.593700 ;
    ANTENNADIFFAREA 0.434700 ;
    PORT
      LAYER met4 ;
        RECT 1316.830 0.000 1317.130 1.000 ;
    END
  END um_ow[26]
  PIN um_ow[270]
    DIRECTION INPUT ;
    USE SIGNAL ;
    ANTENNAGATEAREA 0.593700 ;
    ANTENNADIFFAREA 0.434700 ;
    PORT
      LAYER met4 ;
        RECT 436.390 0.000 436.690 1.000 ;
    END
  END um_ow[270]
  PIN um_ow[271]
    DIRECTION INPUT ;
    USE SIGNAL ;
    ANTENNAGATEAREA 0.593700 ;
    ANTENNADIFFAREA 0.434700 ;
    PORT
      LAYER met4 ;
        RECT 433.630 0.000 433.930 1.000 ;
    END
  END um_ow[271]
  PIN um_ow[272]
    DIRECTION INPUT ;
    USE SIGNAL ;
    ANTENNAGATEAREA 0.593700 ;
    ANTENNADIFFAREA 0.434700 ;
    PORT
      LAYER met4 ;
        RECT 430.870 0.000 431.170 1.000 ;
    END
  END um_ow[272]
  PIN um_ow[273]
    DIRECTION INPUT ;
    USE SIGNAL ;
    ANTENNAGATEAREA 0.593700 ;
    ANTENNADIFFAREA 0.434700 ;
    PORT
      LAYER met4 ;
        RECT 428.110 0.000 428.410 1.000 ;
    END
  END um_ow[273]
  PIN um_ow[274]
    DIRECTION INPUT ;
    USE SIGNAL ;
    ANTENNAGATEAREA 0.593700 ;
    ANTENNADIFFAREA 0.434700 ;
    PORT
      LAYER met4 ;
        RECT 425.350 0.000 425.650 1.000 ;
    END
  END um_ow[274]
  PIN um_ow[275]
    DIRECTION INPUT ;
    USE SIGNAL ;
    ANTENNAGATEAREA 0.593700 ;
    ANTENNADIFFAREA 0.434700 ;
    PORT
      LAYER met4 ;
        RECT 422.590 0.000 422.890 1.000 ;
    END
  END um_ow[275]
  PIN um_ow[276]
    DIRECTION INPUT ;
    USE SIGNAL ;
    ANTENNAGATEAREA 0.593700 ;
    ANTENNADIFFAREA 0.434700 ;
    PORT
      LAYER met4 ;
        RECT 419.830 0.000 420.130 1.000 ;
    END
  END um_ow[276]
  PIN um_ow[277]
    DIRECTION INPUT ;
    USE SIGNAL ;
    ANTENNAGATEAREA 0.593700 ;
    ANTENNADIFFAREA 0.434700 ;
    PORT
      LAYER met4 ;
        RECT 417.070 0.000 417.370 1.000 ;
    END
  END um_ow[277]
  PIN um_ow[278]
    DIRECTION INPUT ;
    USE SIGNAL ;
    ANTENNAGATEAREA 0.593700 ;
    ANTENNADIFFAREA 0.434700 ;
    PORT
      LAYER met4 ;
        RECT 414.310 0.000 414.610 1.000 ;
    END
  END um_ow[278]
  PIN um_ow[279]
    DIRECTION INPUT ;
    USE SIGNAL ;
    ANTENNAGATEAREA 0.593700 ;
    ANTENNADIFFAREA 0.434700 ;
    PORT
      LAYER met4 ;
        RECT 411.550 0.000 411.850 1.000 ;
    END
  END um_ow[279]
  PIN um_ow[27]
    DIRECTION INPUT ;
    USE SIGNAL ;
    ANTENNAGATEAREA 0.593700 ;
    ANTENNADIFFAREA 0.434700 ;
    PORT
      LAYER met4 ;
        RECT 1314.070 0.000 1314.370 1.000 ;
    END
  END um_ow[27]
  PIN um_ow[280]
    DIRECTION INPUT ;
    USE SIGNAL ;
    ANTENNAGATEAREA 0.593700 ;
    ANTENNADIFFAREA 0.434700 ;
    PORT
      LAYER met4 ;
        RECT 408.790 0.000 409.090 1.000 ;
    END
  END um_ow[280]
  PIN um_ow[281]
    DIRECTION INPUT ;
    USE SIGNAL ;
    ANTENNAGATEAREA 0.593700 ;
    ANTENNADIFFAREA 0.434700 ;
    PORT
      LAYER met4 ;
        RECT 406.030 0.000 406.330 1.000 ;
    END
  END um_ow[281]
  PIN um_ow[282]
    DIRECTION INPUT ;
    USE SIGNAL ;
    ANTENNAGATEAREA 0.593700 ;
    ANTENNADIFFAREA 0.434700 ;
    PORT
      LAYER met4 ;
        RECT 403.270 0.000 403.570 1.000 ;
    END
  END um_ow[282]
  PIN um_ow[283]
    DIRECTION INPUT ;
    USE SIGNAL ;
    ANTENNAGATEAREA 0.593700 ;
    ANTENNADIFFAREA 0.434700 ;
    PORT
      LAYER met4 ;
        RECT 400.510 0.000 400.810 1.000 ;
    END
  END um_ow[283]
  PIN um_ow[284]
    DIRECTION INPUT ;
    USE SIGNAL ;
    ANTENNAGATEAREA 0.593700 ;
    ANTENNADIFFAREA 0.434700 ;
    PORT
      LAYER met4 ;
        RECT 397.750 0.000 398.050 1.000 ;
    END
  END um_ow[284]
  PIN um_ow[285]
    DIRECTION INPUT ;
    USE SIGNAL ;
    ANTENNAGATEAREA 0.593700 ;
    ANTENNADIFFAREA 0.434700 ;
    PORT
      LAYER met4 ;
        RECT 394.990 0.000 395.290 1.000 ;
    END
  END um_ow[285]
  PIN um_ow[286]
    DIRECTION INPUT ;
    USE SIGNAL ;
    ANTENNAGATEAREA 0.593700 ;
    ANTENNADIFFAREA 0.434700 ;
    PORT
      LAYER met4 ;
        RECT 392.230 0.000 392.530 1.000 ;
    END
  END um_ow[286]
  PIN um_ow[287]
    DIRECTION INPUT ;
    USE SIGNAL ;
    ANTENNAGATEAREA 0.593700 ;
    ANTENNADIFFAREA 0.434700 ;
    PORT
      LAYER met4 ;
        RECT 389.470 0.000 389.770 1.000 ;
    END
  END um_ow[287]
  PIN um_ow[288]
    DIRECTION INPUT ;
    USE SIGNAL ;
    ANTENNAGATEAREA 0.593700 ;
    ANTENNADIFFAREA 0.434700 ;
    PORT
      LAYER met4 ;
        RECT 279.070 53.400 279.370 54.400 ;
    END
  END um_ow[288]
  PIN um_ow[289]
    DIRECTION INPUT ;
    USE SIGNAL ;
    ANTENNAGATEAREA 0.593700 ;
    ANTENNADIFFAREA 0.434700 ;
    PORT
      LAYER met4 ;
        RECT 276.310 53.400 276.610 54.400 ;
    END
  END um_ow[289]
  PIN um_ow[28]
    DIRECTION INPUT ;
    USE SIGNAL ;
    ANTENNAGATEAREA 0.593700 ;
    ANTENNADIFFAREA 0.434700 ;
    PORT
      LAYER met4 ;
        RECT 1311.310 0.000 1311.610 1.000 ;
    END
  END um_ow[28]
  PIN um_ow[290]
    DIRECTION INPUT ;
    USE SIGNAL ;
    ANTENNAGATEAREA 0.593700 ;
    ANTENNADIFFAREA 0.434700 ;
    PORT
      LAYER met4 ;
        RECT 273.550 53.400 273.850 54.400 ;
    END
  END um_ow[290]
  PIN um_ow[291]
    DIRECTION INPUT ;
    USE SIGNAL ;
    ANTENNAGATEAREA 0.593700 ;
    ANTENNADIFFAREA 0.434700 ;
    PORT
      LAYER met4 ;
        RECT 270.790 53.400 271.090 54.400 ;
    END
  END um_ow[291]
  PIN um_ow[292]
    DIRECTION INPUT ;
    USE SIGNAL ;
    ANTENNAGATEAREA 0.593700 ;
    ANTENNADIFFAREA 0.434700 ;
    PORT
      LAYER met4 ;
        RECT 268.030 53.400 268.330 54.400 ;
    END
  END um_ow[292]
  PIN um_ow[293]
    DIRECTION INPUT ;
    USE SIGNAL ;
    ANTENNAGATEAREA 0.593700 ;
    ANTENNADIFFAREA 0.434700 ;
    PORT
      LAYER met4 ;
        RECT 265.270 53.400 265.570 54.400 ;
    END
  END um_ow[293]
  PIN um_ow[294]
    DIRECTION INPUT ;
    USE SIGNAL ;
    ANTENNAGATEAREA 0.593700 ;
    ANTENNADIFFAREA 0.434700 ;
    PORT
      LAYER met4 ;
        RECT 262.510 53.400 262.810 54.400 ;
    END
  END um_ow[294]
  PIN um_ow[295]
    DIRECTION INPUT ;
    USE SIGNAL ;
    ANTENNAGATEAREA 0.593700 ;
    ANTENNADIFFAREA 0.434700 ;
    PORT
      LAYER met4 ;
        RECT 259.750 53.400 260.050 54.400 ;
    END
  END um_ow[295]
  PIN um_ow[296]
    DIRECTION INPUT ;
    USE SIGNAL ;
    ANTENNAGATEAREA 0.593700 ;
    ANTENNADIFFAREA 0.434700 ;
    PORT
      LAYER met4 ;
        RECT 256.990 53.400 257.290 54.400 ;
    END
  END um_ow[296]
  PIN um_ow[297]
    DIRECTION INPUT ;
    USE SIGNAL ;
    ANTENNAGATEAREA 0.593700 ;
    ANTENNADIFFAREA 0.434700 ;
    PORT
      LAYER met4 ;
        RECT 254.230 53.400 254.530 54.400 ;
    END
  END um_ow[297]
  PIN um_ow[298]
    DIRECTION INPUT ;
    USE SIGNAL ;
    ANTENNAGATEAREA 0.593700 ;
    ANTENNADIFFAREA 0.434700 ;
    PORT
      LAYER met4 ;
        RECT 251.470 53.400 251.770 54.400 ;
    END
  END um_ow[298]
  PIN um_ow[299]
    DIRECTION INPUT ;
    USE SIGNAL ;
    ANTENNAGATEAREA 0.593700 ;
    ANTENNADIFFAREA 0.434700 ;
    PORT
      LAYER met4 ;
        RECT 248.710 53.400 249.010 54.400 ;
    END
  END um_ow[299]
  PIN um_ow[29]
    DIRECTION INPUT ;
    USE SIGNAL ;
    ANTENNAGATEAREA 0.593700 ;
    ANTENNADIFFAREA 0.434700 ;
    PORT
      LAYER met4 ;
        RECT 1308.550 0.000 1308.850 1.000 ;
    END
  END um_ow[29]
  PIN um_ow[2]
    DIRECTION INPUT ;
    USE SIGNAL ;
    ANTENNAGATEAREA 0.593700 ;
    ANTENNADIFFAREA 0.434700 ;
    PORT
      LAYER met4 ;
        RECT 1316.830 53.400 1317.130 54.400 ;
    END
  END um_ow[2]
  PIN um_ow[300]
    DIRECTION INPUT ;
    USE SIGNAL ;
    ANTENNAGATEAREA 0.593700 ;
    ANTENNADIFFAREA 0.434700 ;
    PORT
      LAYER met4 ;
        RECT 245.950 53.400 246.250 54.400 ;
    END
  END um_ow[300]
  PIN um_ow[301]
    DIRECTION INPUT ;
    USE SIGNAL ;
    ANTENNAGATEAREA 0.593700 ;
    ANTENNADIFFAREA 0.434700 ;
    PORT
      LAYER met4 ;
        RECT 243.190 53.400 243.490 54.400 ;
    END
  END um_ow[301]
  PIN um_ow[302]
    DIRECTION INPUT ;
    USE SIGNAL ;
    ANTENNAGATEAREA 0.593700 ;
    ANTENNADIFFAREA 0.434700 ;
    PORT
      LAYER met4 ;
        RECT 240.430 53.400 240.730 54.400 ;
    END
  END um_ow[302]
  PIN um_ow[303]
    DIRECTION INPUT ;
    USE SIGNAL ;
    ANTENNAGATEAREA 0.593700 ;
    ANTENNADIFFAREA 0.434700 ;
    PORT
      LAYER met4 ;
        RECT 237.670 53.400 237.970 54.400 ;
    END
  END um_ow[303]
  PIN um_ow[304]
    DIRECTION INPUT ;
    USE SIGNAL ;
    ANTENNAGATEAREA 0.593700 ;
    ANTENNADIFFAREA 0.434700 ;
    PORT
      LAYER met4 ;
        RECT 234.910 53.400 235.210 54.400 ;
    END
  END um_ow[304]
  PIN um_ow[305]
    DIRECTION INPUT ;
    USE SIGNAL ;
    ANTENNAGATEAREA 0.593700 ;
    ANTENNADIFFAREA 0.434700 ;
    PORT
      LAYER met4 ;
        RECT 232.150 53.400 232.450 54.400 ;
    END
  END um_ow[305]
  PIN um_ow[306]
    DIRECTION INPUT ;
    USE SIGNAL ;
    ANTENNAGATEAREA 0.593700 ;
    ANTENNADIFFAREA 0.434700 ;
    PORT
      LAYER met4 ;
        RECT 229.390 53.400 229.690 54.400 ;
    END
  END um_ow[306]
  PIN um_ow[307]
    DIRECTION INPUT ;
    USE SIGNAL ;
    ANTENNAGATEAREA 0.593700 ;
    ANTENNADIFFAREA 0.434700 ;
    PORT
      LAYER met4 ;
        RECT 226.630 53.400 226.930 54.400 ;
    END
  END um_ow[307]
  PIN um_ow[308]
    DIRECTION INPUT ;
    USE SIGNAL ;
    ANTENNAGATEAREA 0.593700 ;
    ANTENNADIFFAREA 0.434700 ;
    PORT
      LAYER met4 ;
        RECT 223.870 53.400 224.170 54.400 ;
    END
  END um_ow[308]
  PIN um_ow[309]
    DIRECTION INPUT ;
    USE SIGNAL ;
    ANTENNAGATEAREA 0.593700 ;
    ANTENNADIFFAREA 0.434700 ;
    PORT
      LAYER met4 ;
        RECT 221.110 53.400 221.410 54.400 ;
    END
  END um_ow[309]
  PIN um_ow[30]
    DIRECTION INPUT ;
    USE SIGNAL ;
    ANTENNAGATEAREA 0.593700 ;
    ANTENNADIFFAREA 0.434700 ;
    PORT
      LAYER met4 ;
        RECT 1305.790 0.000 1306.090 1.000 ;
    END
  END um_ow[30]
  PIN um_ow[310]
    DIRECTION INPUT ;
    USE SIGNAL ;
    ANTENNAGATEAREA 0.593700 ;
    ANTENNADIFFAREA 0.434700 ;
    PORT
      LAYER met4 ;
        RECT 218.350 53.400 218.650 54.400 ;
    END
  END um_ow[310]
  PIN um_ow[311]
    DIRECTION INPUT ;
    USE SIGNAL ;
    ANTENNAGATEAREA 0.593700 ;
    ANTENNADIFFAREA 0.434700 ;
    PORT
      LAYER met4 ;
        RECT 215.590 53.400 215.890 54.400 ;
    END
  END um_ow[311]
  PIN um_ow[312]
    DIRECTION INPUT ;
    USE SIGNAL ;
    ANTENNAGATEAREA 0.593700 ;
    ANTENNADIFFAREA 0.434700 ;
    PORT
      LAYER met4 ;
        RECT 279.070 0.000 279.370 1.000 ;
    END
  END um_ow[312]
  PIN um_ow[313]
    DIRECTION INPUT ;
    USE SIGNAL ;
    ANTENNAGATEAREA 0.593700 ;
    ANTENNADIFFAREA 0.434700 ;
    PORT
      LAYER met4 ;
        RECT 276.310 0.000 276.610 1.000 ;
    END
  END um_ow[313]
  PIN um_ow[314]
    DIRECTION INPUT ;
    USE SIGNAL ;
    ANTENNAGATEAREA 0.593700 ;
    ANTENNADIFFAREA 0.434700 ;
    PORT
      LAYER met4 ;
        RECT 273.550 0.000 273.850 1.000 ;
    END
  END um_ow[314]
  PIN um_ow[315]
    DIRECTION INPUT ;
    USE SIGNAL ;
    ANTENNAGATEAREA 0.593700 ;
    ANTENNADIFFAREA 0.434700 ;
    PORT
      LAYER met4 ;
        RECT 270.790 0.000 271.090 1.000 ;
    END
  END um_ow[315]
  PIN um_ow[316]
    DIRECTION INPUT ;
    USE SIGNAL ;
    ANTENNAGATEAREA 0.593700 ;
    ANTENNADIFFAREA 0.434700 ;
    PORT
      LAYER met4 ;
        RECT 268.030 0.000 268.330 1.000 ;
    END
  END um_ow[316]
  PIN um_ow[317]
    DIRECTION INPUT ;
    USE SIGNAL ;
    ANTENNAGATEAREA 0.593700 ;
    ANTENNADIFFAREA 0.434700 ;
    PORT
      LAYER met4 ;
        RECT 265.270 0.000 265.570 1.000 ;
    END
  END um_ow[317]
  PIN um_ow[318]
    DIRECTION INPUT ;
    USE SIGNAL ;
    ANTENNAGATEAREA 0.593700 ;
    ANTENNADIFFAREA 0.434700 ;
    PORT
      LAYER met4 ;
        RECT 262.510 0.000 262.810 1.000 ;
    END
  END um_ow[318]
  PIN um_ow[319]
    DIRECTION INPUT ;
    USE SIGNAL ;
    ANTENNAGATEAREA 0.593700 ;
    ANTENNADIFFAREA 0.434700 ;
    PORT
      LAYER met4 ;
        RECT 259.750 0.000 260.050 1.000 ;
    END
  END um_ow[319]
  PIN um_ow[31]
    DIRECTION INPUT ;
    USE SIGNAL ;
    ANTENNAGATEAREA 0.593700 ;
    ANTENNADIFFAREA 0.434700 ;
    PORT
      LAYER met4 ;
        RECT 1303.030 0.000 1303.330 1.000 ;
    END
  END um_ow[31]
  PIN um_ow[320]
    DIRECTION INPUT ;
    USE SIGNAL ;
    ANTENNAGATEAREA 0.593700 ;
    ANTENNADIFFAREA 0.434700 ;
    PORT
      LAYER met4 ;
        RECT 256.990 0.000 257.290 1.000 ;
    END
  END um_ow[320]
  PIN um_ow[321]
    DIRECTION INPUT ;
    USE SIGNAL ;
    ANTENNAGATEAREA 0.593700 ;
    ANTENNADIFFAREA 0.434700 ;
    PORT
      LAYER met4 ;
        RECT 254.230 0.000 254.530 1.000 ;
    END
  END um_ow[321]
  PIN um_ow[322]
    DIRECTION INPUT ;
    USE SIGNAL ;
    ANTENNAGATEAREA 0.593700 ;
    ANTENNADIFFAREA 0.434700 ;
    PORT
      LAYER met4 ;
        RECT 251.470 0.000 251.770 1.000 ;
    END
  END um_ow[322]
  PIN um_ow[323]
    DIRECTION INPUT ;
    USE SIGNAL ;
    ANTENNAGATEAREA 0.593700 ;
    ANTENNADIFFAREA 0.434700 ;
    PORT
      LAYER met4 ;
        RECT 248.710 0.000 249.010 1.000 ;
    END
  END um_ow[323]
  PIN um_ow[324]
    DIRECTION INPUT ;
    USE SIGNAL ;
    ANTENNAGATEAREA 0.593700 ;
    ANTENNADIFFAREA 0.434700 ;
    PORT
      LAYER met4 ;
        RECT 245.950 0.000 246.250 1.000 ;
    END
  END um_ow[324]
  PIN um_ow[325]
    DIRECTION INPUT ;
    USE SIGNAL ;
    ANTENNAGATEAREA 0.593700 ;
    ANTENNADIFFAREA 0.434700 ;
    PORT
      LAYER met4 ;
        RECT 243.190 0.000 243.490 1.000 ;
    END
  END um_ow[325]
  PIN um_ow[326]
    DIRECTION INPUT ;
    USE SIGNAL ;
    ANTENNAGATEAREA 0.593700 ;
    ANTENNADIFFAREA 0.434700 ;
    PORT
      LAYER met4 ;
        RECT 240.430 0.000 240.730 1.000 ;
    END
  END um_ow[326]
  PIN um_ow[327]
    DIRECTION INPUT ;
    USE SIGNAL ;
    ANTENNAGATEAREA 0.593700 ;
    ANTENNADIFFAREA 0.434700 ;
    PORT
      LAYER met4 ;
        RECT 237.670 0.000 237.970 1.000 ;
    END
  END um_ow[327]
  PIN um_ow[328]
    DIRECTION INPUT ;
    USE SIGNAL ;
    ANTENNAGATEAREA 0.593700 ;
    ANTENNADIFFAREA 0.434700 ;
    PORT
      LAYER met4 ;
        RECT 234.910 0.000 235.210 1.000 ;
    END
  END um_ow[328]
  PIN um_ow[329]
    DIRECTION INPUT ;
    USE SIGNAL ;
    ANTENNAGATEAREA 0.593700 ;
    ANTENNADIFFAREA 0.434700 ;
    PORT
      LAYER met4 ;
        RECT 232.150 0.000 232.450 1.000 ;
    END
  END um_ow[329]
  PIN um_ow[32]
    DIRECTION INPUT ;
    USE SIGNAL ;
    ANTENNAGATEAREA 0.593700 ;
    ANTENNADIFFAREA 0.434700 ;
    PORT
      LAYER met4 ;
        RECT 1300.270 0.000 1300.570 1.000 ;
    END
  END um_ow[32]
  PIN um_ow[330]
    DIRECTION INPUT ;
    USE SIGNAL ;
    ANTENNAGATEAREA 0.593700 ;
    ANTENNADIFFAREA 0.434700 ;
    PORT
      LAYER met4 ;
        RECT 229.390 0.000 229.690 1.000 ;
    END
  END um_ow[330]
  PIN um_ow[331]
    DIRECTION INPUT ;
    USE SIGNAL ;
    ANTENNAGATEAREA 0.593700 ;
    ANTENNADIFFAREA 0.434700 ;
    PORT
      LAYER met4 ;
        RECT 226.630 0.000 226.930 1.000 ;
    END
  END um_ow[331]
  PIN um_ow[332]
    DIRECTION INPUT ;
    USE SIGNAL ;
    ANTENNAGATEAREA 0.593700 ;
    ANTENNADIFFAREA 0.434700 ;
    PORT
      LAYER met4 ;
        RECT 223.870 0.000 224.170 1.000 ;
    END
  END um_ow[332]
  PIN um_ow[333]
    DIRECTION INPUT ;
    USE SIGNAL ;
    ANTENNAGATEAREA 0.593700 ;
    ANTENNADIFFAREA 0.434700 ;
    PORT
      LAYER met4 ;
        RECT 221.110 0.000 221.410 1.000 ;
    END
  END um_ow[333]
  PIN um_ow[334]
    DIRECTION INPUT ;
    USE SIGNAL ;
    ANTENNAGATEAREA 0.593700 ;
    ANTENNADIFFAREA 0.434700 ;
    PORT
      LAYER met4 ;
        RECT 218.350 0.000 218.650 1.000 ;
    END
  END um_ow[334]
  PIN um_ow[335]
    DIRECTION INPUT ;
    USE SIGNAL ;
    ANTENNAGATEAREA 0.593700 ;
    ANTENNADIFFAREA 0.434700 ;
    PORT
      LAYER met4 ;
        RECT 215.590 0.000 215.890 1.000 ;
    END
  END um_ow[335]
  PIN um_ow[336]
    DIRECTION INPUT ;
    USE SIGNAL ;
    ANTENNAGATEAREA 0.593700 ;
    ANTENNADIFFAREA 0.434700 ;
    PORT
      LAYER met4 ;
        RECT 105.190 53.400 105.490 54.400 ;
    END
  END um_ow[336]
  PIN um_ow[337]
    DIRECTION INPUT ;
    USE SIGNAL ;
    ANTENNAGATEAREA 0.593700 ;
    ANTENNADIFFAREA 0.434700 ;
    PORT
      LAYER met4 ;
        RECT 102.430 53.400 102.730 54.400 ;
    END
  END um_ow[337]
  PIN um_ow[338]
    DIRECTION INPUT ;
    USE SIGNAL ;
    ANTENNAGATEAREA 0.593700 ;
    ANTENNADIFFAREA 0.434700 ;
    PORT
      LAYER met4 ;
        RECT 99.670 53.400 99.970 54.400 ;
    END
  END um_ow[338]
  PIN um_ow[339]
    DIRECTION INPUT ;
    USE SIGNAL ;
    ANTENNAGATEAREA 0.593700 ;
    ANTENNADIFFAREA 0.434700 ;
    PORT
      LAYER met4 ;
        RECT 96.910 53.400 97.210 54.400 ;
    END
  END um_ow[339]
  PIN um_ow[33]
    DIRECTION INPUT ;
    USE SIGNAL ;
    ANTENNAGATEAREA 0.593700 ;
    ANTENNADIFFAREA 0.434700 ;
    PORT
      LAYER met4 ;
        RECT 1297.510 0.000 1297.810 1.000 ;
    END
  END um_ow[33]
  PIN um_ow[340]
    DIRECTION INPUT ;
    USE SIGNAL ;
    ANTENNAGATEAREA 0.593700 ;
    ANTENNADIFFAREA 0.434700 ;
    PORT
      LAYER met4 ;
        RECT 94.150 53.400 94.450 54.400 ;
    END
  END um_ow[340]
  PIN um_ow[341]
    DIRECTION INPUT ;
    USE SIGNAL ;
    ANTENNAGATEAREA 0.593700 ;
    ANTENNADIFFAREA 0.434700 ;
    PORT
      LAYER met4 ;
        RECT 91.390 53.400 91.690 54.400 ;
    END
  END um_ow[341]
  PIN um_ow[342]
    DIRECTION INPUT ;
    USE SIGNAL ;
    ANTENNAGATEAREA 0.593700 ;
    ANTENNADIFFAREA 0.434700 ;
    PORT
      LAYER met4 ;
        RECT 88.630 53.400 88.930 54.400 ;
    END
  END um_ow[342]
  PIN um_ow[343]
    DIRECTION INPUT ;
    USE SIGNAL ;
    ANTENNAGATEAREA 0.593700 ;
    ANTENNADIFFAREA 0.434700 ;
    PORT
      LAYER met4 ;
        RECT 85.870 53.400 86.170 54.400 ;
    END
  END um_ow[343]
  PIN um_ow[344]
    DIRECTION INPUT ;
    USE SIGNAL ;
    ANTENNAGATEAREA 0.593700 ;
    ANTENNADIFFAREA 0.434700 ;
    PORT
      LAYER met4 ;
        RECT 83.110 53.400 83.410 54.400 ;
    END
  END um_ow[344]
  PIN um_ow[345]
    DIRECTION INPUT ;
    USE SIGNAL ;
    ANTENNAGATEAREA 0.593700 ;
    ANTENNADIFFAREA 0.434700 ;
    PORT
      LAYER met4 ;
        RECT 80.350 53.400 80.650 54.400 ;
    END
  END um_ow[345]
  PIN um_ow[346]
    DIRECTION INPUT ;
    USE SIGNAL ;
    ANTENNAGATEAREA 0.593700 ;
    ANTENNADIFFAREA 0.434700 ;
    PORT
      LAYER met4 ;
        RECT 77.590 53.400 77.890 54.400 ;
    END
  END um_ow[346]
  PIN um_ow[347]
    DIRECTION INPUT ;
    USE SIGNAL ;
    ANTENNAGATEAREA 0.593700 ;
    ANTENNADIFFAREA 0.434700 ;
    PORT
      LAYER met4 ;
        RECT 74.830 53.400 75.130 54.400 ;
    END
  END um_ow[347]
  PIN um_ow[348]
    DIRECTION INPUT ;
    USE SIGNAL ;
    ANTENNAGATEAREA 0.593700 ;
    ANTENNADIFFAREA 0.434700 ;
    PORT
      LAYER met4 ;
        RECT 72.070 53.400 72.370 54.400 ;
    END
  END um_ow[348]
  PIN um_ow[349]
    DIRECTION INPUT ;
    USE SIGNAL ;
    ANTENNAGATEAREA 0.593700 ;
    ANTENNADIFFAREA 0.434700 ;
    PORT
      LAYER met4 ;
        RECT 69.310 53.400 69.610 54.400 ;
    END
  END um_ow[349]
  PIN um_ow[34]
    DIRECTION INPUT ;
    USE SIGNAL ;
    ANTENNAGATEAREA 0.593700 ;
    ANTENNADIFFAREA 0.434700 ;
    PORT
      LAYER met4 ;
        RECT 1294.750 0.000 1295.050 1.000 ;
    END
  END um_ow[34]
  PIN um_ow[350]
    DIRECTION INPUT ;
    USE SIGNAL ;
    ANTENNAGATEAREA 0.593700 ;
    ANTENNADIFFAREA 0.434700 ;
    PORT
      LAYER met4 ;
        RECT 66.550 53.400 66.850 54.400 ;
    END
  END um_ow[350]
  PIN um_ow[351]
    DIRECTION INPUT ;
    USE SIGNAL ;
    ANTENNAGATEAREA 0.593700 ;
    ANTENNADIFFAREA 0.434700 ;
    PORT
      LAYER met4 ;
        RECT 63.790 53.400 64.090 54.400 ;
    END
  END um_ow[351]
  PIN um_ow[352]
    DIRECTION INPUT ;
    USE SIGNAL ;
    ANTENNAGATEAREA 0.593700 ;
    ANTENNADIFFAREA 0.434700 ;
    PORT
      LAYER met4 ;
        RECT 61.030 53.400 61.330 54.400 ;
    END
  END um_ow[352]
  PIN um_ow[353]
    DIRECTION INPUT ;
    USE SIGNAL ;
    ANTENNAGATEAREA 0.593700 ;
    ANTENNADIFFAREA 0.434700 ;
    PORT
      LAYER met4 ;
        RECT 58.270 53.400 58.570 54.400 ;
    END
  END um_ow[353]
  PIN um_ow[354]
    DIRECTION INPUT ;
    USE SIGNAL ;
    ANTENNAGATEAREA 0.593700 ;
    ANTENNADIFFAREA 0.434700 ;
    PORT
      LAYER met4 ;
        RECT 55.510 53.400 55.810 54.400 ;
    END
  END um_ow[354]
  PIN um_ow[355]
    DIRECTION INPUT ;
    USE SIGNAL ;
    ANTENNAGATEAREA 0.593700 ;
    ANTENNADIFFAREA 0.434700 ;
    PORT
      LAYER met4 ;
        RECT 52.750 53.400 53.050 54.400 ;
    END
  END um_ow[355]
  PIN um_ow[356]
    DIRECTION INPUT ;
    USE SIGNAL ;
    ANTENNAGATEAREA 0.593700 ;
    ANTENNADIFFAREA 0.434700 ;
    PORT
      LAYER met4 ;
        RECT 49.990 53.400 50.290 54.400 ;
    END
  END um_ow[356]
  PIN um_ow[357]
    DIRECTION INPUT ;
    USE SIGNAL ;
    ANTENNAGATEAREA 0.593700 ;
    ANTENNADIFFAREA 0.434700 ;
    PORT
      LAYER met4 ;
        RECT 47.230 53.400 47.530 54.400 ;
    END
  END um_ow[357]
  PIN um_ow[358]
    DIRECTION INPUT ;
    USE SIGNAL ;
    ANTENNAGATEAREA 0.593700 ;
    ANTENNADIFFAREA 0.434700 ;
    PORT
      LAYER met4 ;
        RECT 44.470 53.400 44.770 54.400 ;
    END
  END um_ow[358]
  PIN um_ow[359]
    DIRECTION INPUT ;
    USE SIGNAL ;
    ANTENNAGATEAREA 0.593700 ;
    ANTENNADIFFAREA 0.434700 ;
    PORT
      LAYER met4 ;
        RECT 41.710 53.400 42.010 54.400 ;
    END
  END um_ow[359]
  PIN um_ow[35]
    DIRECTION INPUT ;
    USE SIGNAL ;
    ANTENNAGATEAREA 0.593700 ;
    ANTENNADIFFAREA 0.434700 ;
    PORT
      LAYER met4 ;
        RECT 1291.990 0.000 1292.290 1.000 ;
    END
  END um_ow[35]
  PIN um_ow[360]
    DIRECTION INPUT ;
    USE SIGNAL ;
    ANTENNAGATEAREA 0.593700 ;
    ANTENNADIFFAREA 0.434700 ;
    PORT
      LAYER met4 ;
        RECT 105.190 0.000 105.490 1.000 ;
    END
  END um_ow[360]
  PIN um_ow[361]
    DIRECTION INPUT ;
    USE SIGNAL ;
    ANTENNAGATEAREA 0.593700 ;
    ANTENNADIFFAREA 0.434700 ;
    PORT
      LAYER met4 ;
        RECT 102.430 0.000 102.730 1.000 ;
    END
  END um_ow[361]
  PIN um_ow[362]
    DIRECTION INPUT ;
    USE SIGNAL ;
    ANTENNAGATEAREA 0.593700 ;
    ANTENNADIFFAREA 0.434700 ;
    PORT
      LAYER met4 ;
        RECT 99.670 0.000 99.970 1.000 ;
    END
  END um_ow[362]
  PIN um_ow[363]
    DIRECTION INPUT ;
    USE SIGNAL ;
    ANTENNAGATEAREA 0.593700 ;
    ANTENNADIFFAREA 0.434700 ;
    PORT
      LAYER met4 ;
        RECT 96.910 0.000 97.210 1.000 ;
    END
  END um_ow[363]
  PIN um_ow[364]
    DIRECTION INPUT ;
    USE SIGNAL ;
    ANTENNAGATEAREA 0.593700 ;
    ANTENNADIFFAREA 0.434700 ;
    PORT
      LAYER met4 ;
        RECT 94.150 0.000 94.450 1.000 ;
    END
  END um_ow[364]
  PIN um_ow[365]
    DIRECTION INPUT ;
    USE SIGNAL ;
    ANTENNAGATEAREA 0.593700 ;
    ANTENNADIFFAREA 0.434700 ;
    PORT
      LAYER met4 ;
        RECT 91.390 0.000 91.690 1.000 ;
    END
  END um_ow[365]
  PIN um_ow[366]
    DIRECTION INPUT ;
    USE SIGNAL ;
    ANTENNAGATEAREA 0.593700 ;
    ANTENNADIFFAREA 0.434700 ;
    PORT
      LAYER met4 ;
        RECT 88.630 0.000 88.930 1.000 ;
    END
  END um_ow[366]
  PIN um_ow[367]
    DIRECTION INPUT ;
    USE SIGNAL ;
    ANTENNAGATEAREA 0.593700 ;
    ANTENNADIFFAREA 0.434700 ;
    PORT
      LAYER met4 ;
        RECT 85.870 0.000 86.170 1.000 ;
    END
  END um_ow[367]
  PIN um_ow[368]
    DIRECTION INPUT ;
    USE SIGNAL ;
    ANTENNAGATEAREA 0.593700 ;
    ANTENNADIFFAREA 0.434700 ;
    PORT
      LAYER met4 ;
        RECT 83.110 0.000 83.410 1.000 ;
    END
  END um_ow[368]
  PIN um_ow[369]
    DIRECTION INPUT ;
    USE SIGNAL ;
    ANTENNAGATEAREA 0.593700 ;
    ANTENNADIFFAREA 0.434700 ;
    PORT
      LAYER met4 ;
        RECT 80.350 0.000 80.650 1.000 ;
    END
  END um_ow[369]
  PIN um_ow[36]
    DIRECTION INPUT ;
    USE SIGNAL ;
    ANTENNAGATEAREA 0.593700 ;
    ANTENNADIFFAREA 0.434700 ;
    PORT
      LAYER met4 ;
        RECT 1289.230 0.000 1289.530 1.000 ;
    END
  END um_ow[36]
  PIN um_ow[370]
    DIRECTION INPUT ;
    USE SIGNAL ;
    ANTENNAGATEAREA 0.593700 ;
    ANTENNADIFFAREA 0.434700 ;
    PORT
      LAYER met4 ;
        RECT 77.590 0.000 77.890 1.000 ;
    END
  END um_ow[370]
  PIN um_ow[371]
    DIRECTION INPUT ;
    USE SIGNAL ;
    ANTENNAGATEAREA 0.593700 ;
    ANTENNADIFFAREA 0.434700 ;
    PORT
      LAYER met4 ;
        RECT 74.830 0.000 75.130 1.000 ;
    END
  END um_ow[371]
  PIN um_ow[372]
    DIRECTION INPUT ;
    USE SIGNAL ;
    ANTENNAGATEAREA 0.593700 ;
    ANTENNADIFFAREA 0.434700 ;
    PORT
      LAYER met4 ;
        RECT 72.070 0.000 72.370 1.000 ;
    END
  END um_ow[372]
  PIN um_ow[373]
    DIRECTION INPUT ;
    USE SIGNAL ;
    ANTENNAGATEAREA 0.593700 ;
    ANTENNADIFFAREA 0.434700 ;
    PORT
      LAYER met4 ;
        RECT 69.310 0.000 69.610 1.000 ;
    END
  END um_ow[373]
  PIN um_ow[374]
    DIRECTION INPUT ;
    USE SIGNAL ;
    ANTENNAGATEAREA 0.593700 ;
    ANTENNADIFFAREA 0.434700 ;
    PORT
      LAYER met4 ;
        RECT 66.550 0.000 66.850 1.000 ;
    END
  END um_ow[374]
  PIN um_ow[375]
    DIRECTION INPUT ;
    USE SIGNAL ;
    ANTENNAGATEAREA 0.593700 ;
    ANTENNADIFFAREA 0.434700 ;
    PORT
      LAYER met4 ;
        RECT 63.790 0.000 64.090 1.000 ;
    END
  END um_ow[375]
  PIN um_ow[376]
    DIRECTION INPUT ;
    USE SIGNAL ;
    ANTENNAGATEAREA 0.593700 ;
    ANTENNADIFFAREA 0.434700 ;
    PORT
      LAYER met4 ;
        RECT 61.030 0.000 61.330 1.000 ;
    END
  END um_ow[376]
  PIN um_ow[377]
    DIRECTION INPUT ;
    USE SIGNAL ;
    ANTENNAGATEAREA 0.593700 ;
    ANTENNADIFFAREA 0.434700 ;
    PORT
      LAYER met4 ;
        RECT 58.270 0.000 58.570 1.000 ;
    END
  END um_ow[377]
  PIN um_ow[378]
    DIRECTION INPUT ;
    USE SIGNAL ;
    ANTENNAGATEAREA 0.593700 ;
    ANTENNADIFFAREA 0.434700 ;
    PORT
      LAYER met4 ;
        RECT 55.510 0.000 55.810 1.000 ;
    END
  END um_ow[378]
  PIN um_ow[379]
    DIRECTION INPUT ;
    USE SIGNAL ;
    ANTENNAGATEAREA 0.593700 ;
    ANTENNADIFFAREA 0.434700 ;
    PORT
      LAYER met4 ;
        RECT 52.750 0.000 53.050 1.000 ;
    END
  END um_ow[379]
  PIN um_ow[37]
    DIRECTION INPUT ;
    USE SIGNAL ;
    ANTENNAGATEAREA 0.593700 ;
    ANTENNADIFFAREA 0.434700 ;
    PORT
      LAYER met4 ;
        RECT 1286.470 0.000 1286.770 1.000 ;
    END
  END um_ow[37]
  PIN um_ow[380]
    DIRECTION INPUT ;
    USE SIGNAL ;
    ANTENNAGATEAREA 0.593700 ;
    ANTENNADIFFAREA 0.434700 ;
    PORT
      LAYER met4 ;
        RECT 49.990 0.000 50.290 1.000 ;
    END
  END um_ow[380]
  PIN um_ow[381]
    DIRECTION INPUT ;
    USE SIGNAL ;
    ANTENNAGATEAREA 0.593700 ;
    ANTENNADIFFAREA 0.434700 ;
    PORT
      LAYER met4 ;
        RECT 47.230 0.000 47.530 1.000 ;
    END
  END um_ow[381]
  PIN um_ow[382]
    DIRECTION INPUT ;
    USE SIGNAL ;
    ANTENNAGATEAREA 0.593700 ;
    ANTENNADIFFAREA 0.434700 ;
    PORT
      LAYER met4 ;
        RECT 44.470 0.000 44.770 1.000 ;
    END
  END um_ow[382]
  PIN um_ow[383]
    DIRECTION INPUT ;
    USE SIGNAL ;
    ANTENNAGATEAREA 0.593700 ;
    ANTENNADIFFAREA 0.434700 ;
    PORT
      LAYER met4 ;
        RECT 41.710 0.000 42.010 1.000 ;
    END
  END um_ow[383]
  PIN um_ow[38]
    DIRECTION INPUT ;
    USE SIGNAL ;
    ANTENNAGATEAREA 0.593700 ;
    ANTENNADIFFAREA 0.434700 ;
    PORT
      LAYER met4 ;
        RECT 1283.710 0.000 1284.010 1.000 ;
    END
  END um_ow[38]
  PIN um_ow[39]
    DIRECTION INPUT ;
    USE SIGNAL ;
    ANTENNAGATEAREA 0.593700 ;
    ANTENNADIFFAREA 0.434700 ;
    PORT
      LAYER met4 ;
        RECT 1280.950 0.000 1281.250 1.000 ;
    END
  END um_ow[39]
  PIN um_ow[3]
    DIRECTION INPUT ;
    USE SIGNAL ;
    ANTENNAGATEAREA 0.593700 ;
    ANTENNADIFFAREA 0.434700 ;
    PORT
      LAYER met4 ;
        RECT 1314.070 53.400 1314.370 54.400 ;
    END
  END um_ow[3]
  PIN um_ow[40]
    DIRECTION INPUT ;
    USE SIGNAL ;
    ANTENNAGATEAREA 0.593700 ;
    ANTENNADIFFAREA 0.434700 ;
    PORT
      LAYER met4 ;
        RECT 1278.190 0.000 1278.490 1.000 ;
    END
  END um_ow[40]
  PIN um_ow[41]
    DIRECTION INPUT ;
    USE SIGNAL ;
    ANTENNAGATEAREA 0.593700 ;
    ANTENNADIFFAREA 0.434700 ;
    PORT
      LAYER met4 ;
        RECT 1275.430 0.000 1275.730 1.000 ;
    END
  END um_ow[41]
  PIN um_ow[42]
    DIRECTION INPUT ;
    USE SIGNAL ;
    ANTENNAGATEAREA 0.593700 ;
    ANTENNADIFFAREA 0.434700 ;
    PORT
      LAYER met4 ;
        RECT 1272.670 0.000 1272.970 1.000 ;
    END
  END um_ow[42]
  PIN um_ow[43]
    DIRECTION INPUT ;
    USE SIGNAL ;
    ANTENNAGATEAREA 0.593700 ;
    ANTENNADIFFAREA 0.434700 ;
    PORT
      LAYER met4 ;
        RECT 1269.910 0.000 1270.210 1.000 ;
    END
  END um_ow[43]
  PIN um_ow[44]
    DIRECTION INPUT ;
    USE SIGNAL ;
    ANTENNAGATEAREA 0.593700 ;
    ANTENNADIFFAREA 0.434700 ;
    PORT
      LAYER met4 ;
        RECT 1267.150 0.000 1267.450 1.000 ;
    END
  END um_ow[44]
  PIN um_ow[45]
    DIRECTION INPUT ;
    USE SIGNAL ;
    ANTENNAGATEAREA 0.593700 ;
    ANTENNADIFFAREA 0.434700 ;
    PORT
      LAYER met4 ;
        RECT 1264.390 0.000 1264.690 1.000 ;
    END
  END um_ow[45]
  PIN um_ow[46]
    DIRECTION INPUT ;
    USE SIGNAL ;
    ANTENNAGATEAREA 0.593700 ;
    ANTENNADIFFAREA 0.434700 ;
    PORT
      LAYER met4 ;
        RECT 1261.630 0.000 1261.930 1.000 ;
    END
  END um_ow[46]
  PIN um_ow[47]
    DIRECTION INPUT ;
    USE SIGNAL ;
    ANTENNAGATEAREA 0.593700 ;
    ANTENNADIFFAREA 0.434700 ;
    PORT
      LAYER met4 ;
        RECT 1258.870 0.000 1259.170 1.000 ;
    END
  END um_ow[47]
  PIN um_ow[48]
    DIRECTION INPUT ;
    USE SIGNAL ;
    ANTENNAGATEAREA 0.593700 ;
    ANTENNADIFFAREA 0.434700 ;
    PORT
      LAYER met4 ;
        RECT 1148.470 53.400 1148.770 54.400 ;
    END
  END um_ow[48]
  PIN um_ow[49]
    DIRECTION INPUT ;
    USE SIGNAL ;
    ANTENNAGATEAREA 0.593700 ;
    ANTENNADIFFAREA 0.434700 ;
    PORT
      LAYER met4 ;
        RECT 1145.710 53.400 1146.010 54.400 ;
    END
  END um_ow[49]
  PIN um_ow[4]
    DIRECTION INPUT ;
    USE SIGNAL ;
    ANTENNAGATEAREA 0.593700 ;
    ANTENNADIFFAREA 0.434700 ;
    PORT
      LAYER met4 ;
        RECT 1311.310 53.400 1311.610 54.400 ;
    END
  END um_ow[4]
  PIN um_ow[50]
    DIRECTION INPUT ;
    USE SIGNAL ;
    ANTENNAGATEAREA 0.593700 ;
    ANTENNADIFFAREA 0.434700 ;
    PORT
      LAYER met4 ;
        RECT 1142.950 53.400 1143.250 54.400 ;
    END
  END um_ow[50]
  PIN um_ow[51]
    DIRECTION INPUT ;
    USE SIGNAL ;
    ANTENNAGATEAREA 0.593700 ;
    ANTENNADIFFAREA 0.434700 ;
    PORT
      LAYER met4 ;
        RECT 1140.190 53.400 1140.490 54.400 ;
    END
  END um_ow[51]
  PIN um_ow[52]
    DIRECTION INPUT ;
    USE SIGNAL ;
    ANTENNAGATEAREA 0.593700 ;
    ANTENNADIFFAREA 0.434700 ;
    PORT
      LAYER met4 ;
        RECT 1137.430 53.400 1137.730 54.400 ;
    END
  END um_ow[52]
  PIN um_ow[53]
    DIRECTION INPUT ;
    USE SIGNAL ;
    ANTENNAGATEAREA 0.593700 ;
    ANTENNADIFFAREA 0.434700 ;
    PORT
      LAYER met4 ;
        RECT 1134.670 53.400 1134.970 54.400 ;
    END
  END um_ow[53]
  PIN um_ow[54]
    DIRECTION INPUT ;
    USE SIGNAL ;
    ANTENNAGATEAREA 0.593700 ;
    ANTENNADIFFAREA 0.434700 ;
    PORT
      LAYER met4 ;
        RECT 1131.910 53.400 1132.210 54.400 ;
    END
  END um_ow[54]
  PIN um_ow[55]
    DIRECTION INPUT ;
    USE SIGNAL ;
    ANTENNAGATEAREA 0.593700 ;
    ANTENNADIFFAREA 0.434700 ;
    PORT
      LAYER met4 ;
        RECT 1129.150 53.400 1129.450 54.400 ;
    END
  END um_ow[55]
  PIN um_ow[56]
    DIRECTION INPUT ;
    USE SIGNAL ;
    ANTENNAGATEAREA 0.593700 ;
    ANTENNADIFFAREA 0.434700 ;
    PORT
      LAYER met4 ;
        RECT 1126.390 53.400 1126.690 54.400 ;
    END
  END um_ow[56]
  PIN um_ow[57]
    DIRECTION INPUT ;
    USE SIGNAL ;
    ANTENNAGATEAREA 0.593700 ;
    ANTENNADIFFAREA 0.434700 ;
    PORT
      LAYER met4 ;
        RECT 1123.630 53.400 1123.930 54.400 ;
    END
  END um_ow[57]
  PIN um_ow[58]
    DIRECTION INPUT ;
    USE SIGNAL ;
    ANTENNAGATEAREA 0.593700 ;
    ANTENNADIFFAREA 0.434700 ;
    PORT
      LAYER met4 ;
        RECT 1120.870 53.400 1121.170 54.400 ;
    END
  END um_ow[58]
  PIN um_ow[59]
    DIRECTION INPUT ;
    USE SIGNAL ;
    ANTENNAGATEAREA 0.593700 ;
    ANTENNADIFFAREA 0.434700 ;
    PORT
      LAYER met4 ;
        RECT 1118.110 53.400 1118.410 54.400 ;
    END
  END um_ow[59]
  PIN um_ow[5]
    DIRECTION INPUT ;
    USE SIGNAL ;
    ANTENNAGATEAREA 0.593700 ;
    ANTENNADIFFAREA 0.434700 ;
    PORT
      LAYER met4 ;
        RECT 1308.550 53.400 1308.850 54.400 ;
    END
  END um_ow[5]
  PIN um_ow[60]
    DIRECTION INPUT ;
    USE SIGNAL ;
    ANTENNAGATEAREA 0.593700 ;
    ANTENNADIFFAREA 0.434700 ;
    PORT
      LAYER met4 ;
        RECT 1115.350 53.400 1115.650 54.400 ;
    END
  END um_ow[60]
  PIN um_ow[61]
    DIRECTION INPUT ;
    USE SIGNAL ;
    ANTENNAGATEAREA 0.593700 ;
    ANTENNADIFFAREA 0.434700 ;
    PORT
      LAYER met4 ;
        RECT 1112.590 53.400 1112.890 54.400 ;
    END
  END um_ow[61]
  PIN um_ow[62]
    DIRECTION INPUT ;
    USE SIGNAL ;
    ANTENNAGATEAREA 0.593700 ;
    ANTENNADIFFAREA 0.434700 ;
    PORT
      LAYER met4 ;
        RECT 1109.830 53.400 1110.130 54.400 ;
    END
  END um_ow[62]
  PIN um_ow[63]
    DIRECTION INPUT ;
    USE SIGNAL ;
    ANTENNAGATEAREA 0.593700 ;
    ANTENNADIFFAREA 0.434700 ;
    PORT
      LAYER met4 ;
        RECT 1107.070 53.400 1107.370 54.400 ;
    END
  END um_ow[63]
  PIN um_ow[64]
    DIRECTION INPUT ;
    USE SIGNAL ;
    ANTENNAGATEAREA 0.593700 ;
    ANTENNADIFFAREA 0.434700 ;
    PORT
      LAYER met4 ;
        RECT 1104.310 53.400 1104.610 54.400 ;
    END
  END um_ow[64]
  PIN um_ow[65]
    DIRECTION INPUT ;
    USE SIGNAL ;
    ANTENNAGATEAREA 0.593700 ;
    ANTENNADIFFAREA 0.434700 ;
    PORT
      LAYER met4 ;
        RECT 1101.550 53.400 1101.850 54.400 ;
    END
  END um_ow[65]
  PIN um_ow[66]
    DIRECTION INPUT ;
    USE SIGNAL ;
    ANTENNAGATEAREA 0.593700 ;
    ANTENNADIFFAREA 0.434700 ;
    PORT
      LAYER met4 ;
        RECT 1098.790 53.400 1099.090 54.400 ;
    END
  END um_ow[66]
  PIN um_ow[67]
    DIRECTION INPUT ;
    USE SIGNAL ;
    ANTENNAGATEAREA 0.593700 ;
    ANTENNADIFFAREA 0.434700 ;
    PORT
      LAYER met4 ;
        RECT 1096.030 53.400 1096.330 54.400 ;
    END
  END um_ow[67]
  PIN um_ow[68]
    DIRECTION INPUT ;
    USE SIGNAL ;
    ANTENNAGATEAREA 0.593700 ;
    ANTENNADIFFAREA 0.434700 ;
    PORT
      LAYER met4 ;
        RECT 1093.270 53.400 1093.570 54.400 ;
    END
  END um_ow[68]
  PIN um_ow[69]
    DIRECTION INPUT ;
    USE SIGNAL ;
    ANTENNAGATEAREA 0.593700 ;
    ANTENNADIFFAREA 0.434700 ;
    PORT
      LAYER met4 ;
        RECT 1090.510 53.400 1090.810 54.400 ;
    END
  END um_ow[69]
  PIN um_ow[6]
    DIRECTION INPUT ;
    USE SIGNAL ;
    ANTENNAGATEAREA 0.593700 ;
    ANTENNADIFFAREA 0.434700 ;
    PORT
      LAYER met4 ;
        RECT 1305.790 53.400 1306.090 54.400 ;
    END
  END um_ow[6]
  PIN um_ow[70]
    DIRECTION INPUT ;
    USE SIGNAL ;
    ANTENNAGATEAREA 0.593700 ;
    ANTENNADIFFAREA 0.434700 ;
    PORT
      LAYER met4 ;
        RECT 1087.750 53.400 1088.050 54.400 ;
    END
  END um_ow[70]
  PIN um_ow[71]
    DIRECTION INPUT ;
    USE SIGNAL ;
    ANTENNAGATEAREA 0.593700 ;
    ANTENNADIFFAREA 0.434700 ;
    PORT
      LAYER met4 ;
        RECT 1084.990 53.400 1085.290 54.400 ;
    END
  END um_ow[71]
  PIN um_ow[72]
    DIRECTION INPUT ;
    USE SIGNAL ;
    ANTENNAGATEAREA 0.593700 ;
    ANTENNADIFFAREA 0.434700 ;
    PORT
      LAYER met4 ;
        RECT 1148.470 0.000 1148.770 1.000 ;
    END
  END um_ow[72]
  PIN um_ow[73]
    DIRECTION INPUT ;
    USE SIGNAL ;
    ANTENNAGATEAREA 0.593700 ;
    ANTENNADIFFAREA 0.434700 ;
    PORT
      LAYER met4 ;
        RECT 1145.710 0.000 1146.010 1.000 ;
    END
  END um_ow[73]
  PIN um_ow[74]
    DIRECTION INPUT ;
    USE SIGNAL ;
    ANTENNAGATEAREA 0.593700 ;
    ANTENNADIFFAREA 0.434700 ;
    PORT
      LAYER met4 ;
        RECT 1142.950 0.000 1143.250 1.000 ;
    END
  END um_ow[74]
  PIN um_ow[75]
    DIRECTION INPUT ;
    USE SIGNAL ;
    ANTENNAGATEAREA 0.593700 ;
    ANTENNADIFFAREA 0.434700 ;
    PORT
      LAYER met4 ;
        RECT 1140.190 0.000 1140.490 1.000 ;
    END
  END um_ow[75]
  PIN um_ow[76]
    DIRECTION INPUT ;
    USE SIGNAL ;
    ANTENNAGATEAREA 0.593700 ;
    ANTENNADIFFAREA 0.434700 ;
    PORT
      LAYER met4 ;
        RECT 1137.430 0.000 1137.730 1.000 ;
    END
  END um_ow[76]
  PIN um_ow[77]
    DIRECTION INPUT ;
    USE SIGNAL ;
    ANTENNAGATEAREA 0.593700 ;
    ANTENNADIFFAREA 0.434700 ;
    PORT
      LAYER met4 ;
        RECT 1134.670 0.000 1134.970 1.000 ;
    END
  END um_ow[77]
  PIN um_ow[78]
    DIRECTION INPUT ;
    USE SIGNAL ;
    ANTENNAGATEAREA 0.593700 ;
    ANTENNADIFFAREA 0.434700 ;
    PORT
      LAYER met4 ;
        RECT 1131.910 0.000 1132.210 1.000 ;
    END
  END um_ow[78]
  PIN um_ow[79]
    DIRECTION INPUT ;
    USE SIGNAL ;
    ANTENNAGATEAREA 0.593700 ;
    ANTENNADIFFAREA 0.434700 ;
    PORT
      LAYER met4 ;
        RECT 1129.150 0.000 1129.450 1.000 ;
    END
  END um_ow[79]
  PIN um_ow[7]
    DIRECTION INPUT ;
    USE SIGNAL ;
    ANTENNAGATEAREA 0.593700 ;
    ANTENNADIFFAREA 0.434700 ;
    PORT
      LAYER met4 ;
        RECT 1303.030 53.400 1303.330 54.400 ;
    END
  END um_ow[7]
  PIN um_ow[80]
    DIRECTION INPUT ;
    USE SIGNAL ;
    ANTENNAGATEAREA 0.593700 ;
    ANTENNADIFFAREA 0.434700 ;
    PORT
      LAYER met4 ;
        RECT 1126.390 0.000 1126.690 1.000 ;
    END
  END um_ow[80]
  PIN um_ow[81]
    DIRECTION INPUT ;
    USE SIGNAL ;
    ANTENNAGATEAREA 0.593700 ;
    ANTENNADIFFAREA 0.434700 ;
    PORT
      LAYER met4 ;
        RECT 1123.630 0.000 1123.930 1.000 ;
    END
  END um_ow[81]
  PIN um_ow[82]
    DIRECTION INPUT ;
    USE SIGNAL ;
    ANTENNAGATEAREA 0.593700 ;
    ANTENNADIFFAREA 0.434700 ;
    PORT
      LAYER met4 ;
        RECT 1120.870 0.000 1121.170 1.000 ;
    END
  END um_ow[82]
  PIN um_ow[83]
    DIRECTION INPUT ;
    USE SIGNAL ;
    ANTENNAGATEAREA 0.593700 ;
    ANTENNADIFFAREA 0.434700 ;
    PORT
      LAYER met4 ;
        RECT 1118.110 0.000 1118.410 1.000 ;
    END
  END um_ow[83]
  PIN um_ow[84]
    DIRECTION INPUT ;
    USE SIGNAL ;
    ANTENNAGATEAREA 0.593700 ;
    ANTENNADIFFAREA 0.434700 ;
    PORT
      LAYER met4 ;
        RECT 1115.350 0.000 1115.650 1.000 ;
    END
  END um_ow[84]
  PIN um_ow[85]
    DIRECTION INPUT ;
    USE SIGNAL ;
    ANTENNAGATEAREA 0.593700 ;
    ANTENNADIFFAREA 0.434700 ;
    PORT
      LAYER met4 ;
        RECT 1112.590 0.000 1112.890 1.000 ;
    END
  END um_ow[85]
  PIN um_ow[86]
    DIRECTION INPUT ;
    USE SIGNAL ;
    ANTENNAGATEAREA 0.593700 ;
    ANTENNADIFFAREA 0.434700 ;
    PORT
      LAYER met4 ;
        RECT 1109.830 0.000 1110.130 1.000 ;
    END
  END um_ow[86]
  PIN um_ow[87]
    DIRECTION INPUT ;
    USE SIGNAL ;
    ANTENNAGATEAREA 0.593700 ;
    ANTENNADIFFAREA 0.434700 ;
    PORT
      LAYER met4 ;
        RECT 1107.070 0.000 1107.370 1.000 ;
    END
  END um_ow[87]
  PIN um_ow[88]
    DIRECTION INPUT ;
    USE SIGNAL ;
    ANTENNAGATEAREA 0.593700 ;
    ANTENNADIFFAREA 0.434700 ;
    PORT
      LAYER met4 ;
        RECT 1104.310 0.000 1104.610 1.000 ;
    END
  END um_ow[88]
  PIN um_ow[89]
    DIRECTION INPUT ;
    USE SIGNAL ;
    ANTENNAGATEAREA 0.593700 ;
    ANTENNADIFFAREA 0.434700 ;
    PORT
      LAYER met4 ;
        RECT 1101.550 0.000 1101.850 1.000 ;
    END
  END um_ow[89]
  PIN um_ow[8]
    DIRECTION INPUT ;
    USE SIGNAL ;
    ANTENNAGATEAREA 0.593700 ;
    ANTENNADIFFAREA 0.434700 ;
    PORT
      LAYER met4 ;
        RECT 1300.270 53.400 1300.570 54.400 ;
    END
  END um_ow[8]
  PIN um_ow[90]
    DIRECTION INPUT ;
    USE SIGNAL ;
    ANTENNAGATEAREA 0.593700 ;
    ANTENNADIFFAREA 0.434700 ;
    PORT
      LAYER met4 ;
        RECT 1098.790 0.000 1099.090 1.000 ;
    END
  END um_ow[90]
  PIN um_ow[91]
    DIRECTION INPUT ;
    USE SIGNAL ;
    ANTENNAGATEAREA 0.593700 ;
    ANTENNADIFFAREA 0.434700 ;
    PORT
      LAYER met4 ;
        RECT 1096.030 0.000 1096.330 1.000 ;
    END
  END um_ow[91]
  PIN um_ow[92]
    DIRECTION INPUT ;
    USE SIGNAL ;
    ANTENNAGATEAREA 0.593700 ;
    ANTENNADIFFAREA 0.434700 ;
    PORT
      LAYER met4 ;
        RECT 1093.270 0.000 1093.570 1.000 ;
    END
  END um_ow[92]
  PIN um_ow[93]
    DIRECTION INPUT ;
    USE SIGNAL ;
    ANTENNAGATEAREA 0.593700 ;
    ANTENNADIFFAREA 0.434700 ;
    PORT
      LAYER met4 ;
        RECT 1090.510 0.000 1090.810 1.000 ;
    END
  END um_ow[93]
  PIN um_ow[94]
    DIRECTION INPUT ;
    USE SIGNAL ;
    ANTENNAGATEAREA 0.593700 ;
    ANTENNADIFFAREA 0.434700 ;
    PORT
      LAYER met4 ;
        RECT 1087.750 0.000 1088.050 1.000 ;
    END
  END um_ow[94]
  PIN um_ow[95]
    DIRECTION INPUT ;
    USE SIGNAL ;
    ANTENNAGATEAREA 0.593700 ;
    ANTENNADIFFAREA 0.434700 ;
    PORT
      LAYER met4 ;
        RECT 1084.990 0.000 1085.290 1.000 ;
    END
  END um_ow[95]
  PIN um_ow[96]
    DIRECTION INPUT ;
    USE SIGNAL ;
    ANTENNAGATEAREA 0.593700 ;
    ANTENNADIFFAREA 0.434700 ;
    PORT
      LAYER met4 ;
        RECT 974.590 53.400 974.890 54.400 ;
    END
  END um_ow[96]
  PIN um_ow[97]
    DIRECTION INPUT ;
    USE SIGNAL ;
    ANTENNAGATEAREA 0.593700 ;
    ANTENNADIFFAREA 0.434700 ;
    PORT
      LAYER met4 ;
        RECT 971.830 53.400 972.130 54.400 ;
    END
  END um_ow[97]
  PIN um_ow[98]
    DIRECTION INPUT ;
    USE SIGNAL ;
    ANTENNAGATEAREA 0.593700 ;
    ANTENNADIFFAREA 0.434700 ;
    PORT
      LAYER met4 ;
        RECT 969.070 53.400 969.370 54.400 ;
    END
  END um_ow[98]
  PIN um_ow[99]
    DIRECTION INPUT ;
    USE SIGNAL ;
    ANTENNAGATEAREA 0.593700 ;
    ANTENNADIFFAREA 0.434700 ;
    PORT
      LAYER met4 ;
        RECT 966.310 53.400 966.610 54.400 ;
    END
  END um_ow[99]
  PIN um_ow[9]
    DIRECTION INPUT ;
    USE SIGNAL ;
    ANTENNAGATEAREA 0.593700 ;
    ANTENNADIFFAREA 0.434700 ;
    PORT
      LAYER met4 ;
        RECT 1297.510 53.400 1297.810 54.400 ;
    END
  END um_ow[9]
  PIN um_pg_ena[0]
    DIRECTION OUTPUT ;
    USE SIGNAL ;
    ANTENNADIFFAREA 1.782000 ;
    PORT
      LAYER met4 ;
        RECT 1218.390 53.400 1218.690 54.400 ;
    END
  END um_pg_ena[0]
  PIN um_pg_ena[10]
    DIRECTION OUTPUT ;
    USE SIGNAL ;
    ANTENNADIFFAREA 1.782000 ;
    PORT
      LAYER met4 ;
        RECT 348.990 53.400 349.290 54.400 ;
    END
  END um_pg_ena[10]
  PIN um_pg_ena[11]
    DIRECTION OUTPUT ;
    USE SIGNAL ;
    ANTENNADIFFAREA 1.782000 ;
    PORT
      LAYER met4 ;
        RECT 348.990 0.000 349.290 1.000 ;
    END
  END um_pg_ena[11]
  PIN um_pg_ena[12]
    DIRECTION OUTPUT ;
    USE SIGNAL ;
    ANTENNADIFFAREA 1.782000 ;
    PORT
      LAYER met4 ;
        RECT 175.110 53.400 175.410 54.400 ;
    END
  END um_pg_ena[12]
  PIN um_pg_ena[13]
    DIRECTION OUTPUT ;
    USE SIGNAL ;
    ANTENNADIFFAREA 1.782000 ;
    PORT
      LAYER met4 ;
        RECT 175.110 0.000 175.410 1.000 ;
    END
  END um_pg_ena[13]
  PIN um_pg_ena[14]
    DIRECTION OUTPUT ;
    USE SIGNAL ;
    ANTENNADIFFAREA 1.782000 ;
    PORT
      LAYER met4 ;
        RECT 1.230 53.400 1.530 54.400 ;
    END
  END um_pg_ena[14]
  PIN um_pg_ena[15]
    DIRECTION OUTPUT ;
    USE SIGNAL ;
    ANTENNADIFFAREA 1.782000 ;
    PORT
      LAYER met4 ;
        RECT 1.230 0.000 1.530 1.000 ;
    END
  END um_pg_ena[15]
  PIN um_pg_ena[1]
    DIRECTION OUTPUT ;
    USE SIGNAL ;
    ANTENNADIFFAREA 1.782000 ;
    PORT
      LAYER met4 ;
        RECT 1218.390 0.000 1218.690 1.000 ;
    END
  END um_pg_ena[1]
  PIN um_pg_ena[2]
    DIRECTION OUTPUT ;
    USE SIGNAL ;
    ANTENNADIFFAREA 1.782000 ;
    PORT
      LAYER met4 ;
        RECT 1044.510 53.400 1044.810 54.400 ;
    END
  END um_pg_ena[2]
  PIN um_pg_ena[3]
    DIRECTION OUTPUT ;
    USE SIGNAL ;
    ANTENNADIFFAREA 1.782000 ;
    PORT
      LAYER met4 ;
        RECT 1044.510 0.000 1044.810 1.000 ;
    END
  END um_pg_ena[3]
  PIN um_pg_ena[4]
    DIRECTION OUTPUT ;
    USE SIGNAL ;
    ANTENNADIFFAREA 1.782000 ;
    PORT
      LAYER met4 ;
        RECT 870.630 53.400 870.930 54.400 ;
    END
  END um_pg_ena[4]
  PIN um_pg_ena[5]
    DIRECTION OUTPUT ;
    USE SIGNAL ;
    ANTENNADIFFAREA 1.782000 ;
    PORT
      LAYER met4 ;
        RECT 870.630 0.000 870.930 1.000 ;
    END
  END um_pg_ena[5]
  PIN um_pg_ena[6]
    DIRECTION OUTPUT ;
    USE SIGNAL ;
    ANTENNADIFFAREA 1.782000 ;
    PORT
      LAYER met4 ;
        RECT 696.750 53.400 697.050 54.400 ;
    END
  END um_pg_ena[6]
  PIN um_pg_ena[7]
    DIRECTION OUTPUT ;
    USE SIGNAL ;
    ANTENNADIFFAREA 1.782000 ;
    PORT
      LAYER met4 ;
        RECT 696.750 0.000 697.050 1.000 ;
    END
  END um_pg_ena[7]
  PIN um_pg_ena[8]
    DIRECTION OUTPUT ;
    USE SIGNAL ;
    ANTENNADIFFAREA 1.782000 ;
    PORT
      LAYER met4 ;
        RECT 522.870 53.400 523.170 54.400 ;
    END
  END um_pg_ena[8]
  PIN um_pg_ena[9]
    DIRECTION OUTPUT ;
    USE SIGNAL ;
    ANTENNADIFFAREA 1.782000 ;
    PORT
      LAYER met4 ;
        RECT 522.870 0.000 523.170 1.000 ;
    END
  END um_pg_ena[9]
  OBS
      LAYER nwell ;
        RECT 2.570 2.635 1386.630 51.765 ;
      LAYER li1 ;
        RECT 2.760 2.635 1386.440 51.765 ;
      LAYER met1 ;
        RECT 2.760 0.040 1386.440 54.360 ;
      LAYER met2 ;
        RECT 18.310 0.010 1386.350 54.390 ;
      LAYER met3 ;
        RECT 1.190 48.490 1388.200 54.225 ;
        RECT 1.190 5.910 1387.800 48.490 ;
        RECT 1.190 0.175 1388.200 5.910 ;
      LAYER met4 ;
        RECT 1.930 53.000 38.550 53.545 ;
        RECT 39.650 53.000 41.310 53.545 ;
        RECT 42.410 53.000 44.070 53.545 ;
        RECT 45.170 53.000 46.830 53.545 ;
        RECT 47.930 53.000 49.590 53.545 ;
        RECT 50.690 53.000 52.350 53.545 ;
        RECT 53.450 53.000 55.110 53.545 ;
        RECT 56.210 53.000 57.870 53.545 ;
        RECT 58.970 53.000 60.630 53.545 ;
        RECT 61.730 53.000 63.390 53.545 ;
        RECT 64.490 53.000 66.150 53.545 ;
        RECT 67.250 53.000 68.910 53.545 ;
        RECT 70.010 53.000 71.670 53.545 ;
        RECT 72.770 53.000 74.430 53.545 ;
        RECT 75.530 53.000 77.190 53.545 ;
        RECT 78.290 53.000 79.950 53.545 ;
        RECT 81.050 53.000 82.710 53.545 ;
        RECT 83.810 53.000 85.470 53.545 ;
        RECT 86.570 53.000 88.230 53.545 ;
        RECT 89.330 53.000 90.990 53.545 ;
        RECT 92.090 53.000 93.750 53.545 ;
        RECT 94.850 53.000 96.510 53.545 ;
        RECT 97.610 53.000 99.270 53.545 ;
        RECT 100.370 53.000 102.030 53.545 ;
        RECT 103.130 53.000 104.790 53.545 ;
        RECT 105.890 53.000 107.550 53.545 ;
        RECT 108.650 53.000 110.310 53.545 ;
        RECT 111.410 53.000 113.070 53.545 ;
        RECT 114.170 53.000 115.830 53.545 ;
        RECT 116.930 53.000 118.590 53.545 ;
        RECT 119.690 53.000 121.350 53.545 ;
        RECT 122.450 53.000 124.110 53.545 ;
        RECT 125.210 53.000 126.870 53.545 ;
        RECT 127.970 53.000 129.630 53.545 ;
        RECT 130.730 53.000 132.390 53.545 ;
        RECT 133.490 53.000 135.150 53.545 ;
        RECT 136.250 53.000 137.910 53.545 ;
        RECT 139.010 53.000 140.670 53.545 ;
        RECT 141.770 53.000 143.430 53.545 ;
        RECT 144.530 53.000 146.190 53.545 ;
        RECT 147.290 53.000 148.950 53.545 ;
        RECT 150.050 53.000 151.710 53.545 ;
        RECT 152.810 53.000 154.470 53.545 ;
        RECT 155.570 53.000 157.230 53.545 ;
        RECT 158.330 53.000 174.710 53.545 ;
        RECT 175.810 53.000 212.430 53.545 ;
        RECT 213.530 53.000 215.190 53.545 ;
        RECT 216.290 53.000 217.950 53.545 ;
        RECT 219.050 53.000 220.710 53.545 ;
        RECT 221.810 53.000 223.470 53.545 ;
        RECT 224.570 53.000 226.230 53.545 ;
        RECT 227.330 53.000 228.990 53.545 ;
        RECT 230.090 53.000 231.750 53.545 ;
        RECT 232.850 53.000 234.510 53.545 ;
        RECT 235.610 53.000 237.270 53.545 ;
        RECT 238.370 53.000 240.030 53.545 ;
        RECT 241.130 53.000 242.790 53.545 ;
        RECT 243.890 53.000 245.550 53.545 ;
        RECT 246.650 53.000 248.310 53.545 ;
        RECT 249.410 53.000 251.070 53.545 ;
        RECT 252.170 53.000 253.830 53.545 ;
        RECT 254.930 53.000 256.590 53.545 ;
        RECT 257.690 53.000 259.350 53.545 ;
        RECT 260.450 53.000 262.110 53.545 ;
        RECT 263.210 53.000 264.870 53.545 ;
        RECT 265.970 53.000 267.630 53.545 ;
        RECT 268.730 53.000 270.390 53.545 ;
        RECT 271.490 53.000 273.150 53.545 ;
        RECT 274.250 53.000 275.910 53.545 ;
        RECT 277.010 53.000 278.670 53.545 ;
        RECT 279.770 53.000 281.430 53.545 ;
        RECT 282.530 53.000 284.190 53.545 ;
        RECT 285.290 53.000 286.950 53.545 ;
        RECT 288.050 53.000 289.710 53.545 ;
        RECT 290.810 53.000 292.470 53.545 ;
        RECT 293.570 53.000 295.230 53.545 ;
        RECT 296.330 53.000 297.990 53.545 ;
        RECT 299.090 53.000 300.750 53.545 ;
        RECT 301.850 53.000 303.510 53.545 ;
        RECT 304.610 53.000 306.270 53.545 ;
        RECT 307.370 53.000 309.030 53.545 ;
        RECT 310.130 53.000 311.790 53.545 ;
        RECT 312.890 53.000 314.550 53.545 ;
        RECT 315.650 53.000 317.310 53.545 ;
        RECT 318.410 53.000 320.070 53.545 ;
        RECT 321.170 53.000 322.830 53.545 ;
        RECT 323.930 53.000 325.590 53.545 ;
        RECT 326.690 53.000 328.350 53.545 ;
        RECT 329.450 53.000 331.110 53.545 ;
        RECT 332.210 53.000 348.590 53.545 ;
        RECT 349.690 53.000 386.310 53.545 ;
        RECT 387.410 53.000 389.070 53.545 ;
        RECT 390.170 53.000 391.830 53.545 ;
        RECT 392.930 53.000 394.590 53.545 ;
        RECT 395.690 53.000 397.350 53.545 ;
        RECT 398.450 53.000 400.110 53.545 ;
        RECT 401.210 53.000 402.870 53.545 ;
        RECT 403.970 53.000 405.630 53.545 ;
        RECT 406.730 53.000 408.390 53.545 ;
        RECT 409.490 53.000 411.150 53.545 ;
        RECT 412.250 53.000 413.910 53.545 ;
        RECT 415.010 53.000 416.670 53.545 ;
        RECT 417.770 53.000 419.430 53.545 ;
        RECT 420.530 53.000 422.190 53.545 ;
        RECT 423.290 53.000 424.950 53.545 ;
        RECT 426.050 53.000 427.710 53.545 ;
        RECT 428.810 53.000 430.470 53.545 ;
        RECT 431.570 53.000 433.230 53.545 ;
        RECT 434.330 53.000 435.990 53.545 ;
        RECT 437.090 53.000 438.750 53.545 ;
        RECT 439.850 53.000 441.510 53.545 ;
        RECT 442.610 53.000 444.270 53.545 ;
        RECT 445.370 53.000 447.030 53.545 ;
        RECT 448.130 53.000 449.790 53.545 ;
        RECT 450.890 53.000 452.550 53.545 ;
        RECT 453.650 53.000 455.310 53.545 ;
        RECT 456.410 53.000 458.070 53.545 ;
        RECT 459.170 53.000 460.830 53.545 ;
        RECT 461.930 53.000 463.590 53.545 ;
        RECT 464.690 53.000 466.350 53.545 ;
        RECT 467.450 53.000 469.110 53.545 ;
        RECT 470.210 53.000 471.870 53.545 ;
        RECT 472.970 53.000 474.630 53.545 ;
        RECT 475.730 53.000 477.390 53.545 ;
        RECT 478.490 53.000 480.150 53.545 ;
        RECT 481.250 53.000 482.910 53.545 ;
        RECT 484.010 53.000 485.670 53.545 ;
        RECT 486.770 53.000 488.430 53.545 ;
        RECT 489.530 53.000 491.190 53.545 ;
        RECT 492.290 53.000 493.950 53.545 ;
        RECT 495.050 53.000 496.710 53.545 ;
        RECT 497.810 53.000 499.470 53.545 ;
        RECT 500.570 53.000 502.230 53.545 ;
        RECT 503.330 53.000 504.990 53.545 ;
        RECT 506.090 53.000 522.470 53.545 ;
        RECT 523.570 53.000 560.190 53.545 ;
        RECT 561.290 53.000 562.950 53.545 ;
        RECT 564.050 53.000 565.710 53.545 ;
        RECT 566.810 53.000 568.470 53.545 ;
        RECT 569.570 53.000 571.230 53.545 ;
        RECT 572.330 53.000 573.990 53.545 ;
        RECT 575.090 53.000 576.750 53.545 ;
        RECT 577.850 53.000 579.510 53.545 ;
        RECT 580.610 53.000 582.270 53.545 ;
        RECT 583.370 53.000 585.030 53.545 ;
        RECT 586.130 53.000 587.790 53.545 ;
        RECT 588.890 53.000 590.550 53.545 ;
        RECT 591.650 53.000 593.310 53.545 ;
        RECT 594.410 53.000 596.070 53.545 ;
        RECT 597.170 53.000 598.830 53.545 ;
        RECT 599.930 53.000 601.590 53.545 ;
        RECT 602.690 53.000 604.350 53.545 ;
        RECT 605.450 53.000 607.110 53.545 ;
        RECT 608.210 53.000 609.870 53.545 ;
        RECT 610.970 53.000 612.630 53.545 ;
        RECT 613.730 53.000 615.390 53.545 ;
        RECT 616.490 53.000 618.150 53.545 ;
        RECT 619.250 53.000 620.910 53.545 ;
        RECT 622.010 53.000 623.670 53.545 ;
        RECT 624.770 53.000 626.430 53.545 ;
        RECT 627.530 53.000 629.190 53.545 ;
        RECT 630.290 53.000 631.950 53.545 ;
        RECT 633.050 53.000 634.710 53.545 ;
        RECT 635.810 53.000 637.470 53.545 ;
        RECT 638.570 53.000 640.230 53.545 ;
        RECT 641.330 53.000 642.990 53.545 ;
        RECT 644.090 53.000 645.750 53.545 ;
        RECT 646.850 53.000 648.510 53.545 ;
        RECT 649.610 53.000 651.270 53.545 ;
        RECT 652.370 53.000 654.030 53.545 ;
        RECT 655.130 53.000 656.790 53.545 ;
        RECT 657.890 53.000 659.550 53.545 ;
        RECT 660.650 53.000 662.310 53.545 ;
        RECT 663.410 53.000 665.070 53.545 ;
        RECT 666.170 53.000 667.830 53.545 ;
        RECT 668.930 53.000 670.590 53.545 ;
        RECT 671.690 53.000 673.350 53.545 ;
        RECT 674.450 53.000 676.110 53.545 ;
        RECT 677.210 53.000 678.870 53.545 ;
        RECT 679.970 53.000 696.350 53.545 ;
        RECT 697.450 53.000 734.070 53.545 ;
        RECT 735.170 53.000 736.830 53.545 ;
        RECT 737.930 53.000 739.590 53.545 ;
        RECT 740.690 53.000 742.350 53.545 ;
        RECT 743.450 53.000 745.110 53.545 ;
        RECT 746.210 53.000 747.870 53.545 ;
        RECT 748.970 53.000 750.630 53.545 ;
        RECT 751.730 53.000 753.390 53.545 ;
        RECT 754.490 53.000 756.150 53.545 ;
        RECT 757.250 53.000 758.910 53.545 ;
        RECT 760.010 53.000 761.670 53.545 ;
        RECT 762.770 53.000 764.430 53.545 ;
        RECT 765.530 53.000 767.190 53.545 ;
        RECT 768.290 53.000 769.950 53.545 ;
        RECT 771.050 53.000 772.710 53.545 ;
        RECT 773.810 53.000 775.470 53.545 ;
        RECT 776.570 53.000 778.230 53.545 ;
        RECT 779.330 53.000 780.990 53.545 ;
        RECT 782.090 53.000 783.750 53.545 ;
        RECT 784.850 53.000 786.510 53.545 ;
        RECT 787.610 53.000 789.270 53.545 ;
        RECT 790.370 53.000 792.030 53.545 ;
        RECT 793.130 53.000 794.790 53.545 ;
        RECT 795.890 53.000 797.550 53.545 ;
        RECT 798.650 53.000 800.310 53.545 ;
        RECT 801.410 53.000 803.070 53.545 ;
        RECT 804.170 53.000 805.830 53.545 ;
        RECT 806.930 53.000 808.590 53.545 ;
        RECT 809.690 53.000 811.350 53.545 ;
        RECT 812.450 53.000 814.110 53.545 ;
        RECT 815.210 53.000 816.870 53.545 ;
        RECT 817.970 53.000 819.630 53.545 ;
        RECT 820.730 53.000 822.390 53.545 ;
        RECT 823.490 53.000 825.150 53.545 ;
        RECT 826.250 53.000 827.910 53.545 ;
        RECT 829.010 53.000 830.670 53.545 ;
        RECT 831.770 53.000 833.430 53.545 ;
        RECT 834.530 53.000 836.190 53.545 ;
        RECT 837.290 53.000 838.950 53.545 ;
        RECT 840.050 53.000 841.710 53.545 ;
        RECT 842.810 53.000 844.470 53.545 ;
        RECT 845.570 53.000 847.230 53.545 ;
        RECT 848.330 53.000 849.990 53.545 ;
        RECT 851.090 53.000 852.750 53.545 ;
        RECT 853.850 53.000 870.230 53.545 ;
        RECT 871.330 53.000 907.950 53.545 ;
        RECT 909.050 53.000 910.710 53.545 ;
        RECT 911.810 53.000 913.470 53.545 ;
        RECT 914.570 53.000 916.230 53.545 ;
        RECT 917.330 53.000 918.990 53.545 ;
        RECT 920.090 53.000 921.750 53.545 ;
        RECT 922.850 53.000 924.510 53.545 ;
        RECT 925.610 53.000 927.270 53.545 ;
        RECT 928.370 53.000 930.030 53.545 ;
        RECT 931.130 53.000 932.790 53.545 ;
        RECT 933.890 53.000 935.550 53.545 ;
        RECT 936.650 53.000 938.310 53.545 ;
        RECT 939.410 53.000 941.070 53.545 ;
        RECT 942.170 53.000 943.830 53.545 ;
        RECT 944.930 53.000 946.590 53.545 ;
        RECT 947.690 53.000 949.350 53.545 ;
        RECT 950.450 53.000 952.110 53.545 ;
        RECT 953.210 53.000 954.870 53.545 ;
        RECT 955.970 53.000 957.630 53.545 ;
        RECT 958.730 53.000 960.390 53.545 ;
        RECT 961.490 53.000 963.150 53.545 ;
        RECT 964.250 53.000 965.910 53.545 ;
        RECT 967.010 53.000 968.670 53.545 ;
        RECT 969.770 53.000 971.430 53.545 ;
        RECT 972.530 53.000 974.190 53.545 ;
        RECT 975.290 53.000 976.950 53.545 ;
        RECT 978.050 53.000 979.710 53.545 ;
        RECT 980.810 53.000 982.470 53.545 ;
        RECT 983.570 53.000 985.230 53.545 ;
        RECT 986.330 53.000 987.990 53.545 ;
        RECT 989.090 53.000 990.750 53.545 ;
        RECT 991.850 53.000 993.510 53.545 ;
        RECT 994.610 53.000 996.270 53.545 ;
        RECT 997.370 53.000 999.030 53.545 ;
        RECT 1000.130 53.000 1001.790 53.545 ;
        RECT 1002.890 53.000 1004.550 53.545 ;
        RECT 1005.650 53.000 1007.310 53.545 ;
        RECT 1008.410 53.000 1010.070 53.545 ;
        RECT 1011.170 53.000 1012.830 53.545 ;
        RECT 1013.930 53.000 1015.590 53.545 ;
        RECT 1016.690 53.000 1018.350 53.545 ;
        RECT 1019.450 53.000 1021.110 53.545 ;
        RECT 1022.210 53.000 1023.870 53.545 ;
        RECT 1024.970 53.000 1026.630 53.545 ;
        RECT 1027.730 53.000 1044.110 53.545 ;
        RECT 1045.210 53.000 1081.830 53.545 ;
        RECT 1082.930 53.000 1084.590 53.545 ;
        RECT 1085.690 53.000 1087.350 53.545 ;
        RECT 1088.450 53.000 1090.110 53.545 ;
        RECT 1091.210 53.000 1092.870 53.545 ;
        RECT 1093.970 53.000 1095.630 53.545 ;
        RECT 1096.730 53.000 1098.390 53.545 ;
        RECT 1099.490 53.000 1101.150 53.545 ;
        RECT 1102.250 53.000 1103.910 53.545 ;
        RECT 1105.010 53.000 1106.670 53.545 ;
        RECT 1107.770 53.000 1109.430 53.545 ;
        RECT 1110.530 53.000 1112.190 53.545 ;
        RECT 1113.290 53.000 1114.950 53.545 ;
        RECT 1116.050 53.000 1117.710 53.545 ;
        RECT 1118.810 53.000 1120.470 53.545 ;
        RECT 1121.570 53.000 1123.230 53.545 ;
        RECT 1124.330 53.000 1125.990 53.545 ;
        RECT 1127.090 53.000 1128.750 53.545 ;
        RECT 1129.850 53.000 1131.510 53.545 ;
        RECT 1132.610 53.000 1134.270 53.545 ;
        RECT 1135.370 53.000 1137.030 53.545 ;
        RECT 1138.130 53.000 1139.790 53.545 ;
        RECT 1140.890 53.000 1142.550 53.545 ;
        RECT 1143.650 53.000 1145.310 53.545 ;
        RECT 1146.410 53.000 1148.070 53.545 ;
        RECT 1149.170 53.000 1150.830 53.545 ;
        RECT 1151.930 53.000 1153.590 53.545 ;
        RECT 1154.690 53.000 1156.350 53.545 ;
        RECT 1157.450 53.000 1159.110 53.545 ;
        RECT 1160.210 53.000 1161.870 53.545 ;
        RECT 1162.970 53.000 1164.630 53.545 ;
        RECT 1165.730 53.000 1167.390 53.545 ;
        RECT 1168.490 53.000 1170.150 53.545 ;
        RECT 1171.250 53.000 1172.910 53.545 ;
        RECT 1174.010 53.000 1175.670 53.545 ;
        RECT 1176.770 53.000 1178.430 53.545 ;
        RECT 1179.530 53.000 1181.190 53.545 ;
        RECT 1182.290 53.000 1183.950 53.545 ;
        RECT 1185.050 53.000 1186.710 53.545 ;
        RECT 1187.810 53.000 1189.470 53.545 ;
        RECT 1190.570 53.000 1192.230 53.545 ;
        RECT 1193.330 53.000 1194.990 53.545 ;
        RECT 1196.090 53.000 1197.750 53.545 ;
        RECT 1198.850 53.000 1200.510 53.545 ;
        RECT 1201.610 53.000 1217.990 53.545 ;
        RECT 1219.090 53.000 1255.710 53.545 ;
        RECT 1256.810 53.000 1258.470 53.545 ;
        RECT 1259.570 53.000 1261.230 53.545 ;
        RECT 1262.330 53.000 1263.990 53.545 ;
        RECT 1265.090 53.000 1266.750 53.545 ;
        RECT 1267.850 53.000 1269.510 53.545 ;
        RECT 1270.610 53.000 1272.270 53.545 ;
        RECT 1273.370 53.000 1275.030 53.545 ;
        RECT 1276.130 53.000 1277.790 53.545 ;
        RECT 1278.890 53.000 1280.550 53.545 ;
        RECT 1281.650 53.000 1283.310 53.545 ;
        RECT 1284.410 53.000 1286.070 53.545 ;
        RECT 1287.170 53.000 1288.830 53.545 ;
        RECT 1289.930 53.000 1291.590 53.545 ;
        RECT 1292.690 53.000 1294.350 53.545 ;
        RECT 1295.450 53.000 1297.110 53.545 ;
        RECT 1298.210 53.000 1299.870 53.545 ;
        RECT 1300.970 53.000 1302.630 53.545 ;
        RECT 1303.730 53.000 1305.390 53.545 ;
        RECT 1306.490 53.000 1308.150 53.545 ;
        RECT 1309.250 53.000 1310.910 53.545 ;
        RECT 1312.010 53.000 1313.670 53.545 ;
        RECT 1314.770 53.000 1316.430 53.545 ;
        RECT 1317.530 53.000 1319.190 53.545 ;
        RECT 1320.290 53.000 1321.950 53.545 ;
        RECT 1323.050 53.000 1324.710 53.545 ;
        RECT 1325.810 53.000 1327.470 53.545 ;
        RECT 1328.570 53.000 1330.230 53.545 ;
        RECT 1331.330 53.000 1332.990 53.545 ;
        RECT 1334.090 53.000 1335.750 53.545 ;
        RECT 1336.850 53.000 1338.510 53.545 ;
        RECT 1339.610 53.000 1341.270 53.545 ;
        RECT 1342.370 53.000 1344.030 53.545 ;
        RECT 1345.130 53.000 1346.790 53.545 ;
        RECT 1347.890 53.000 1349.550 53.545 ;
        RECT 1350.650 53.000 1352.310 53.545 ;
        RECT 1353.410 53.000 1355.070 53.545 ;
        RECT 1356.170 53.000 1357.830 53.545 ;
        RECT 1358.930 53.000 1360.590 53.545 ;
        RECT 1361.690 53.000 1363.350 53.545 ;
        RECT 1364.450 53.000 1366.110 53.545 ;
        RECT 1367.210 53.000 1368.870 53.545 ;
        RECT 1369.970 53.000 1371.630 53.545 ;
        RECT 1372.730 53.000 1374.390 53.545 ;
        RECT 1.215 52.320 1375.105 53.000 ;
        RECT 1.215 2.080 17.880 52.320 ;
        RECT 20.280 2.080 21.180 52.320 ;
        RECT 23.580 2.080 171.480 52.320 ;
        RECT 173.880 2.080 174.780 52.320 ;
        RECT 177.180 2.080 325.080 52.320 ;
        RECT 327.480 2.080 328.380 52.320 ;
        RECT 330.780 2.080 478.680 52.320 ;
        RECT 481.080 2.080 481.980 52.320 ;
        RECT 484.380 2.080 632.280 52.320 ;
        RECT 634.680 2.080 635.580 52.320 ;
        RECT 637.980 2.080 785.880 52.320 ;
        RECT 788.280 2.080 789.180 52.320 ;
        RECT 791.580 2.080 939.480 52.320 ;
        RECT 941.880 2.080 942.780 52.320 ;
        RECT 945.180 2.080 1093.080 52.320 ;
        RECT 1095.480 2.080 1096.380 52.320 ;
        RECT 1098.780 2.080 1246.680 52.320 ;
        RECT 1249.080 2.080 1249.980 52.320 ;
        RECT 1252.380 2.080 1375.105 52.320 ;
        RECT 1.215 1.400 1375.105 2.080 ;
        RECT 1.930 0.855 38.550 1.400 ;
        RECT 39.650 0.855 41.310 1.400 ;
        RECT 42.410 0.855 44.070 1.400 ;
        RECT 45.170 0.855 46.830 1.400 ;
        RECT 47.930 0.855 49.590 1.400 ;
        RECT 50.690 0.855 52.350 1.400 ;
        RECT 53.450 0.855 55.110 1.400 ;
        RECT 56.210 0.855 57.870 1.400 ;
        RECT 58.970 0.855 60.630 1.400 ;
        RECT 61.730 0.855 63.390 1.400 ;
        RECT 64.490 0.855 66.150 1.400 ;
        RECT 67.250 0.855 68.910 1.400 ;
        RECT 70.010 0.855 71.670 1.400 ;
        RECT 72.770 0.855 74.430 1.400 ;
        RECT 75.530 0.855 77.190 1.400 ;
        RECT 78.290 0.855 79.950 1.400 ;
        RECT 81.050 0.855 82.710 1.400 ;
        RECT 83.810 0.855 85.470 1.400 ;
        RECT 86.570 0.855 88.230 1.400 ;
        RECT 89.330 0.855 90.990 1.400 ;
        RECT 92.090 0.855 93.750 1.400 ;
        RECT 94.850 0.855 96.510 1.400 ;
        RECT 97.610 0.855 99.270 1.400 ;
        RECT 100.370 0.855 102.030 1.400 ;
        RECT 103.130 0.855 104.790 1.400 ;
        RECT 105.890 0.855 107.550 1.400 ;
        RECT 108.650 0.855 110.310 1.400 ;
        RECT 111.410 0.855 113.070 1.400 ;
        RECT 114.170 0.855 115.830 1.400 ;
        RECT 116.930 0.855 118.590 1.400 ;
        RECT 119.690 0.855 121.350 1.400 ;
        RECT 122.450 0.855 124.110 1.400 ;
        RECT 125.210 0.855 126.870 1.400 ;
        RECT 127.970 0.855 129.630 1.400 ;
        RECT 130.730 0.855 132.390 1.400 ;
        RECT 133.490 0.855 135.150 1.400 ;
        RECT 136.250 0.855 137.910 1.400 ;
        RECT 139.010 0.855 140.670 1.400 ;
        RECT 141.770 0.855 143.430 1.400 ;
        RECT 144.530 0.855 146.190 1.400 ;
        RECT 147.290 0.855 148.950 1.400 ;
        RECT 150.050 0.855 151.710 1.400 ;
        RECT 152.810 0.855 154.470 1.400 ;
        RECT 155.570 0.855 157.230 1.400 ;
        RECT 158.330 0.855 174.710 1.400 ;
        RECT 175.810 0.855 212.430 1.400 ;
        RECT 213.530 0.855 215.190 1.400 ;
        RECT 216.290 0.855 217.950 1.400 ;
        RECT 219.050 0.855 220.710 1.400 ;
        RECT 221.810 0.855 223.470 1.400 ;
        RECT 224.570 0.855 226.230 1.400 ;
        RECT 227.330 0.855 228.990 1.400 ;
        RECT 230.090 0.855 231.750 1.400 ;
        RECT 232.850 0.855 234.510 1.400 ;
        RECT 235.610 0.855 237.270 1.400 ;
        RECT 238.370 0.855 240.030 1.400 ;
        RECT 241.130 0.855 242.790 1.400 ;
        RECT 243.890 0.855 245.550 1.400 ;
        RECT 246.650 0.855 248.310 1.400 ;
        RECT 249.410 0.855 251.070 1.400 ;
        RECT 252.170 0.855 253.830 1.400 ;
        RECT 254.930 0.855 256.590 1.400 ;
        RECT 257.690 0.855 259.350 1.400 ;
        RECT 260.450 0.855 262.110 1.400 ;
        RECT 263.210 0.855 264.870 1.400 ;
        RECT 265.970 0.855 267.630 1.400 ;
        RECT 268.730 0.855 270.390 1.400 ;
        RECT 271.490 0.855 273.150 1.400 ;
        RECT 274.250 0.855 275.910 1.400 ;
        RECT 277.010 0.855 278.670 1.400 ;
        RECT 279.770 0.855 281.430 1.400 ;
        RECT 282.530 0.855 284.190 1.400 ;
        RECT 285.290 0.855 286.950 1.400 ;
        RECT 288.050 0.855 289.710 1.400 ;
        RECT 290.810 0.855 292.470 1.400 ;
        RECT 293.570 0.855 295.230 1.400 ;
        RECT 296.330 0.855 297.990 1.400 ;
        RECT 299.090 0.855 300.750 1.400 ;
        RECT 301.850 0.855 303.510 1.400 ;
        RECT 304.610 0.855 306.270 1.400 ;
        RECT 307.370 0.855 309.030 1.400 ;
        RECT 310.130 0.855 311.790 1.400 ;
        RECT 312.890 0.855 314.550 1.400 ;
        RECT 315.650 0.855 317.310 1.400 ;
        RECT 318.410 0.855 320.070 1.400 ;
        RECT 321.170 0.855 322.830 1.400 ;
        RECT 323.930 0.855 325.590 1.400 ;
        RECT 326.690 0.855 328.350 1.400 ;
        RECT 329.450 0.855 331.110 1.400 ;
        RECT 332.210 0.855 348.590 1.400 ;
        RECT 349.690 0.855 386.310 1.400 ;
        RECT 387.410 0.855 389.070 1.400 ;
        RECT 390.170 0.855 391.830 1.400 ;
        RECT 392.930 0.855 394.590 1.400 ;
        RECT 395.690 0.855 397.350 1.400 ;
        RECT 398.450 0.855 400.110 1.400 ;
        RECT 401.210 0.855 402.870 1.400 ;
        RECT 403.970 0.855 405.630 1.400 ;
        RECT 406.730 0.855 408.390 1.400 ;
        RECT 409.490 0.855 411.150 1.400 ;
        RECT 412.250 0.855 413.910 1.400 ;
        RECT 415.010 0.855 416.670 1.400 ;
        RECT 417.770 0.855 419.430 1.400 ;
        RECT 420.530 0.855 422.190 1.400 ;
        RECT 423.290 0.855 424.950 1.400 ;
        RECT 426.050 0.855 427.710 1.400 ;
        RECT 428.810 0.855 430.470 1.400 ;
        RECT 431.570 0.855 433.230 1.400 ;
        RECT 434.330 0.855 435.990 1.400 ;
        RECT 437.090 0.855 438.750 1.400 ;
        RECT 439.850 0.855 441.510 1.400 ;
        RECT 442.610 0.855 444.270 1.400 ;
        RECT 445.370 0.855 447.030 1.400 ;
        RECT 448.130 0.855 449.790 1.400 ;
        RECT 450.890 0.855 452.550 1.400 ;
        RECT 453.650 0.855 455.310 1.400 ;
        RECT 456.410 0.855 458.070 1.400 ;
        RECT 459.170 0.855 460.830 1.400 ;
        RECT 461.930 0.855 463.590 1.400 ;
        RECT 464.690 0.855 466.350 1.400 ;
        RECT 467.450 0.855 469.110 1.400 ;
        RECT 470.210 0.855 471.870 1.400 ;
        RECT 472.970 0.855 474.630 1.400 ;
        RECT 475.730 0.855 477.390 1.400 ;
        RECT 478.490 0.855 480.150 1.400 ;
        RECT 481.250 0.855 482.910 1.400 ;
        RECT 484.010 0.855 485.670 1.400 ;
        RECT 486.770 0.855 488.430 1.400 ;
        RECT 489.530 0.855 491.190 1.400 ;
        RECT 492.290 0.855 493.950 1.400 ;
        RECT 495.050 0.855 496.710 1.400 ;
        RECT 497.810 0.855 499.470 1.400 ;
        RECT 500.570 0.855 502.230 1.400 ;
        RECT 503.330 0.855 504.990 1.400 ;
        RECT 506.090 0.855 522.470 1.400 ;
        RECT 523.570 0.855 560.190 1.400 ;
        RECT 561.290 0.855 562.950 1.400 ;
        RECT 564.050 0.855 565.710 1.400 ;
        RECT 566.810 0.855 568.470 1.400 ;
        RECT 569.570 0.855 571.230 1.400 ;
        RECT 572.330 0.855 573.990 1.400 ;
        RECT 575.090 0.855 576.750 1.400 ;
        RECT 577.850 0.855 579.510 1.400 ;
        RECT 580.610 0.855 582.270 1.400 ;
        RECT 583.370 0.855 585.030 1.400 ;
        RECT 586.130 0.855 587.790 1.400 ;
        RECT 588.890 0.855 590.550 1.400 ;
        RECT 591.650 0.855 593.310 1.400 ;
        RECT 594.410 0.855 596.070 1.400 ;
        RECT 597.170 0.855 598.830 1.400 ;
        RECT 599.930 0.855 601.590 1.400 ;
        RECT 602.690 0.855 604.350 1.400 ;
        RECT 605.450 0.855 607.110 1.400 ;
        RECT 608.210 0.855 609.870 1.400 ;
        RECT 610.970 0.855 612.630 1.400 ;
        RECT 613.730 0.855 615.390 1.400 ;
        RECT 616.490 0.855 618.150 1.400 ;
        RECT 619.250 0.855 620.910 1.400 ;
        RECT 622.010 0.855 623.670 1.400 ;
        RECT 624.770 0.855 626.430 1.400 ;
        RECT 627.530 0.855 629.190 1.400 ;
        RECT 630.290 0.855 631.950 1.400 ;
        RECT 633.050 0.855 634.710 1.400 ;
        RECT 635.810 0.855 637.470 1.400 ;
        RECT 638.570 0.855 640.230 1.400 ;
        RECT 641.330 0.855 642.990 1.400 ;
        RECT 644.090 0.855 645.750 1.400 ;
        RECT 646.850 0.855 648.510 1.400 ;
        RECT 649.610 0.855 651.270 1.400 ;
        RECT 652.370 0.855 654.030 1.400 ;
        RECT 655.130 0.855 656.790 1.400 ;
        RECT 657.890 0.855 659.550 1.400 ;
        RECT 660.650 0.855 662.310 1.400 ;
        RECT 663.410 0.855 665.070 1.400 ;
        RECT 666.170 0.855 667.830 1.400 ;
        RECT 668.930 0.855 670.590 1.400 ;
        RECT 671.690 0.855 673.350 1.400 ;
        RECT 674.450 0.855 676.110 1.400 ;
        RECT 677.210 0.855 678.870 1.400 ;
        RECT 679.970 0.855 696.350 1.400 ;
        RECT 697.450 0.855 734.070 1.400 ;
        RECT 735.170 0.855 736.830 1.400 ;
        RECT 737.930 0.855 739.590 1.400 ;
        RECT 740.690 0.855 742.350 1.400 ;
        RECT 743.450 0.855 745.110 1.400 ;
        RECT 746.210 0.855 747.870 1.400 ;
        RECT 748.970 0.855 750.630 1.400 ;
        RECT 751.730 0.855 753.390 1.400 ;
        RECT 754.490 0.855 756.150 1.400 ;
        RECT 757.250 0.855 758.910 1.400 ;
        RECT 760.010 0.855 761.670 1.400 ;
        RECT 762.770 0.855 764.430 1.400 ;
        RECT 765.530 0.855 767.190 1.400 ;
        RECT 768.290 0.855 769.950 1.400 ;
        RECT 771.050 0.855 772.710 1.400 ;
        RECT 773.810 0.855 775.470 1.400 ;
        RECT 776.570 0.855 778.230 1.400 ;
        RECT 779.330 0.855 780.990 1.400 ;
        RECT 782.090 0.855 783.750 1.400 ;
        RECT 784.850 0.855 786.510 1.400 ;
        RECT 787.610 0.855 789.270 1.400 ;
        RECT 790.370 0.855 792.030 1.400 ;
        RECT 793.130 0.855 794.790 1.400 ;
        RECT 795.890 0.855 797.550 1.400 ;
        RECT 798.650 0.855 800.310 1.400 ;
        RECT 801.410 0.855 803.070 1.400 ;
        RECT 804.170 0.855 805.830 1.400 ;
        RECT 806.930 0.855 808.590 1.400 ;
        RECT 809.690 0.855 811.350 1.400 ;
        RECT 812.450 0.855 814.110 1.400 ;
        RECT 815.210 0.855 816.870 1.400 ;
        RECT 817.970 0.855 819.630 1.400 ;
        RECT 820.730 0.855 822.390 1.400 ;
        RECT 823.490 0.855 825.150 1.400 ;
        RECT 826.250 0.855 827.910 1.400 ;
        RECT 829.010 0.855 830.670 1.400 ;
        RECT 831.770 0.855 833.430 1.400 ;
        RECT 834.530 0.855 836.190 1.400 ;
        RECT 837.290 0.855 838.950 1.400 ;
        RECT 840.050 0.855 841.710 1.400 ;
        RECT 842.810 0.855 844.470 1.400 ;
        RECT 845.570 0.855 847.230 1.400 ;
        RECT 848.330 0.855 849.990 1.400 ;
        RECT 851.090 0.855 852.750 1.400 ;
        RECT 853.850 0.855 870.230 1.400 ;
        RECT 871.330 0.855 907.950 1.400 ;
        RECT 909.050 0.855 910.710 1.400 ;
        RECT 911.810 0.855 913.470 1.400 ;
        RECT 914.570 0.855 916.230 1.400 ;
        RECT 917.330 0.855 918.990 1.400 ;
        RECT 920.090 0.855 921.750 1.400 ;
        RECT 922.850 0.855 924.510 1.400 ;
        RECT 925.610 0.855 927.270 1.400 ;
        RECT 928.370 0.855 930.030 1.400 ;
        RECT 931.130 0.855 932.790 1.400 ;
        RECT 933.890 0.855 935.550 1.400 ;
        RECT 936.650 0.855 938.310 1.400 ;
        RECT 939.410 0.855 941.070 1.400 ;
        RECT 942.170 0.855 943.830 1.400 ;
        RECT 944.930 0.855 946.590 1.400 ;
        RECT 947.690 0.855 949.350 1.400 ;
        RECT 950.450 0.855 952.110 1.400 ;
        RECT 953.210 0.855 954.870 1.400 ;
        RECT 955.970 0.855 957.630 1.400 ;
        RECT 958.730 0.855 960.390 1.400 ;
        RECT 961.490 0.855 963.150 1.400 ;
        RECT 964.250 0.855 965.910 1.400 ;
        RECT 967.010 0.855 968.670 1.400 ;
        RECT 969.770 0.855 971.430 1.400 ;
        RECT 972.530 0.855 974.190 1.400 ;
        RECT 975.290 0.855 976.950 1.400 ;
        RECT 978.050 0.855 979.710 1.400 ;
        RECT 980.810 0.855 982.470 1.400 ;
        RECT 983.570 0.855 985.230 1.400 ;
        RECT 986.330 0.855 987.990 1.400 ;
        RECT 989.090 0.855 990.750 1.400 ;
        RECT 991.850 0.855 993.510 1.400 ;
        RECT 994.610 0.855 996.270 1.400 ;
        RECT 997.370 0.855 999.030 1.400 ;
        RECT 1000.130 0.855 1001.790 1.400 ;
        RECT 1002.890 0.855 1004.550 1.400 ;
        RECT 1005.650 0.855 1007.310 1.400 ;
        RECT 1008.410 0.855 1010.070 1.400 ;
        RECT 1011.170 0.855 1012.830 1.400 ;
        RECT 1013.930 0.855 1015.590 1.400 ;
        RECT 1016.690 0.855 1018.350 1.400 ;
        RECT 1019.450 0.855 1021.110 1.400 ;
        RECT 1022.210 0.855 1023.870 1.400 ;
        RECT 1024.970 0.855 1026.630 1.400 ;
        RECT 1027.730 0.855 1044.110 1.400 ;
        RECT 1045.210 0.855 1081.830 1.400 ;
        RECT 1082.930 0.855 1084.590 1.400 ;
        RECT 1085.690 0.855 1087.350 1.400 ;
        RECT 1088.450 0.855 1090.110 1.400 ;
        RECT 1091.210 0.855 1092.870 1.400 ;
        RECT 1093.970 0.855 1095.630 1.400 ;
        RECT 1096.730 0.855 1098.390 1.400 ;
        RECT 1099.490 0.855 1101.150 1.400 ;
        RECT 1102.250 0.855 1103.910 1.400 ;
        RECT 1105.010 0.855 1106.670 1.400 ;
        RECT 1107.770 0.855 1109.430 1.400 ;
        RECT 1110.530 0.855 1112.190 1.400 ;
        RECT 1113.290 0.855 1114.950 1.400 ;
        RECT 1116.050 0.855 1117.710 1.400 ;
        RECT 1118.810 0.855 1120.470 1.400 ;
        RECT 1121.570 0.855 1123.230 1.400 ;
        RECT 1124.330 0.855 1125.990 1.400 ;
        RECT 1127.090 0.855 1128.750 1.400 ;
        RECT 1129.850 0.855 1131.510 1.400 ;
        RECT 1132.610 0.855 1134.270 1.400 ;
        RECT 1135.370 0.855 1137.030 1.400 ;
        RECT 1138.130 0.855 1139.790 1.400 ;
        RECT 1140.890 0.855 1142.550 1.400 ;
        RECT 1143.650 0.855 1145.310 1.400 ;
        RECT 1146.410 0.855 1148.070 1.400 ;
        RECT 1149.170 0.855 1150.830 1.400 ;
        RECT 1151.930 0.855 1153.590 1.400 ;
        RECT 1154.690 0.855 1156.350 1.400 ;
        RECT 1157.450 0.855 1159.110 1.400 ;
        RECT 1160.210 0.855 1161.870 1.400 ;
        RECT 1162.970 0.855 1164.630 1.400 ;
        RECT 1165.730 0.855 1167.390 1.400 ;
        RECT 1168.490 0.855 1170.150 1.400 ;
        RECT 1171.250 0.855 1172.910 1.400 ;
        RECT 1174.010 0.855 1175.670 1.400 ;
        RECT 1176.770 0.855 1178.430 1.400 ;
        RECT 1179.530 0.855 1181.190 1.400 ;
        RECT 1182.290 0.855 1183.950 1.400 ;
        RECT 1185.050 0.855 1186.710 1.400 ;
        RECT 1187.810 0.855 1189.470 1.400 ;
        RECT 1190.570 0.855 1192.230 1.400 ;
        RECT 1193.330 0.855 1194.990 1.400 ;
        RECT 1196.090 0.855 1197.750 1.400 ;
        RECT 1198.850 0.855 1200.510 1.400 ;
        RECT 1201.610 0.855 1217.990 1.400 ;
        RECT 1219.090 0.855 1255.710 1.400 ;
        RECT 1256.810 0.855 1258.470 1.400 ;
        RECT 1259.570 0.855 1261.230 1.400 ;
        RECT 1262.330 0.855 1263.990 1.400 ;
        RECT 1265.090 0.855 1266.750 1.400 ;
        RECT 1267.850 0.855 1269.510 1.400 ;
        RECT 1270.610 0.855 1272.270 1.400 ;
        RECT 1273.370 0.855 1275.030 1.400 ;
        RECT 1276.130 0.855 1277.790 1.400 ;
        RECT 1278.890 0.855 1280.550 1.400 ;
        RECT 1281.650 0.855 1283.310 1.400 ;
        RECT 1284.410 0.855 1286.070 1.400 ;
        RECT 1287.170 0.855 1288.830 1.400 ;
        RECT 1289.930 0.855 1291.590 1.400 ;
        RECT 1292.690 0.855 1294.350 1.400 ;
        RECT 1295.450 0.855 1297.110 1.400 ;
        RECT 1298.210 0.855 1299.870 1.400 ;
        RECT 1300.970 0.855 1302.630 1.400 ;
        RECT 1303.730 0.855 1305.390 1.400 ;
        RECT 1306.490 0.855 1308.150 1.400 ;
        RECT 1309.250 0.855 1310.910 1.400 ;
        RECT 1312.010 0.855 1313.670 1.400 ;
        RECT 1314.770 0.855 1316.430 1.400 ;
        RECT 1317.530 0.855 1319.190 1.400 ;
        RECT 1320.290 0.855 1321.950 1.400 ;
        RECT 1323.050 0.855 1324.710 1.400 ;
        RECT 1325.810 0.855 1327.470 1.400 ;
        RECT 1328.570 0.855 1330.230 1.400 ;
        RECT 1331.330 0.855 1332.990 1.400 ;
        RECT 1334.090 0.855 1335.750 1.400 ;
        RECT 1336.850 0.855 1338.510 1.400 ;
        RECT 1339.610 0.855 1341.270 1.400 ;
        RECT 1342.370 0.855 1344.030 1.400 ;
        RECT 1345.130 0.855 1346.790 1.400 ;
        RECT 1347.890 0.855 1349.550 1.400 ;
        RECT 1350.650 0.855 1352.310 1.400 ;
        RECT 1353.410 0.855 1355.070 1.400 ;
        RECT 1356.170 0.855 1357.830 1.400 ;
        RECT 1358.930 0.855 1360.590 1.400 ;
        RECT 1361.690 0.855 1363.350 1.400 ;
        RECT 1364.450 0.855 1366.110 1.400 ;
        RECT 1367.210 0.855 1368.870 1.400 ;
        RECT 1369.970 0.855 1371.630 1.400 ;
        RECT 1372.730 0.855 1374.390 1.400 ;
  END
END tt_mux
END LIBRARY

